VERSION 5.8 ;
BUSBITCHARS "[]" ;
DIVIDERCHAR "/" ;
UNITS
    DATABASE MICRONS 1000 ;
END UNITS

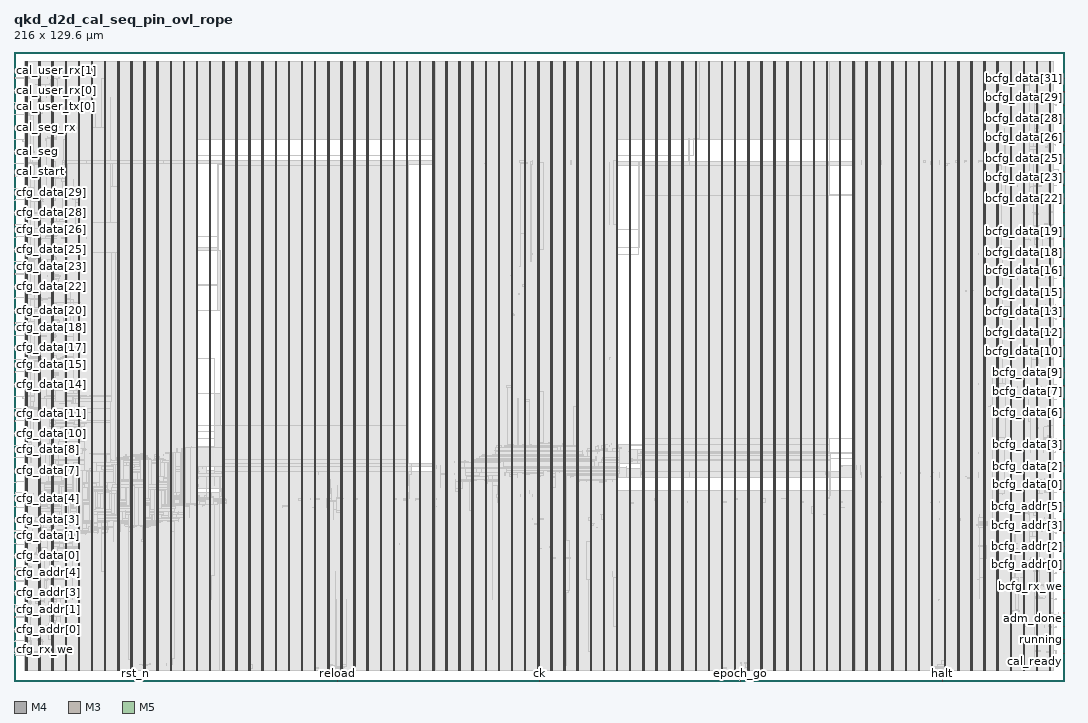
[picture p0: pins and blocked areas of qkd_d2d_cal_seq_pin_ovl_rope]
MACRO qkd_d2d_cal_seq_pin_ovl_rope
  FOREIGN qkd_d2d_cal_seq_pin_ovl_rope 0 0 ;
  CLASS BLOCK ;
  SIZE 216 BY 129.6 ;
  PIN adm_done
    DIRECTION OUTPUT ;
    USE SIGNAL ;
    PORT
      LAYER M4 ;
        RECT  215.808 11.184 216 11.208 ;
    END
  END adm_done
  PIN bcfg_addr[0]
    DIRECTION INPUT ;
    USE SIGNAL ;
    PORT
      LAYER M4 ;
        RECT  215.808 22.224 216 22.248 ;
    END
  END bcfg_addr[0]
  PIN bcfg_addr[1]
    DIRECTION INPUT ;
    USE SIGNAL ;
    PORT
      LAYER M4 ;
        RECT  215.808 24.96 216 24.984 ;
    END
  END bcfg_addr[1]
  PIN bcfg_addr[2]
    DIRECTION INPUT ;
    USE SIGNAL ;
    PORT
      LAYER M4 ;
        RECT  215.808 27.696 216 27.72 ;
    END
  END bcfg_addr[2]
  PIN bcfg_addr[3]
    DIRECTION INPUT ;
    USE SIGNAL ;
    PORT
      LAYER M4 ;
        RECT  215.808 30.432 216 30.456 ;
    END
  END bcfg_addr[3]
  PIN bcfg_addr[4]
    DIRECTION INPUT ;
    USE SIGNAL ;
    PORT
      LAYER M4 ;
        RECT  215.808 33.216 216 33.24 ;
    END
  END bcfg_addr[4]
  PIN bcfg_addr[5]
    DIRECTION INPUT ;
    USE SIGNAL ;
    PORT
      LAYER M4 ;
        RECT  215.808 35.952 216 35.976 ;
    END
  END bcfg_addr[5]
  PIN bcfg_data[0]
    DIRECTION INPUT ;
    USE SIGNAL ;
    PORT
      LAYER M4 ;
        RECT  215.808 38.688 216 38.712 ;
    END
  END bcfg_data[0]
  PIN bcfg_data[10]
    DIRECTION INPUT ;
    USE SIGNAL ;
    PORT
      LAYER M4 ;
        RECT  215.808 66.192 216 66.216 ;
    END
  END bcfg_data[10]
  PIN bcfg_data[11]
    DIRECTION INPUT ;
    USE SIGNAL ;
    PORT
      LAYER M4 ;
        RECT  215.808 68.928 216 68.952 ;
    END
  END bcfg_data[11]
  PIN bcfg_data[12]
    DIRECTION INPUT ;
    USE SIGNAL ;
    PORT
      LAYER M4 ;
        RECT  215.808 71.664 216 71.688 ;
    END
  END bcfg_data[12]
  PIN bcfg_data[13]
    DIRECTION INPUT ;
    USE SIGNAL ;
    PORT
      LAYER M4 ;
        RECT  215.808 74.448 216 74.472 ;
    END
  END bcfg_data[13]
  PIN bcfg_data[14]
    DIRECTION INPUT ;
    USE SIGNAL ;
    PORT
      LAYER M4 ;
        RECT  215.808 77.184 216 77.208 ;
    END
  END bcfg_data[14]
  PIN bcfg_data[15]
    DIRECTION INPUT ;
    USE SIGNAL ;
    PORT
      LAYER M4 ;
        RECT  215.808 79.92 216 79.944 ;
    END
  END bcfg_data[15]
  PIN bcfg_data[16]
    DIRECTION INPUT ;
    USE SIGNAL ;
    PORT
      LAYER M4 ;
        RECT  215.808 82.704 216 82.728 ;
    END
  END bcfg_data[16]
  PIN bcfg_data[17]
    DIRECTION INPUT ;
    USE SIGNAL ;
    PORT
      LAYER M4 ;
        RECT  215.808 85.44 216 85.464 ;
    END
  END bcfg_data[17]
  PIN bcfg_data[18]
    DIRECTION INPUT ;
    USE SIGNAL ;
    PORT
      LAYER M4 ;
        RECT  215.808 88.176 216 88.2 ;
    END
  END bcfg_data[18]
  PIN bcfg_data[19]
    DIRECTION INPUT ;
    USE SIGNAL ;
    PORT
      LAYER M4 ;
        RECT  215.808 90.912 216 90.936 ;
    END
  END bcfg_data[19]
  PIN bcfg_data[1]
    DIRECTION INPUT ;
    USE SIGNAL ;
    PORT
      LAYER M4 ;
        RECT  215.808 41.424 216 41.448 ;
    END
  END bcfg_data[1]
  PIN bcfg_data[20]
    DIRECTION INPUT ;
    USE SIGNAL ;
    PORT
      LAYER M4 ;
        RECT  215.808 93.696 216 93.72 ;
    END
  END bcfg_data[20]
  PIN bcfg_data[21]
    DIRECTION INPUT ;
    USE SIGNAL ;
    PORT
      LAYER M4 ;
        RECT  215.808 96.432 216 96.456 ;
    END
  END bcfg_data[21]
  PIN bcfg_data[22]
    DIRECTION INPUT ;
    USE SIGNAL ;
    PORT
      LAYER M4 ;
        RECT  215.808 99.168 216 99.192 ;
    END
  END bcfg_data[22]
  PIN bcfg_data[23]
    DIRECTION INPUT ;
    USE SIGNAL ;
    PORT
      LAYER M4 ;
        RECT  215.808 101.904 216 101.928 ;
    END
  END bcfg_data[23]
  PIN bcfg_data[24]
    DIRECTION INPUT ;
    USE SIGNAL ;
    PORT
      LAYER M4 ;
        RECT  215.808 104.688 216 104.712 ;
    END
  END bcfg_data[24]
  PIN bcfg_data[25]
    DIRECTION INPUT ;
    USE SIGNAL ;
    PORT
      LAYER M4 ;
        RECT  215.808 107.424 216 107.448 ;
    END
  END bcfg_data[25]
  PIN bcfg_data[26]
    DIRECTION INPUT ;
    USE SIGNAL ;
    PORT
      LAYER M4 ;
        RECT  215.808 110.16 216 110.184 ;
    END
  END bcfg_data[26]
  PIN bcfg_data[27]
    DIRECTION INPUT ;
    USE SIGNAL ;
    PORT
      LAYER M4 ;
        RECT  215.808 112.944 216 112.968 ;
    END
  END bcfg_data[27]
  PIN bcfg_data[28]
    DIRECTION INPUT ;
    USE SIGNAL ;
    PORT
      LAYER M4 ;
        RECT  215.808 115.68 216 115.704 ;
    END
  END bcfg_data[28]
  PIN bcfg_data[29]
    DIRECTION INPUT ;
    USE SIGNAL ;
    PORT
      LAYER M4 ;
        RECT  215.808 118.416 216 118.44 ;
    END
  END bcfg_data[29]
  PIN bcfg_data[2]
    DIRECTION INPUT ;
    USE SIGNAL ;
    PORT
      LAYER M4 ;
        RECT  215.808 44.208 216 44.232 ;
    END
  END bcfg_data[2]
  PIN bcfg_data[30]
    DIRECTION INPUT ;
    USE SIGNAL ;
    PORT
      LAYER M4 ;
        RECT  215.808 121.152 216 121.176 ;
    END
  END bcfg_data[30]
  PIN bcfg_data[31]
    DIRECTION INPUT ;
    USE SIGNAL ;
    PORT
      LAYER M4 ;
        RECT  215.808 123.936 216 123.96 ;
    END
  END bcfg_data[31]
  PIN bcfg_data[3]
    DIRECTION INPUT ;
    USE SIGNAL ;
    PORT
      LAYER M4 ;
        RECT  215.808 46.944 216 46.968 ;
    END
  END bcfg_data[3]
  PIN bcfg_data[4]
    DIRECTION INPUT ;
    USE SIGNAL ;
    PORT
      LAYER M4 ;
        RECT  215.808 49.68 216 49.704 ;
    END
  END bcfg_data[4]
  PIN bcfg_data[5]
    DIRECTION INPUT ;
    USE SIGNAL ;
    PORT
      LAYER M4 ;
        RECT  215.808 52.464 216 52.488 ;
    END
  END bcfg_data[5]
  PIN bcfg_data[6]
    DIRECTION INPUT ;
    USE SIGNAL ;
    PORT
      LAYER M4 ;
        RECT  215.808 55.2 216 55.224 ;
    END
  END bcfg_data[6]
  PIN bcfg_data[7]
    DIRECTION INPUT ;
    USE SIGNAL ;
    PORT
      LAYER M4 ;
        RECT  215.808 57.936 216 57.96 ;
    END
  END bcfg_data[7]
  PIN bcfg_data[8]
    DIRECTION INPUT ;
    USE SIGNAL ;
    PORT
      LAYER M4 ;
        RECT  215.808 60.672 216 60.696 ;
    END
  END bcfg_data[8]
  PIN bcfg_data[9]
    DIRECTION INPUT ;
    USE SIGNAL ;
    PORT
      LAYER M4 ;
        RECT  215.808 63.456 216 63.48 ;
    END
  END bcfg_data[9]
  PIN bcfg_rx_we
    DIRECTION INPUT ;
    USE SIGNAL ;
    PORT
      LAYER M4 ;
        RECT  215.808 19.44 216 19.464 ;
    END
  END bcfg_rx_we
  PIN bcfg_tx_we
    DIRECTION INPUT ;
    USE SIGNAL ;
    PORT
      LAYER M4 ;
        RECT  215.808 16.704 216 16.728 ;
    END
  END bcfg_tx_we
  PIN cal_ready
    DIRECTION OUTPUT ;
    USE SIGNAL ;
    PORT
      LAYER M4 ;
        RECT  215.808 5.712 216 5.736 ;
    END
  END cal_ready
  PIN cal_seg
    DIRECTION OUTPUT ;
    USE SIGNAL ;
    PORT
      LAYER M4 ;
        RECT  0 108.912 0.192 108.936 ;
    END
  END cal_seg
  PIN cal_seg_rx
    DIRECTION OUTPUT ;
    USE SIGNAL ;
    PORT
      LAYER M4 ;
        RECT  0 113.952 0.192 113.976 ;
    END
  END cal_seg_rx
  PIN cal_start
    DIRECTION OUTPUT ;
    USE SIGNAL ;
    PORT
      LAYER M4 ;
        RECT  0 106.416 0.192 106.44 ;
    END
  END cal_start
  PIN cal_start_rx
    DIRECTION OUTPUT ;
    USE SIGNAL ;
    PORT
      LAYER M4 ;
        RECT  0 111.408 0.192 111.432 ;
    END
  END cal_start_rx
  PIN cal_user_rx[0]
    DIRECTION OUTPUT ;
    USE SIGNAL ;
    PORT
      LAYER M4 ;
        RECT  0 121.488 0.192 121.512 ;
    END
  END cal_user_rx[0]
  PIN cal_user_rx[1]
    DIRECTION OUTPUT ;
    USE SIGNAL ;
    PORT
      LAYER M4 ;
        RECT  0 124.032 0.192 124.056 ;
    END
  END cal_user_rx[1]
  PIN cal_user_tx[0]
    DIRECTION OUTPUT ;
    USE SIGNAL ;
    PORT
      LAYER M4 ;
        RECT  0 116.496 0.192 116.52 ;
    END
  END cal_user_tx[0]
  PIN cal_user_tx[1]
    DIRECTION OUTPUT ;
    USE SIGNAL ;
    PORT
      LAYER M4 ;
        RECT  0 118.992 0.192 119.016 ;
    END
  END cal_user_tx[1]
  PIN cfg_addr[0]
    DIRECTION OUTPUT ;
    USE SIGNAL ;
    PORT
      LAYER M4 ;
        RECT  0 10.656 0.192 10.68 ;
    END
  END cfg_addr[0]
  PIN cfg_addr[1]
    DIRECTION OUTPUT ;
    USE SIGNAL ;
    PORT
      LAYER M4 ;
        RECT  0 13.152 0.192 13.176 ;
    END
  END cfg_addr[1]
  PIN cfg_addr[2]
    DIRECTION OUTPUT ;
    USE SIGNAL ;
    PORT
      LAYER M4 ;
        RECT  0 15.696 0.192 15.72 ;
    END
  END cfg_addr[2]
  PIN cfg_addr[3]
    DIRECTION OUTPUT ;
    USE SIGNAL ;
    PORT
      LAYER M4 ;
        RECT  0 18.192 0.192 18.216 ;
    END
  END cfg_addr[3]
  PIN cfg_addr[4]
    DIRECTION OUTPUT ;
    USE SIGNAL ;
    PORT
      LAYER M4 ;
        RECT  0 20.688 0.192 20.712 ;
    END
  END cfg_addr[4]
  PIN cfg_addr[5]
    DIRECTION OUTPUT ;
    USE SIGNAL ;
    PORT
      LAYER M4 ;
        RECT  0 23.232 0.192 23.256 ;
    END
  END cfg_addr[5]
  PIN cfg_data[0]
    DIRECTION OUTPUT ;
    USE SIGNAL ;
    PORT
      LAYER M4 ;
        RECT  0 25.776 0.192 25.8 ;
    END
  END cfg_data[0]
  PIN cfg_data[10]
    DIRECTION OUTPUT ;
    USE SIGNAL ;
    PORT
      LAYER M4 ;
        RECT  0 50.928 0.192 50.952 ;
    END
  END cfg_data[10]
  PIN cfg_data[11]
    DIRECTION OUTPUT ;
    USE SIGNAL ;
    PORT
      LAYER M4 ;
        RECT  0 53.472 0.192 53.496 ;
    END
  END cfg_data[11]
  PIN cfg_data[12]
    DIRECTION OUTPUT ;
    USE SIGNAL ;
    PORT
      LAYER M4 ;
        RECT  0 56.016 0.192 56.04 ;
    END
  END cfg_data[12]
  PIN cfg_data[13]
    DIRECTION OUTPUT ;
    USE SIGNAL ;
    PORT
      LAYER M4 ;
        RECT  0 58.512 0.192 58.536 ;
    END
  END cfg_data[13]
  PIN cfg_data[14]
    DIRECTION OUTPUT ;
    USE SIGNAL ;
    PORT
      LAYER M4 ;
        RECT  0 61.008 0.192 61.032 ;
    END
  END cfg_data[14]
  PIN cfg_data[15]
    DIRECTION OUTPUT ;
    USE SIGNAL ;
    PORT
      LAYER M4 ;
        RECT  0 63.552 0.192 63.576 ;
    END
  END cfg_data[15]
  PIN cfg_data[16]
    DIRECTION OUTPUT ;
    USE SIGNAL ;
    PORT
      LAYER M4 ;
        RECT  0 66.096 0.192 66.12 ;
    END
  END cfg_data[16]
  PIN cfg_data[17]
    DIRECTION OUTPUT ;
    USE SIGNAL ;
    PORT
      LAYER M4 ;
        RECT  0 68.592 0.192 68.616 ;
    END
  END cfg_data[17]
  PIN cfg_data[18]
    DIRECTION OUTPUT ;
    USE SIGNAL ;
    PORT
      LAYER M4 ;
        RECT  0 71.088 0.192 71.112 ;
    END
  END cfg_data[18]
  PIN cfg_data[19]
    DIRECTION OUTPUT ;
    USE SIGNAL ;
    PORT
      LAYER M4 ;
        RECT  0 73.632 0.192 73.656 ;
    END
  END cfg_data[19]
  PIN cfg_data[1]
    DIRECTION OUTPUT ;
    USE SIGNAL ;
    PORT
      LAYER M4 ;
        RECT  0 28.272 0.192 28.296 ;
    END
  END cfg_data[1]
  PIN cfg_data[20]
    DIRECTION OUTPUT ;
    USE SIGNAL ;
    PORT
      LAYER M4 ;
        RECT  0 76.176 0.192 76.2 ;
    END
  END cfg_data[20]
  PIN cfg_data[21]
    DIRECTION OUTPUT ;
    USE SIGNAL ;
    PORT
      LAYER M4 ;
        RECT  0 78.672 0.192 78.696 ;
    END
  END cfg_data[21]
  PIN cfg_data[22]
    DIRECTION OUTPUT ;
    USE SIGNAL ;
    PORT
      LAYER M4 ;
        RECT  0 81.168 0.192 81.192 ;
    END
  END cfg_data[22]
  PIN cfg_data[23]
    DIRECTION OUTPUT ;
    USE SIGNAL ;
    PORT
      LAYER M4 ;
        RECT  0 83.712 0.192 83.736 ;
    END
  END cfg_data[23]
  PIN cfg_data[24]
    DIRECTION OUTPUT ;
    USE SIGNAL ;
    PORT
      LAYER M4 ;
        RECT  0 86.256 0.192 86.28 ;
    END
  END cfg_data[24]
  PIN cfg_data[25]
    DIRECTION OUTPUT ;
    USE SIGNAL ;
    PORT
      LAYER M4 ;
        RECT  0 88.752 0.192 88.776 ;
    END
  END cfg_data[25]
  PIN cfg_data[26]
    DIRECTION OUTPUT ;
    USE SIGNAL ;
    PORT
      LAYER M4 ;
        RECT  0 91.248 0.192 91.272 ;
    END
  END cfg_data[26]
  PIN cfg_data[27]
    DIRECTION OUTPUT ;
    USE SIGNAL ;
    PORT
      LAYER M4 ;
        RECT  0 93.792 0.192 93.816 ;
    END
  END cfg_data[27]
  PIN cfg_data[28]
    DIRECTION OUTPUT ;
    USE SIGNAL ;
    PORT
      LAYER M4 ;
        RECT  0 96.336 0.192 96.36 ;
    END
  END cfg_data[28]
  PIN cfg_data[29]
    DIRECTION OUTPUT ;
    USE SIGNAL ;
    PORT
      LAYER M4 ;
        RECT  0 98.832 0.192 98.856 ;
    END
  END cfg_data[29]
  PIN cfg_data[2]
    DIRECTION OUTPUT ;
    USE SIGNAL ;
    PORT
      LAYER M4 ;
        RECT  0 30.768 0.192 30.792 ;
    END
  END cfg_data[2]
  PIN cfg_data[30]
    DIRECTION OUTPUT ;
    USE SIGNAL ;
    PORT
      LAYER M4 ;
        RECT  0 101.328 0.192 101.352 ;
    END
  END cfg_data[30]
  PIN cfg_data[31]
    DIRECTION OUTPUT ;
    USE SIGNAL ;
    PORT
      LAYER M4 ;
        RECT  0 103.872 0.192 103.896 ;
    END
  END cfg_data[31]
  PIN cfg_data[3]
    DIRECTION OUTPUT ;
    USE SIGNAL ;
    PORT
      LAYER M4 ;
        RECT  0 33.312 0.192 33.336 ;
    END
  END cfg_data[3]
  PIN cfg_data[4]
    DIRECTION OUTPUT ;
    USE SIGNAL ;
    PORT
      LAYER M4 ;
        RECT  0 35.856 0.192 35.88 ;
    END
  END cfg_data[4]
  PIN cfg_data[5]
    DIRECTION OUTPUT ;
    USE SIGNAL ;
    PORT
      LAYER M4 ;
        RECT  0 38.352 0.192 38.376 ;
    END
  END cfg_data[5]
  PIN cfg_data[6]
    DIRECTION OUTPUT ;
    USE SIGNAL ;
    PORT
      LAYER M4 ;
        RECT  0 40.848 0.192 40.872 ;
    END
  END cfg_data[6]
  PIN cfg_data[7]
    DIRECTION OUTPUT ;
    USE SIGNAL ;
    PORT
      LAYER M4 ;
        RECT  0 43.392 0.192 43.416 ;
    END
  END cfg_data[7]
  PIN cfg_data[8]
    DIRECTION OUTPUT ;
    USE SIGNAL ;
    PORT
      LAYER M4 ;
        RECT  0 45.888 0.192 45.912 ;
    END
  END cfg_data[8]
  PIN cfg_data[9]
    DIRECTION OUTPUT ;
    USE SIGNAL ;
    PORT
      LAYER M4 ;
        RECT  0 48.432 0.192 48.456 ;
    END
  END cfg_data[9]
  PIN cfg_rx_we
    DIRECTION OUTPUT ;
    USE SIGNAL ;
    PORT
      LAYER M4 ;
        RECT  0 8.112 0.192 8.136 ;
    END
  END cfg_rx_we
  PIN cfg_tx_we
    DIRECTION OUTPUT ;
    USE SIGNAL ;
    PORT
      LAYER M4 ;
        RECT  0 5.616 0.192 5.64 ;
    END
  END cfg_tx_we
  PIN ck
    DIRECTION INPUT ;
    USE SIGNAL ;
    PORT
      LAYER M3 ;
        RECT  108 0 108.018 0.144 ;
    END
  END ck
  PIN epoch_go
    DIRECTION INPUT ;
    USE SIGNAL ;
    PORT
      LAYER M5 ;
        RECT  149.472 0 149.496 0.192 ;
    END
  END epoch_go
  PIN fault
    DIRECTION OUTPUT ;
    USE SIGNAL ;
    PORT
      LAYER M4 ;
        RECT  215.808 13.968 216 13.992 ;
    END
  END fault
  PIN halt
    DIRECTION INPUT ;
    USE SIGNAL ;
    PORT
      LAYER M3 ;
        RECT  190.944 0 190.962 0.144 ;
    END
  END halt
  PIN reload
    DIRECTION INPUT ;
    USE SIGNAL ;
    PORT
      LAYER M5 ;
        RECT  66.528 0 66.552 0.192 ;
    END
  END reload
  PIN rst_n
    DIRECTION INPUT ;
    USE SIGNAL ;
    PORT
      LAYER M3 ;
        RECT  25.056 0 25.074 0.144 ;
    END
  END rst_n
  PIN running
    DIRECTION OUTPUT ;
    USE SIGNAL ;
    PORT
      LAYER M4 ;
        RECT  215.808 8.448 216 8.472 ;
    END
  END running
  PIN VDD
    DIRECTION INOUT ;
    USE POWER ;
    PORT
      LAYER M5 ;
        RECT  213.192 2.151 213.312 127.449 ;
        RECT  210.492 2.151 210.612 127.449 ;
        RECT  207.792 2.151 207.912 127.449 ;
        RECT  205.092 2.151 205.212 127.449 ;
        RECT  202.392 2.151 202.512 127.449 ;
        RECT  199.692 2.151 199.812 127.449 ;
        RECT  196.992 2.151 197.112 127.449 ;
        RECT  194.292 2.151 194.412 127.449 ;
        RECT  191.592 2.151 191.712 127.449 ;
        RECT  188.892 2.151 189.012 127.449 ;
        RECT  186.192 2.151 186.312 127.449 ;
        RECT  183.492 2.151 183.612 127.449 ;
        RECT  180.792 2.151 180.912 127.449 ;
        RECT  178.092 2.151 178.212 127.449 ;
        RECT  175.392 2.151 175.512 127.449 ;
        RECT  172.692 2.151 172.812 127.449 ;
        RECT  169.992 2.151 170.112 127.449 ;
        RECT  167.292 2.151 167.412 127.449 ;
        RECT  164.592 2.151 164.712 127.449 ;
        RECT  161.892 2.151 162.012 127.449 ;
        RECT  159.192 2.151 159.312 127.449 ;
        RECT  156.492 2.151 156.612 127.449 ;
        RECT  153.792 2.151 153.912 127.449 ;
        RECT  151.092 2.151 151.212 127.449 ;
        RECT  148.392 2.151 148.512 127.449 ;
        RECT  145.692 2.151 145.812 127.449 ;
        RECT  142.992 2.151 143.112 127.449 ;
        RECT  140.292 2.151 140.412 127.449 ;
        RECT  137.592 2.151 137.712 127.449 ;
        RECT  134.892 2.151 135.012 127.449 ;
        RECT  132.192 2.151 132.312 127.449 ;
        RECT  129.492 2.151 129.612 127.449 ;
        RECT  126.792 2.151 126.912 127.449 ;
        RECT  124.092 2.151 124.212 127.449 ;
        RECT  121.392 2.151 121.512 127.449 ;
        RECT  118.692 2.151 118.812 127.449 ;
        RECT  115.992 2.151 116.112 127.449 ;
        RECT  113.292 2.151 113.412 127.449 ;
        RECT  110.592 2.151 110.712 127.449 ;
        RECT  107.892 2.151 108.012 127.449 ;
        RECT  105.192 2.151 105.312 127.449 ;
        RECT  102.492 2.151 102.612 127.449 ;
        RECT  99.792 2.151 99.912 127.449 ;
        RECT  97.092 2.151 97.212 127.449 ;
        RECT  94.392 2.151 94.512 127.449 ;
        RECT  91.692 2.151 91.812 127.449 ;
        RECT  88.992 2.151 89.112 127.449 ;
        RECT  86.292 2.151 86.412 127.449 ;
        RECT  83.592 2.151 83.712 127.449 ;
        RECT  80.892 2.151 81.012 127.449 ;
        RECT  78.192 2.151 78.312 127.449 ;
        RECT  75.492 2.151 75.612 127.449 ;
        RECT  72.792 2.151 72.912 127.449 ;
        RECT  70.092 2.151 70.212 127.449 ;
        RECT  67.392 2.151 67.512 127.449 ;
        RECT  64.692 2.151 64.812 127.449 ;
        RECT  61.992 2.151 62.112 127.449 ;
        RECT  59.292 2.151 59.412 127.449 ;
        RECT  56.592 2.151 56.712 127.449 ;
        RECT  53.892 2.151 54.012 127.449 ;
        RECT  51.192 2.151 51.312 127.449 ;
        RECT  48.492 2.151 48.612 127.449 ;
        RECT  45.792 2.151 45.912 127.449 ;
        RECT  43.092 2.151 43.212 127.449 ;
        RECT  40.392 2.151 40.512 127.449 ;
        RECT  37.692 2.151 37.812 127.449 ;
        RECT  34.992 2.151 35.112 127.449 ;
        RECT  32.292 2.151 32.412 127.449 ;
        RECT  29.592 2.151 29.712 127.449 ;
        RECT  26.892 2.151 27.012 127.449 ;
        RECT  24.192 2.151 24.312 127.449 ;
        RECT  21.492 2.151 21.612 127.449 ;
        RECT  18.792 2.151 18.912 127.449 ;
        RECT  16.092 2.151 16.212 127.449 ;
        RECT  13.392 2.151 13.512 127.449 ;
        RECT  10.692 2.151 10.812 127.449 ;
        RECT  7.992 2.151 8.112 127.449 ;
        RECT  5.292 2.151 5.412 127.449 ;
        RECT  2.592 2.151 2.712 127.449 ;
    END
  END VDD
  PIN VSS
    DIRECTION INOUT ;
    USE GROUND ;
    PORT
      LAYER M5 ;
        RECT  213 2.137 213.12 127.463 ;
        RECT  210.3 2.137 210.42 127.463 ;
        RECT  207.6 2.137 207.72 127.463 ;
        RECT  204.9 2.137 205.02 127.463 ;
        RECT  202.2 2.137 202.32 127.463 ;
        RECT  199.5 2.137 199.62 127.463 ;
        RECT  196.8 2.137 196.92 127.463 ;
        RECT  194.1 2.137 194.22 127.463 ;
        RECT  191.4 2.137 191.52 127.463 ;
        RECT  188.7 2.137 188.82 127.463 ;
        RECT  186 2.137 186.12 127.463 ;
        RECT  183.3 2.137 183.42 127.463 ;
        RECT  180.6 2.137 180.72 127.463 ;
        RECT  177.9 2.137 178.02 127.463 ;
        RECT  175.2 2.137 175.32 127.463 ;
        RECT  172.5 2.137 172.62 127.463 ;
        RECT  169.8 2.137 169.92 127.463 ;
        RECT  167.1 2.137 167.22 127.463 ;
        RECT  164.4 2.137 164.52 127.463 ;
        RECT  161.7 2.137 161.82 127.463 ;
        RECT  159 2.137 159.12 127.463 ;
        RECT  156.3 2.137 156.42 127.463 ;
        RECT  153.6 2.137 153.72 127.463 ;
        RECT  150.9 2.137 151.02 127.463 ;
        RECT  148.2 2.137 148.32 127.463 ;
        RECT  145.5 2.137 145.62 127.463 ;
        RECT  142.8 2.137 142.92 127.463 ;
        RECT  140.1 2.137 140.22 127.463 ;
        RECT  137.4 2.137 137.52 127.463 ;
        RECT  134.7 2.137 134.82 127.463 ;
        RECT  132 2.137 132.12 127.463 ;
        RECT  129.3 2.137 129.42 127.463 ;
        RECT  126.6 2.137 126.72 127.463 ;
        RECT  123.9 2.137 124.02 127.463 ;
        RECT  121.2 2.137 121.32 127.463 ;
        RECT  118.5 2.137 118.62 127.463 ;
        RECT  115.8 2.137 115.92 127.463 ;
        RECT  113.1 2.137 113.22 127.463 ;
        RECT  110.4 2.137 110.52 127.463 ;
        RECT  107.7 2.137 107.82 127.463 ;
        RECT  105 2.137 105.12 127.463 ;
        RECT  102.3 2.137 102.42 127.463 ;
        RECT  99.6 2.137 99.72 127.463 ;
        RECT  96.9 2.137 97.02 127.463 ;
        RECT  94.2 2.137 94.32 127.463 ;
        RECT  91.5 2.137 91.62 127.463 ;
        RECT  88.8 2.137 88.92 127.463 ;
        RECT  86.1 2.137 86.22 127.463 ;
        RECT  83.4 2.137 83.52 127.463 ;
        RECT  80.7 2.137 80.82 127.463 ;
        RECT  78 2.137 78.12 127.463 ;
        RECT  75.3 2.137 75.42 127.463 ;
        RECT  72.6 2.137 72.72 127.463 ;
        RECT  69.9 2.137 70.02 127.463 ;
        RECT  67.2 2.137 67.32 127.463 ;
        RECT  64.5 2.137 64.62 127.463 ;
        RECT  61.8 2.137 61.92 127.463 ;
        RECT  59.1 2.137 59.22 127.463 ;
        RECT  56.4 2.137 56.52 127.463 ;
        RECT  53.7 2.137 53.82 127.463 ;
        RECT  51 2.137 51.12 127.463 ;
        RECT  48.3 2.137 48.42 127.463 ;
        RECT  45.6 2.137 45.72 127.463 ;
        RECT  42.9 2.137 43.02 127.463 ;
        RECT  40.2 2.137 40.32 127.463 ;
        RECT  37.5 2.137 37.62 127.463 ;
        RECT  34.8 2.137 34.92 127.463 ;
        RECT  32.1 2.137 32.22 127.463 ;
        RECT  29.4 2.137 29.52 127.463 ;
        RECT  26.7 2.137 26.82 127.463 ;
        RECT  24 2.137 24.12 127.463 ;
        RECT  21.3 2.137 21.42 127.463 ;
        RECT  18.6 2.137 18.72 127.463 ;
        RECT  15.9 2.137 16.02 127.463 ;
        RECT  13.2 2.137 13.32 127.463 ;
        RECT  10.5 2.137 10.62 127.463 ;
        RECT  7.8 2.137 7.92 127.463 ;
        RECT  5.1 2.137 5.22 127.463 ;
        RECT  2.4 2.137 2.52 127.463 ;
    END
  END VSS
  OBS
    LAYER RVTN ;
     RECT  2.16 2.16 213.84 2.295 ;
     RECT  2.16 2.565 213.84 2.835 ;
     RECT  2.16 3.105 213.84 3.375 ;
     RECT  2.16 3.645 213.84 3.915 ;
     RECT  2.16 4.185 213.84 4.455 ;
     RECT  2.16 4.725 213.84 4.995 ;
     RECT  2.16 5.265 213.84 5.535 ;
     RECT  2.16 5.805 213.84 6.075 ;
     RECT  2.16 6.345 213.84 6.615 ;
     RECT  2.16 6.885 213.84 7.155 ;
     RECT  2.16 7.425 213.84 7.695 ;
     RECT  2.16 7.965 213.84 8.235 ;
     RECT  2.16 8.505 213.84 8.775 ;
     RECT  2.16 9.045 213.84 9.315 ;
     RECT  2.16 9.585 213.84 9.855 ;
     RECT  2.16 10.125 213.84 10.395 ;
     RECT  2.16 10.665 213.84 10.935 ;
     RECT  2.16 11.205 213.84 11.475 ;
     RECT  2.16 11.745 213.84 12.015 ;
     RECT  2.16 12.285 213.84 12.555 ;
     RECT  2.16 12.825 213.84 13.095 ;
     RECT  2.16 13.365 213.84 13.635 ;
     RECT  2.16 13.905 213.84 14.175 ;
     RECT  2.16 14.445 213.84 14.715 ;
     RECT  2.16 14.985 213.84 15.255 ;
     RECT  2.16 15.525 213.84 15.795 ;
     RECT  2.16 16.065 213.84 16.335 ;
     RECT  2.16 16.605 213.84 16.875 ;
     RECT  2.16 17.145 213.84 17.415 ;
     RECT  2.16 17.685 213.84 17.955 ;
     RECT  2.16 18.225 213.84 18.495 ;
     RECT  2.16 18.765 213.84 19.035 ;
     RECT  2.16 19.305 213.84 19.575 ;
     RECT  2.16 19.845 213.84 20.115 ;
     RECT  2.16 20.385 213.84 20.655 ;
     RECT  2.16 20.925 213.84 21.195 ;
     RECT  2.16 21.465 213.84 21.735 ;
     RECT  2.16 22.005 213.84 22.275 ;
     RECT  2.16 22.545 213.84 22.815 ;
     RECT  2.16 23.085 213.84 23.355 ;
     RECT  2.16 23.625 213.84 23.895 ;
     RECT  2.16 24.165 213.84 24.435 ;
     RECT  2.16 24.705 213.84 24.975 ;
     RECT  2.16 25.245 213.84 25.515 ;
     RECT  2.16 25.785 213.84 26.055 ;
     RECT  2.16 26.325 213.84 26.595 ;
     RECT  2.16 26.865 213.84 27.135 ;
     RECT  2.16 27.405 213.84 27.675 ;
     RECT  2.16 27.945 213.84 28.215 ;
     RECT  2.16 28.485 213.84 28.755 ;
     RECT  2.16 29.025 213.84 29.295 ;
     RECT  2.16 29.565 213.84 29.835 ;
     RECT  2.16 30.105 213.84 30.375 ;
     RECT  2.16 30.645 213.84 30.915 ;
     RECT  2.16 31.185 213.84 31.455 ;
     RECT  2.16 31.725 213.84 31.995 ;
     RECT  2.16 32.265 213.84 32.535 ;
     RECT  2.16 32.805 213.84 33.075 ;
     RECT  2.16 33.345 213.84 33.615 ;
     RECT  2.16 33.885 213.84 34.155 ;
     RECT  2.16 34.425 213.84 34.695 ;
     RECT  2.16 34.965 213.84 35.235 ;
     RECT  2.16 35.505 213.84 35.775 ;
     RECT  2.16 36.045 213.84 36.315 ;
     RECT  2.16 36.585 213.84 36.855 ;
     RECT  2.16 37.125 213.84 37.395 ;
     RECT  2.16 37.665 213.84 37.8 ;
     RECT  2.16 37.8 37.8 37.935 ;
     RECT  86.616 37.8 124.2 37.935 ;
     RECT  173.016 37.8 213.84 37.935 ;
     RECT  2.16 38.205 37.8 38.475 ;
     RECT  86.616 38.205 124.2 38.475 ;
     RECT  173.016 38.205 213.84 38.475 ;
     RECT  2.16 38.745 37.8 39.015 ;
     RECT  86.616 38.745 124.2 39.015 ;
     RECT  173.016 38.745 213.84 39.015 ;
     RECT  2.16 39.285 37.8 39.555 ;
     RECT  86.616 39.285 124.2 39.555 ;
     RECT  173.016 39.285 213.84 39.555 ;
     RECT  2.16 39.825 37.8 40.095 ;
     RECT  86.616 39.825 124.2 40.095 ;
     RECT  173.016 39.825 213.84 40.095 ;
     RECT  2.16 40.365 37.8 40.635 ;
     RECT  86.616 40.365 124.2 40.635 ;
     RECT  173.016 40.365 213.84 40.635 ;
     RECT  2.16 40.905 37.8 41.175 ;
     RECT  86.616 40.905 124.2 41.175 ;
     RECT  173.016 40.905 213.84 41.175 ;
     RECT  2.16 41.445 37.8 41.715 ;
     RECT  86.616 41.445 124.2 41.715 ;
     RECT  173.016 41.445 213.84 41.715 ;
     RECT  2.16 41.985 37.8 42.255 ;
     RECT  86.616 41.985 124.2 42.255 ;
     RECT  173.016 41.985 213.84 42.255 ;
     RECT  2.16 42.525 37.8 42.795 ;
     RECT  86.616 42.525 124.2 42.795 ;
     RECT  173.016 42.525 213.84 42.795 ;
     RECT  2.16 43.065 37.8 43.335 ;
     RECT  86.616 43.065 124.2 43.335 ;
     RECT  173.016 43.065 213.84 43.335 ;
     RECT  2.16 43.605 37.8 43.875 ;
     RECT  86.616 43.605 124.2 43.875 ;
     RECT  173.016 43.605 213.84 43.875 ;
     RECT  2.16 44.145 37.8 44.415 ;
     RECT  86.616 44.145 124.2 44.415 ;
     RECT  173.016 44.145 213.84 44.415 ;
     RECT  2.16 44.685 37.8 44.955 ;
     RECT  86.616 44.685 124.2 44.955 ;
     RECT  173.016 44.685 213.84 44.955 ;
     RECT  2.16 45.225 37.8 45.495 ;
     RECT  86.616 45.225 124.2 45.495 ;
     RECT  173.016 45.225 213.84 45.495 ;
     RECT  2.16 45.765 37.8 46.035 ;
     RECT  86.616 45.765 124.2 46.035 ;
     RECT  173.016 45.765 213.84 46.035 ;
     RECT  2.16 46.305 37.8 46.575 ;
     RECT  86.616 46.305 124.2 46.575 ;
     RECT  173.016 46.305 213.84 46.575 ;
     RECT  2.16 46.845 37.8 47.115 ;
     RECT  86.616 46.845 124.2 47.115 ;
     RECT  173.016 46.845 213.84 47.115 ;
     RECT  2.16 47.385 37.8 47.655 ;
     RECT  86.616 47.385 124.2 47.655 ;
     RECT  173.016 47.385 213.84 47.655 ;
     RECT  2.16 47.925 37.8 48.195 ;
     RECT  86.616 47.925 124.2 48.195 ;
     RECT  173.016 47.925 213.84 48.195 ;
     RECT  2.16 48.465 37.8 48.735 ;
     RECT  86.616 48.465 124.2 48.735 ;
     RECT  173.016 48.465 213.84 48.735 ;
     RECT  2.16 49.005 37.8 49.275 ;
     RECT  86.616 49.005 124.2 49.275 ;
     RECT  173.016 49.005 213.84 49.275 ;
     RECT  2.16 49.545 37.8 49.815 ;
     RECT  86.616 49.545 124.2 49.815 ;
     RECT  173.016 49.545 213.84 49.815 ;
     RECT  2.16 50.085 37.8 50.355 ;
     RECT  86.616 50.085 124.2 50.355 ;
     RECT  173.016 50.085 213.84 50.355 ;
     RECT  2.16 50.625 37.8 50.895 ;
     RECT  86.616 50.625 124.2 50.895 ;
     RECT  173.016 50.625 213.84 50.895 ;
     RECT  2.16 51.165 37.8 51.435 ;
     RECT  86.616 51.165 124.2 51.435 ;
     RECT  173.016 51.165 213.84 51.435 ;
     RECT  2.16 51.705 37.8 51.975 ;
     RECT  86.616 51.705 124.2 51.975 ;
     RECT  173.016 51.705 213.84 51.975 ;
     RECT  2.16 52.245 37.8 52.515 ;
     RECT  86.616 52.245 124.2 52.515 ;
     RECT  173.016 52.245 213.84 52.515 ;
     RECT  2.16 52.785 37.8 53.055 ;
     RECT  86.616 52.785 124.2 53.055 ;
     RECT  173.016 52.785 213.84 53.055 ;
     RECT  2.16 53.325 37.8 53.595 ;
     RECT  86.616 53.325 124.2 53.595 ;
     RECT  173.016 53.325 213.84 53.595 ;
     RECT  2.16 53.865 37.8 54.135 ;
     RECT  86.616 53.865 124.2 54.135 ;
     RECT  173.016 53.865 213.84 54.135 ;
     RECT  2.16 54.405 37.8 54.675 ;
     RECT  86.616 54.405 124.2 54.675 ;
     RECT  173.016 54.405 213.84 54.675 ;
     RECT  2.16 54.945 37.8 55.215 ;
     RECT  86.616 54.945 124.2 55.215 ;
     RECT  173.016 54.945 213.84 55.215 ;
     RECT  2.16 55.485 37.8 55.755 ;
     RECT  86.616 55.485 124.2 55.755 ;
     RECT  173.016 55.485 213.84 55.755 ;
     RECT  2.16 56.025 37.8 56.295 ;
     RECT  86.616 56.025 124.2 56.295 ;
     RECT  173.016 56.025 213.84 56.295 ;
     RECT  2.16 56.565 37.8 56.835 ;
     RECT  86.616 56.565 124.2 56.835 ;
     RECT  173.016 56.565 213.84 56.835 ;
     RECT  2.16 57.105 37.8 57.375 ;
     RECT  86.616 57.105 124.2 57.375 ;
     RECT  173.016 57.105 213.84 57.375 ;
     RECT  2.16 57.645 37.8 57.915 ;
     RECT  86.616 57.645 124.2 57.915 ;
     RECT  173.016 57.645 213.84 57.915 ;
     RECT  2.16 58.185 37.8 58.455 ;
     RECT  86.616 58.185 124.2 58.455 ;
     RECT  173.016 58.185 213.84 58.455 ;
     RECT  2.16 58.725 37.8 58.995 ;
     RECT  86.616 58.725 124.2 58.995 ;
     RECT  173.016 58.725 213.84 58.995 ;
     RECT  2.16 59.265 37.8 59.535 ;
     RECT  86.616 59.265 124.2 59.535 ;
     RECT  173.016 59.265 213.84 59.535 ;
     RECT  2.16 59.805 37.8 60.075 ;
     RECT  86.616 59.805 124.2 60.075 ;
     RECT  173.016 59.805 213.84 60.075 ;
     RECT  2.16 60.345 37.8 60.615 ;
     RECT  86.616 60.345 124.2 60.615 ;
     RECT  173.016 60.345 213.84 60.615 ;
     RECT  2.16 60.885 37.8 61.155 ;
     RECT  86.616 60.885 124.2 61.155 ;
     RECT  173.016 60.885 213.84 61.155 ;
     RECT  2.16 61.425 37.8 61.695 ;
     RECT  86.616 61.425 124.2 61.695 ;
     RECT  173.016 61.425 213.84 61.695 ;
     RECT  2.16 61.965 37.8 62.235 ;
     RECT  86.616 61.965 124.2 62.235 ;
     RECT  173.016 61.965 213.84 62.235 ;
     RECT  2.16 62.505 37.8 62.775 ;
     RECT  86.616 62.505 124.2 62.775 ;
     RECT  173.016 62.505 213.84 62.775 ;
     RECT  2.16 63.045 37.8 63.315 ;
     RECT  86.616 63.045 124.2 63.315 ;
     RECT  173.016 63.045 213.84 63.315 ;
     RECT  2.16 63.585 37.8 63.855 ;
     RECT  86.616 63.585 124.2 63.855 ;
     RECT  173.016 63.585 213.84 63.855 ;
     RECT  2.16 64.125 37.8 64.395 ;
     RECT  86.616 64.125 124.2 64.395 ;
     RECT  173.016 64.125 213.84 64.395 ;
     RECT  2.16 64.665 37.8 64.935 ;
     RECT  86.616 64.665 124.2 64.935 ;
     RECT  173.016 64.665 213.84 64.935 ;
     RECT  2.16 65.205 37.8 65.475 ;
     RECT  86.616 65.205 124.2 65.475 ;
     RECT  173.016 65.205 213.84 65.475 ;
     RECT  2.16 65.745 37.8 66.015 ;
     RECT  86.616 65.745 124.2 66.015 ;
     RECT  173.016 65.745 213.84 66.015 ;
     RECT  2.16 66.285 37.8 66.555 ;
     RECT  86.616 66.285 124.2 66.555 ;
     RECT  173.016 66.285 213.84 66.555 ;
     RECT  2.16 66.825 37.8 67.095 ;
     RECT  86.616 66.825 124.2 67.095 ;
     RECT  173.016 66.825 213.84 67.095 ;
     RECT  2.16 67.365 37.8 67.635 ;
     RECT  86.616 67.365 124.2 67.635 ;
     RECT  173.016 67.365 213.84 67.635 ;
     RECT  2.16 67.905 37.8 68.175 ;
     RECT  86.616 67.905 124.2 68.175 ;
     RECT  173.016 67.905 213.84 68.175 ;
     RECT  2.16 68.445 37.8 68.715 ;
     RECT  86.616 68.445 124.2 68.715 ;
     RECT  173.016 68.445 213.84 68.715 ;
     RECT  2.16 68.985 37.8 69.255 ;
     RECT  86.616 68.985 124.2 69.255 ;
     RECT  173.016 68.985 213.84 69.255 ;
     RECT  2.16 69.525 37.8 69.795 ;
     RECT  86.616 69.525 124.2 69.795 ;
     RECT  173.016 69.525 213.84 69.795 ;
     RECT  2.16 70.065 37.8 70.335 ;
     RECT  86.616 70.065 124.2 70.335 ;
     RECT  173.016 70.065 213.84 70.335 ;
     RECT  2.16 70.605 37.8 70.875 ;
     RECT  86.616 70.605 124.2 70.875 ;
     RECT  173.016 70.605 213.84 70.875 ;
     RECT  2.16 71.145 37.8 71.415 ;
     RECT  86.616 71.145 124.2 71.415 ;
     RECT  173.016 71.145 213.84 71.415 ;
     RECT  2.16 71.685 37.8 71.955 ;
     RECT  86.616 71.685 124.2 71.955 ;
     RECT  173.016 71.685 213.84 71.955 ;
     RECT  2.16 72.225 37.8 72.495 ;
     RECT  86.616 72.225 124.2 72.495 ;
     RECT  173.016 72.225 213.84 72.495 ;
     RECT  2.16 72.765 37.8 73.035 ;
     RECT  86.616 72.765 124.2 73.035 ;
     RECT  173.016 72.765 213.84 73.035 ;
     RECT  2.16 73.305 37.8 73.575 ;
     RECT  86.616 73.305 124.2 73.575 ;
     RECT  173.016 73.305 213.84 73.575 ;
     RECT  2.16 73.845 37.8 74.115 ;
     RECT  86.616 73.845 124.2 74.115 ;
     RECT  173.016 73.845 213.84 74.115 ;
     RECT  2.16 74.385 37.8 74.655 ;
     RECT  86.616 74.385 124.2 74.655 ;
     RECT  173.016 74.385 213.84 74.655 ;
     RECT  2.16 74.925 37.8 75.195 ;
     RECT  86.616 74.925 124.2 75.195 ;
     RECT  173.016 74.925 213.84 75.195 ;
     RECT  2.16 75.465 37.8 75.735 ;
     RECT  86.616 75.465 124.2 75.735 ;
     RECT  173.016 75.465 213.84 75.735 ;
     RECT  2.16 76.005 37.8 76.275 ;
     RECT  86.616 76.005 124.2 76.275 ;
     RECT  173.016 76.005 213.84 76.275 ;
     RECT  2.16 76.545 37.8 76.815 ;
     RECT  86.616 76.545 124.2 76.815 ;
     RECT  173.016 76.545 213.84 76.815 ;
     RECT  2.16 77.085 37.8 77.355 ;
     RECT  86.616 77.085 124.2 77.355 ;
     RECT  173.016 77.085 213.84 77.355 ;
     RECT  2.16 77.625 37.8 77.895 ;
     RECT  86.616 77.625 124.2 77.895 ;
     RECT  173.016 77.625 213.84 77.895 ;
     RECT  2.16 78.165 37.8 78.435 ;
     RECT  86.616 78.165 124.2 78.435 ;
     RECT  173.016 78.165 213.84 78.435 ;
     RECT  2.16 78.705 37.8 78.975 ;
     RECT  86.616 78.705 124.2 78.975 ;
     RECT  173.016 78.705 213.84 78.975 ;
     RECT  2.16 79.245 37.8 79.515 ;
     RECT  86.616 79.245 124.2 79.515 ;
     RECT  173.016 79.245 213.84 79.515 ;
     RECT  2.16 79.785 37.8 80.055 ;
     RECT  86.616 79.785 124.2 80.055 ;
     RECT  173.016 79.785 213.84 80.055 ;
     RECT  2.16 80.325 37.8 80.595 ;
     RECT  86.616 80.325 124.2 80.595 ;
     RECT  173.016 80.325 213.84 80.595 ;
     RECT  2.16 80.865 37.8 81.135 ;
     RECT  86.616 80.865 124.2 81.135 ;
     RECT  173.016 80.865 213.84 81.135 ;
     RECT  2.16 81.405 37.8 81.675 ;
     RECT  86.616 81.405 124.2 81.675 ;
     RECT  173.016 81.405 213.84 81.675 ;
     RECT  2.16 81.945 37.8 82.215 ;
     RECT  86.616 81.945 124.2 82.215 ;
     RECT  173.016 81.945 213.84 82.215 ;
     RECT  2.16 82.485 37.8 82.755 ;
     RECT  86.616 82.485 124.2 82.755 ;
     RECT  173.016 82.485 213.84 82.755 ;
     RECT  2.16 83.025 37.8 83.295 ;
     RECT  86.616 83.025 124.2 83.295 ;
     RECT  173.016 83.025 213.84 83.295 ;
     RECT  2.16 83.565 37.8 83.835 ;
     RECT  86.616 83.565 124.2 83.835 ;
     RECT  173.016 83.565 213.84 83.835 ;
     RECT  2.16 84.105 37.8 84.375 ;
     RECT  86.616 84.105 124.2 84.375 ;
     RECT  173.016 84.105 213.84 84.375 ;
     RECT  2.16 84.645 37.8 84.915 ;
     RECT  86.616 84.645 124.2 84.915 ;
     RECT  173.016 84.645 213.84 84.915 ;
     RECT  2.16 85.185 37.8 85.455 ;
     RECT  86.616 85.185 124.2 85.455 ;
     RECT  173.016 85.185 213.84 85.455 ;
     RECT  2.16 85.725 37.8 85.995 ;
     RECT  86.616 85.725 124.2 85.995 ;
     RECT  173.016 85.725 213.84 85.995 ;
     RECT  2.16 86.265 37.8 86.535 ;
     RECT  86.616 86.265 124.2 86.535 ;
     RECT  173.016 86.265 213.84 86.535 ;
     RECT  2.16 86.805 37.8 87.075 ;
     RECT  86.616 86.805 124.2 87.075 ;
     RECT  173.016 86.805 213.84 87.075 ;
     RECT  2.16 87.345 37.8 87.615 ;
     RECT  86.616 87.345 124.2 87.615 ;
     RECT  173.016 87.345 213.84 87.615 ;
     RECT  2.16 87.885 37.8 88.155 ;
     RECT  86.616 87.885 124.2 88.155 ;
     RECT  173.016 87.885 213.84 88.155 ;
     RECT  2.16 88.425 37.8 88.695 ;
     RECT  86.616 88.425 124.2 88.695 ;
     RECT  173.016 88.425 213.84 88.695 ;
     RECT  2.16 88.965 37.8 89.235 ;
     RECT  86.616 88.965 124.2 89.235 ;
     RECT  173.016 88.965 213.84 89.235 ;
     RECT  2.16 89.505 37.8 89.775 ;
     RECT  86.616 89.505 124.2 89.775 ;
     RECT  173.016 89.505 213.84 89.775 ;
     RECT  2.16 90.045 37.8 90.315 ;
     RECT  86.616 90.045 124.2 90.315 ;
     RECT  173.016 90.045 213.84 90.315 ;
     RECT  2.16 90.585 37.8 90.855 ;
     RECT  86.616 90.585 124.2 90.855 ;
     RECT  173.016 90.585 213.84 90.855 ;
     RECT  2.16 91.125 37.8 91.395 ;
     RECT  86.616 91.125 124.2 91.395 ;
     RECT  173.016 91.125 213.84 91.395 ;
     RECT  2.16 91.665 37.8 91.935 ;
     RECT  86.616 91.665 124.2 91.935 ;
     RECT  173.016 91.665 213.84 91.935 ;
     RECT  2.16 92.205 37.8 92.475 ;
     RECT  86.616 92.205 124.2 92.475 ;
     RECT  173.016 92.205 213.84 92.475 ;
     RECT  2.16 92.745 37.8 93.015 ;
     RECT  86.616 92.745 124.2 93.015 ;
     RECT  173.016 92.745 213.84 93.015 ;
     RECT  2.16 93.285 37.8 93.555 ;
     RECT  86.616 93.285 124.2 93.555 ;
     RECT  173.016 93.285 213.84 93.555 ;
     RECT  2.16 93.825 37.8 94.095 ;
     RECT  86.616 93.825 124.2 94.095 ;
     RECT  173.016 93.825 213.84 94.095 ;
     RECT  2.16 94.365 37.8 94.635 ;
     RECT  86.616 94.365 124.2 94.635 ;
     RECT  173.016 94.365 213.84 94.635 ;
     RECT  2.16 94.905 37.8 95.175 ;
     RECT  86.616 94.905 124.2 95.175 ;
     RECT  173.016 94.905 213.84 95.175 ;
     RECT  2.16 95.445 37.8 95.715 ;
     RECT  86.616 95.445 124.2 95.715 ;
     RECT  173.016 95.445 213.84 95.715 ;
     RECT  2.16 95.985 37.8 96.255 ;
     RECT  86.616 95.985 124.2 96.255 ;
     RECT  173.016 95.985 213.84 96.255 ;
     RECT  2.16 96.525 37.8 96.795 ;
     RECT  86.616 96.525 124.2 96.795 ;
     RECT  173.016 96.525 213.84 96.795 ;
     RECT  2.16 97.065 37.8 97.335 ;
     RECT  86.616 97.065 124.2 97.335 ;
     RECT  173.016 97.065 213.84 97.335 ;
     RECT  2.16 97.605 37.8 97.875 ;
     RECT  86.616 97.605 124.2 97.875 ;
     RECT  173.016 97.605 213.84 97.875 ;
     RECT  2.16 98.145 37.8 98.415 ;
     RECT  86.616 98.145 124.2 98.415 ;
     RECT  173.016 98.145 213.84 98.415 ;
     RECT  2.16 98.685 37.8 98.955 ;
     RECT  86.616 98.685 124.2 98.955 ;
     RECT  173.016 98.685 213.84 98.955 ;
     RECT  2.16 99.225 37.8 99.495 ;
     RECT  86.616 99.225 124.2 99.495 ;
     RECT  173.016 99.225 213.84 99.495 ;
     RECT  2.16 99.765 37.8 100.035 ;
     RECT  86.616 99.765 124.2 100.035 ;
     RECT  173.016 99.765 213.84 100.035 ;
     RECT  2.16 100.305 37.8 100.575 ;
     RECT  86.616 100.305 124.2 100.575 ;
     RECT  173.016 100.305 213.84 100.575 ;
     RECT  2.16 100.845 37.8 101.115 ;
     RECT  86.616 100.845 124.2 101.115 ;
     RECT  173.016 100.845 213.84 101.115 ;
     RECT  2.16 101.385 37.8 101.655 ;
     RECT  86.616 101.385 124.2 101.655 ;
     RECT  173.016 101.385 213.84 101.655 ;
     RECT  2.16 101.925 37.8 102.195 ;
     RECT  86.616 101.925 124.2 102.195 ;
     RECT  173.016 101.925 213.84 102.195 ;
     RECT  2.16 102.465 37.8 102.735 ;
     RECT  86.616 102.465 124.2 102.735 ;
     RECT  173.016 102.465 213.84 102.735 ;
     RECT  2.16 103.005 37.8 103.275 ;
     RECT  86.616 103.005 124.2 103.275 ;
     RECT  173.016 103.005 213.84 103.275 ;
     RECT  2.16 103.545 37.8 103.815 ;
     RECT  86.616 103.545 124.2 103.815 ;
     RECT  173.016 103.545 213.84 103.815 ;
     RECT  2.16 104.085 37.8 104.355 ;
     RECT  86.616 104.085 124.2 104.355 ;
     RECT  173.016 104.085 213.84 104.355 ;
     RECT  2.16 104.625 37.8 104.895 ;
     RECT  86.616 104.625 124.2 104.895 ;
     RECT  173.016 104.625 213.84 104.895 ;
     RECT  2.16 105.165 37.8 105.435 ;
     RECT  86.616 105.165 124.2 105.435 ;
     RECT  173.016 105.165 213.84 105.435 ;
     RECT  2.16 105.705 37.8 105.975 ;
     RECT  86.616 105.705 124.2 105.975 ;
     RECT  173.016 105.705 213.84 105.975 ;
     RECT  2.16 106.245 37.8 106.515 ;
     RECT  86.616 106.245 124.2 106.515 ;
     RECT  173.016 106.245 213.84 106.515 ;
     RECT  2.16 106.785 37.8 107.055 ;
     RECT  86.616 106.785 124.2 107.055 ;
     RECT  173.016 106.785 213.84 107.055 ;
     RECT  2.16 107.325 37.8 107.595 ;
     RECT  86.616 107.325 124.2 107.595 ;
     RECT  173.016 107.325 213.84 107.595 ;
     RECT  2.16 107.865 37.8 108.135 ;
     RECT  86.616 107.865 124.2 108.135 ;
     RECT  173.016 107.865 213.84 108.135 ;
     RECT  2.16 108.405 37.8 108.675 ;
     RECT  86.616 108.405 124.2 108.675 ;
     RECT  173.016 108.405 213.84 108.675 ;
     RECT  2.16 108.945 37.8 109.215 ;
     RECT  86.616 108.945 124.2 109.215 ;
     RECT  173.016 108.945 213.84 109.215 ;
     RECT  2.16 109.485 37.8 109.755 ;
     RECT  86.616 109.485 124.2 109.755 ;
     RECT  173.016 109.485 213.84 109.755 ;
     RECT  2.16 110.025 37.8 110.295 ;
     RECT  86.616 110.025 124.2 110.295 ;
     RECT  173.016 110.025 213.84 110.295 ;
     RECT  2.16 110.565 37.8 110.835 ;
     RECT  86.616 110.565 124.2 110.835 ;
     RECT  173.016 110.565 213.84 110.835 ;
     RECT  2.16 111.105 37.8 111.375 ;
     RECT  86.616 111.105 124.2 111.375 ;
     RECT  173.016 111.105 213.84 111.375 ;
     RECT  2.16 111.645 213.84 111.915 ;
     RECT  2.16 112.185 213.84 112.455 ;
     RECT  2.16 112.725 213.84 112.995 ;
     RECT  2.16 113.265 213.84 113.535 ;
     RECT  2.16 113.805 213.84 114.075 ;
     RECT  2.16 114.345 213.84 114.615 ;
     RECT  2.16 114.885 213.84 115.155 ;
     RECT  2.16 115.425 213.84 115.695 ;
     RECT  2.16 115.965 213.84 116.235 ;
     RECT  2.16 116.505 213.84 116.775 ;
     RECT  2.16 117.045 213.84 117.315 ;
     RECT  2.16 117.585 213.84 117.855 ;
     RECT  2.16 118.125 213.84 118.395 ;
     RECT  2.16 118.665 213.84 118.935 ;
     RECT  2.16 119.205 213.84 119.475 ;
     RECT  2.16 119.745 213.84 120.015 ;
     RECT  2.16 120.285 213.84 120.555 ;
     RECT  2.16 120.825 213.84 121.095 ;
     RECT  2.16 121.365 213.84 121.635 ;
     RECT  2.16 121.905 213.84 122.175 ;
     RECT  2.16 122.445 213.84 122.715 ;
     RECT  2.16 122.985 213.84 123.255 ;
     RECT  2.16 123.525 213.84 123.795 ;
     RECT  2.16 124.065 213.84 124.335 ;
     RECT  2.16 124.605 213.84 124.875 ;
     RECT  2.16 125.145 213.84 125.415 ;
     RECT  2.16 125.685 213.84 125.955 ;
     RECT  2.16 126.225 213.84 126.495 ;
     RECT  2.16 126.765 213.84 127.035 ;
     RECT  2.16 127.305 213.84 127.44 ;
    LAYER RVTP ;
     RECT  2.16 2.295 213.84 2.565 ;
     RECT  2.16 2.835 213.84 3.105 ;
     RECT  2.16 3.375 213.84 3.645 ;
     RECT  2.16 3.915 213.84 4.185 ;
     RECT  2.16 4.455 213.84 4.725 ;
     RECT  2.16 4.995 213.84 5.265 ;
     RECT  2.16 5.535 213.84 5.805 ;
     RECT  2.16 6.075 213.84 6.345 ;
     RECT  2.16 6.615 213.84 6.885 ;
     RECT  2.16 7.155 213.84 7.425 ;
     RECT  2.16 7.695 213.84 7.965 ;
     RECT  2.16 8.235 213.84 8.505 ;
     RECT  2.16 8.775 213.84 9.045 ;
     RECT  2.16 9.315 213.84 9.585 ;
     RECT  2.16 9.855 213.84 10.125 ;
     RECT  2.16 10.395 213.84 10.665 ;
     RECT  2.16 10.935 213.84 11.205 ;
     RECT  2.16 11.475 213.84 11.745 ;
     RECT  2.16 12.015 213.84 12.285 ;
     RECT  2.16 12.555 213.84 12.825 ;
     RECT  2.16 13.095 213.84 13.365 ;
     RECT  2.16 13.635 213.84 13.905 ;
     RECT  2.16 14.175 213.84 14.445 ;
     RECT  2.16 14.715 213.84 14.985 ;
     RECT  2.16 15.255 213.84 15.525 ;
     RECT  2.16 15.795 213.84 16.065 ;
     RECT  2.16 16.335 213.84 16.605 ;
     RECT  2.16 16.875 213.84 17.145 ;
     RECT  2.16 17.415 213.84 17.685 ;
     RECT  2.16 17.955 213.84 18.225 ;
     RECT  2.16 18.495 213.84 18.765 ;
     RECT  2.16 19.035 213.84 19.305 ;
     RECT  2.16 19.575 213.84 19.845 ;
     RECT  2.16 20.115 213.84 20.385 ;
     RECT  2.16 20.655 213.84 20.925 ;
     RECT  2.16 21.195 213.84 21.465 ;
     RECT  2.16 21.735 213.84 22.005 ;
     RECT  2.16 22.275 213.84 22.545 ;
     RECT  2.16 22.815 213.84 23.085 ;
     RECT  2.16 23.355 213.84 23.625 ;
     RECT  2.16 23.895 213.84 24.165 ;
     RECT  2.16 24.435 213.84 24.705 ;
     RECT  2.16 24.975 213.84 25.245 ;
     RECT  2.16 25.515 213.84 25.785 ;
     RECT  2.16 26.055 213.84 26.325 ;
     RECT  2.16 26.595 213.84 26.865 ;
     RECT  2.16 27.135 213.84 27.405 ;
     RECT  2.16 27.675 213.84 27.945 ;
     RECT  2.16 28.215 213.84 28.485 ;
     RECT  2.16 28.755 213.84 29.025 ;
     RECT  2.16 29.295 213.84 29.565 ;
     RECT  2.16 29.835 213.84 30.105 ;
     RECT  2.16 30.375 213.84 30.645 ;
     RECT  2.16 30.915 213.84 31.185 ;
     RECT  2.16 31.455 213.84 31.725 ;
     RECT  2.16 31.995 213.84 32.265 ;
     RECT  2.16 32.535 213.84 32.805 ;
     RECT  2.16 33.075 213.84 33.345 ;
     RECT  2.16 33.615 213.84 33.885 ;
     RECT  2.16 34.155 213.84 34.425 ;
     RECT  2.16 34.695 213.84 34.965 ;
     RECT  2.16 35.235 213.84 35.505 ;
     RECT  2.16 35.775 213.84 36.045 ;
     RECT  2.16 36.315 213.84 36.585 ;
     RECT  2.16 36.855 213.84 37.125 ;
     RECT  2.16 37.395 213.84 37.665 ;
     RECT  2.16 37.935 37.8 38.205 ;
     RECT  86.616 37.935 124.2 38.205 ;
     RECT  173.016 37.935 213.84 38.205 ;
     RECT  2.16 38.475 37.8 38.745 ;
     RECT  86.616 38.475 124.2 38.745 ;
     RECT  173.016 38.475 213.84 38.745 ;
     RECT  2.16 39.015 37.8 39.285 ;
     RECT  86.616 39.015 124.2 39.285 ;
     RECT  173.016 39.015 213.84 39.285 ;
     RECT  2.16 39.555 37.8 39.825 ;
     RECT  86.616 39.555 124.2 39.825 ;
     RECT  173.016 39.555 213.84 39.825 ;
     RECT  2.16 40.095 37.8 40.365 ;
     RECT  86.616 40.095 124.2 40.365 ;
     RECT  173.016 40.095 213.84 40.365 ;
     RECT  2.16 40.635 37.8 40.905 ;
     RECT  86.616 40.635 124.2 40.905 ;
     RECT  173.016 40.635 213.84 40.905 ;
     RECT  2.16 41.175 37.8 41.445 ;
     RECT  86.616 41.175 124.2 41.445 ;
     RECT  173.016 41.175 213.84 41.445 ;
     RECT  2.16 41.715 37.8 41.985 ;
     RECT  86.616 41.715 124.2 41.985 ;
     RECT  173.016 41.715 213.84 41.985 ;
     RECT  2.16 42.255 37.8 42.525 ;
     RECT  86.616 42.255 124.2 42.525 ;
     RECT  173.016 42.255 213.84 42.525 ;
     RECT  2.16 42.795 37.8 43.065 ;
     RECT  86.616 42.795 124.2 43.065 ;
     RECT  173.016 42.795 213.84 43.065 ;
     RECT  2.16 43.335 37.8 43.605 ;
     RECT  86.616 43.335 124.2 43.605 ;
     RECT  173.016 43.335 213.84 43.605 ;
     RECT  2.16 43.875 37.8 44.145 ;
     RECT  86.616 43.875 124.2 44.145 ;
     RECT  173.016 43.875 213.84 44.145 ;
     RECT  2.16 44.415 37.8 44.685 ;
     RECT  86.616 44.415 124.2 44.685 ;
     RECT  173.016 44.415 213.84 44.685 ;
     RECT  2.16 44.955 37.8 45.225 ;
     RECT  86.616 44.955 124.2 45.225 ;
     RECT  173.016 44.955 213.84 45.225 ;
     RECT  2.16 45.495 37.8 45.765 ;
     RECT  86.616 45.495 124.2 45.765 ;
     RECT  173.016 45.495 213.84 45.765 ;
     RECT  2.16 46.035 37.8 46.305 ;
     RECT  86.616 46.035 124.2 46.305 ;
     RECT  173.016 46.035 213.84 46.305 ;
     RECT  2.16 46.575 37.8 46.845 ;
     RECT  86.616 46.575 124.2 46.845 ;
     RECT  173.016 46.575 213.84 46.845 ;
     RECT  2.16 47.115 37.8 47.385 ;
     RECT  86.616 47.115 124.2 47.385 ;
     RECT  173.016 47.115 213.84 47.385 ;
     RECT  2.16 47.655 37.8 47.925 ;
     RECT  86.616 47.655 124.2 47.925 ;
     RECT  173.016 47.655 213.84 47.925 ;
     RECT  2.16 48.195 37.8 48.465 ;
     RECT  86.616 48.195 124.2 48.465 ;
     RECT  173.016 48.195 213.84 48.465 ;
     RECT  2.16 48.735 37.8 49.005 ;
     RECT  86.616 48.735 124.2 49.005 ;
     RECT  173.016 48.735 213.84 49.005 ;
     RECT  2.16 49.275 37.8 49.545 ;
     RECT  86.616 49.275 124.2 49.545 ;
     RECT  173.016 49.275 213.84 49.545 ;
     RECT  2.16 49.815 37.8 50.085 ;
     RECT  86.616 49.815 124.2 50.085 ;
     RECT  173.016 49.815 213.84 50.085 ;
     RECT  2.16 50.355 37.8 50.625 ;
     RECT  86.616 50.355 124.2 50.625 ;
     RECT  173.016 50.355 213.84 50.625 ;
     RECT  2.16 50.895 37.8 51.165 ;
     RECT  86.616 50.895 124.2 51.165 ;
     RECT  173.016 50.895 213.84 51.165 ;
     RECT  2.16 51.435 37.8 51.705 ;
     RECT  86.616 51.435 124.2 51.705 ;
     RECT  173.016 51.435 213.84 51.705 ;
     RECT  2.16 51.975 37.8 52.245 ;
     RECT  86.616 51.975 124.2 52.245 ;
     RECT  173.016 51.975 213.84 52.245 ;
     RECT  2.16 52.515 37.8 52.785 ;
     RECT  86.616 52.515 124.2 52.785 ;
     RECT  173.016 52.515 213.84 52.785 ;
     RECT  2.16 53.055 37.8 53.325 ;
     RECT  86.616 53.055 124.2 53.325 ;
     RECT  173.016 53.055 213.84 53.325 ;
     RECT  2.16 53.595 37.8 53.865 ;
     RECT  86.616 53.595 124.2 53.865 ;
     RECT  173.016 53.595 213.84 53.865 ;
     RECT  2.16 54.135 37.8 54.405 ;
     RECT  86.616 54.135 124.2 54.405 ;
     RECT  173.016 54.135 213.84 54.405 ;
     RECT  2.16 54.675 37.8 54.945 ;
     RECT  86.616 54.675 124.2 54.945 ;
     RECT  173.016 54.675 213.84 54.945 ;
     RECT  2.16 55.215 37.8 55.485 ;
     RECT  86.616 55.215 124.2 55.485 ;
     RECT  173.016 55.215 213.84 55.485 ;
     RECT  2.16 55.755 37.8 56.025 ;
     RECT  86.616 55.755 124.2 56.025 ;
     RECT  173.016 55.755 213.84 56.025 ;
     RECT  2.16 56.295 37.8 56.565 ;
     RECT  86.616 56.295 124.2 56.565 ;
     RECT  173.016 56.295 213.84 56.565 ;
     RECT  2.16 56.835 37.8 57.105 ;
     RECT  86.616 56.835 124.2 57.105 ;
     RECT  173.016 56.835 213.84 57.105 ;
     RECT  2.16 57.375 37.8 57.645 ;
     RECT  86.616 57.375 124.2 57.645 ;
     RECT  173.016 57.375 213.84 57.645 ;
     RECT  2.16 57.915 37.8 58.185 ;
     RECT  86.616 57.915 124.2 58.185 ;
     RECT  173.016 57.915 213.84 58.185 ;
     RECT  2.16 58.455 37.8 58.725 ;
     RECT  86.616 58.455 124.2 58.725 ;
     RECT  173.016 58.455 213.84 58.725 ;
     RECT  2.16 58.995 37.8 59.265 ;
     RECT  86.616 58.995 124.2 59.265 ;
     RECT  173.016 58.995 213.84 59.265 ;
     RECT  2.16 59.535 37.8 59.805 ;
     RECT  86.616 59.535 124.2 59.805 ;
     RECT  173.016 59.535 213.84 59.805 ;
     RECT  2.16 60.075 37.8 60.345 ;
     RECT  86.616 60.075 124.2 60.345 ;
     RECT  173.016 60.075 213.84 60.345 ;
     RECT  2.16 60.615 37.8 60.885 ;
     RECT  86.616 60.615 124.2 60.885 ;
     RECT  173.016 60.615 213.84 60.885 ;
     RECT  2.16 61.155 37.8 61.425 ;
     RECT  86.616 61.155 124.2 61.425 ;
     RECT  173.016 61.155 213.84 61.425 ;
     RECT  2.16 61.695 37.8 61.965 ;
     RECT  86.616 61.695 124.2 61.965 ;
     RECT  173.016 61.695 213.84 61.965 ;
     RECT  2.16 62.235 37.8 62.505 ;
     RECT  86.616 62.235 124.2 62.505 ;
     RECT  173.016 62.235 213.84 62.505 ;
     RECT  2.16 62.775 37.8 63.045 ;
     RECT  86.616 62.775 124.2 63.045 ;
     RECT  173.016 62.775 213.84 63.045 ;
     RECT  2.16 63.315 37.8 63.585 ;
     RECT  86.616 63.315 124.2 63.585 ;
     RECT  173.016 63.315 213.84 63.585 ;
     RECT  2.16 63.855 37.8 64.125 ;
     RECT  86.616 63.855 124.2 64.125 ;
     RECT  173.016 63.855 213.84 64.125 ;
     RECT  2.16 64.395 37.8 64.665 ;
     RECT  86.616 64.395 124.2 64.665 ;
     RECT  173.016 64.395 213.84 64.665 ;
     RECT  2.16 64.935 37.8 65.205 ;
     RECT  86.616 64.935 124.2 65.205 ;
     RECT  173.016 64.935 213.84 65.205 ;
     RECT  2.16 65.475 37.8 65.745 ;
     RECT  86.616 65.475 124.2 65.745 ;
     RECT  173.016 65.475 213.84 65.745 ;
     RECT  2.16 66.015 37.8 66.285 ;
     RECT  86.616 66.015 124.2 66.285 ;
     RECT  173.016 66.015 213.84 66.285 ;
     RECT  2.16 66.555 37.8 66.825 ;
     RECT  86.616 66.555 124.2 66.825 ;
     RECT  173.016 66.555 213.84 66.825 ;
     RECT  2.16 67.095 37.8 67.365 ;
     RECT  86.616 67.095 124.2 67.365 ;
     RECT  173.016 67.095 213.84 67.365 ;
     RECT  2.16 67.635 37.8 67.905 ;
     RECT  86.616 67.635 124.2 67.905 ;
     RECT  173.016 67.635 213.84 67.905 ;
     RECT  2.16 68.175 37.8 68.445 ;
     RECT  86.616 68.175 124.2 68.445 ;
     RECT  173.016 68.175 213.84 68.445 ;
     RECT  2.16 68.715 37.8 68.985 ;
     RECT  86.616 68.715 124.2 68.985 ;
     RECT  173.016 68.715 213.84 68.985 ;
     RECT  2.16 69.255 37.8 69.525 ;
     RECT  86.616 69.255 124.2 69.525 ;
     RECT  173.016 69.255 213.84 69.525 ;
     RECT  2.16 69.795 37.8 70.065 ;
     RECT  86.616 69.795 124.2 70.065 ;
     RECT  173.016 69.795 213.84 70.065 ;
     RECT  2.16 70.335 37.8 70.605 ;
     RECT  86.616 70.335 124.2 70.605 ;
     RECT  173.016 70.335 213.84 70.605 ;
     RECT  2.16 70.875 37.8 71.145 ;
     RECT  86.616 70.875 124.2 71.145 ;
     RECT  173.016 70.875 213.84 71.145 ;
     RECT  2.16 71.415 37.8 71.685 ;
     RECT  86.616 71.415 124.2 71.685 ;
     RECT  173.016 71.415 213.84 71.685 ;
     RECT  2.16 71.955 37.8 72.225 ;
     RECT  86.616 71.955 124.2 72.225 ;
     RECT  173.016 71.955 213.84 72.225 ;
     RECT  2.16 72.495 37.8 72.765 ;
     RECT  86.616 72.495 124.2 72.765 ;
     RECT  173.016 72.495 213.84 72.765 ;
     RECT  2.16 73.035 37.8 73.305 ;
     RECT  86.616 73.035 124.2 73.305 ;
     RECT  173.016 73.035 213.84 73.305 ;
     RECT  2.16 73.575 37.8 73.845 ;
     RECT  86.616 73.575 124.2 73.845 ;
     RECT  173.016 73.575 213.84 73.845 ;
     RECT  2.16 74.115 37.8 74.385 ;
     RECT  86.616 74.115 124.2 74.385 ;
     RECT  173.016 74.115 213.84 74.385 ;
     RECT  2.16 74.655 37.8 74.925 ;
     RECT  86.616 74.655 124.2 74.925 ;
     RECT  173.016 74.655 213.84 74.925 ;
     RECT  2.16 75.195 37.8 75.465 ;
     RECT  86.616 75.195 124.2 75.465 ;
     RECT  173.016 75.195 213.84 75.465 ;
     RECT  2.16 75.735 37.8 76.005 ;
     RECT  86.616 75.735 124.2 76.005 ;
     RECT  173.016 75.735 213.84 76.005 ;
     RECT  2.16 76.275 37.8 76.545 ;
     RECT  86.616 76.275 124.2 76.545 ;
     RECT  173.016 76.275 213.84 76.545 ;
     RECT  2.16 76.815 37.8 77.085 ;
     RECT  86.616 76.815 124.2 77.085 ;
     RECT  173.016 76.815 213.84 77.085 ;
     RECT  2.16 77.355 37.8 77.625 ;
     RECT  86.616 77.355 124.2 77.625 ;
     RECT  173.016 77.355 213.84 77.625 ;
     RECT  2.16 77.895 37.8 78.165 ;
     RECT  86.616 77.895 124.2 78.165 ;
     RECT  173.016 77.895 213.84 78.165 ;
     RECT  2.16 78.435 37.8 78.705 ;
     RECT  86.616 78.435 124.2 78.705 ;
     RECT  173.016 78.435 213.84 78.705 ;
     RECT  2.16 78.975 37.8 79.245 ;
     RECT  86.616 78.975 124.2 79.245 ;
     RECT  173.016 78.975 213.84 79.245 ;
     RECT  2.16 79.515 37.8 79.785 ;
     RECT  86.616 79.515 124.2 79.785 ;
     RECT  173.016 79.515 213.84 79.785 ;
     RECT  2.16 80.055 37.8 80.325 ;
     RECT  86.616 80.055 124.2 80.325 ;
     RECT  173.016 80.055 213.84 80.325 ;
     RECT  2.16 80.595 37.8 80.865 ;
     RECT  86.616 80.595 124.2 80.865 ;
     RECT  173.016 80.595 213.84 80.865 ;
     RECT  2.16 81.135 37.8 81.405 ;
     RECT  86.616 81.135 124.2 81.405 ;
     RECT  173.016 81.135 213.84 81.405 ;
     RECT  2.16 81.675 37.8 81.945 ;
     RECT  86.616 81.675 124.2 81.945 ;
     RECT  173.016 81.675 213.84 81.945 ;
     RECT  2.16 82.215 37.8 82.485 ;
     RECT  86.616 82.215 124.2 82.485 ;
     RECT  173.016 82.215 213.84 82.485 ;
     RECT  2.16 82.755 37.8 83.025 ;
     RECT  86.616 82.755 124.2 83.025 ;
     RECT  173.016 82.755 213.84 83.025 ;
     RECT  2.16 83.295 37.8 83.565 ;
     RECT  86.616 83.295 124.2 83.565 ;
     RECT  173.016 83.295 213.84 83.565 ;
     RECT  2.16 83.835 37.8 84.105 ;
     RECT  86.616 83.835 124.2 84.105 ;
     RECT  173.016 83.835 213.84 84.105 ;
     RECT  2.16 84.375 37.8 84.645 ;
     RECT  86.616 84.375 124.2 84.645 ;
     RECT  173.016 84.375 213.84 84.645 ;
     RECT  2.16 84.915 37.8 85.185 ;
     RECT  86.616 84.915 124.2 85.185 ;
     RECT  173.016 84.915 213.84 85.185 ;
     RECT  2.16 85.455 37.8 85.725 ;
     RECT  86.616 85.455 124.2 85.725 ;
     RECT  173.016 85.455 213.84 85.725 ;
     RECT  2.16 85.995 37.8 86.265 ;
     RECT  86.616 85.995 124.2 86.265 ;
     RECT  173.016 85.995 213.84 86.265 ;
     RECT  2.16 86.535 37.8 86.805 ;
     RECT  86.616 86.535 124.2 86.805 ;
     RECT  173.016 86.535 213.84 86.805 ;
     RECT  2.16 87.075 37.8 87.345 ;
     RECT  86.616 87.075 124.2 87.345 ;
     RECT  173.016 87.075 213.84 87.345 ;
     RECT  2.16 87.615 37.8 87.885 ;
     RECT  86.616 87.615 124.2 87.885 ;
     RECT  173.016 87.615 213.84 87.885 ;
     RECT  2.16 88.155 37.8 88.425 ;
     RECT  86.616 88.155 124.2 88.425 ;
     RECT  173.016 88.155 213.84 88.425 ;
     RECT  2.16 88.695 37.8 88.965 ;
     RECT  86.616 88.695 124.2 88.965 ;
     RECT  173.016 88.695 213.84 88.965 ;
     RECT  2.16 89.235 37.8 89.505 ;
     RECT  86.616 89.235 124.2 89.505 ;
     RECT  173.016 89.235 213.84 89.505 ;
     RECT  2.16 89.775 37.8 90.045 ;
     RECT  86.616 89.775 124.2 90.045 ;
     RECT  173.016 89.775 213.84 90.045 ;
     RECT  2.16 90.315 37.8 90.585 ;
     RECT  86.616 90.315 124.2 90.585 ;
     RECT  173.016 90.315 213.84 90.585 ;
     RECT  2.16 90.855 37.8 91.125 ;
     RECT  86.616 90.855 124.2 91.125 ;
     RECT  173.016 90.855 213.84 91.125 ;
     RECT  2.16 91.395 37.8 91.665 ;
     RECT  86.616 91.395 124.2 91.665 ;
     RECT  173.016 91.395 213.84 91.665 ;
     RECT  2.16 91.935 37.8 92.205 ;
     RECT  86.616 91.935 124.2 92.205 ;
     RECT  173.016 91.935 213.84 92.205 ;
     RECT  2.16 92.475 37.8 92.745 ;
     RECT  86.616 92.475 124.2 92.745 ;
     RECT  173.016 92.475 213.84 92.745 ;
     RECT  2.16 93.015 37.8 93.285 ;
     RECT  86.616 93.015 124.2 93.285 ;
     RECT  173.016 93.015 213.84 93.285 ;
     RECT  2.16 93.555 37.8 93.825 ;
     RECT  86.616 93.555 124.2 93.825 ;
     RECT  173.016 93.555 213.84 93.825 ;
     RECT  2.16 94.095 37.8 94.365 ;
     RECT  86.616 94.095 124.2 94.365 ;
     RECT  173.016 94.095 213.84 94.365 ;
     RECT  2.16 94.635 37.8 94.905 ;
     RECT  86.616 94.635 124.2 94.905 ;
     RECT  173.016 94.635 213.84 94.905 ;
     RECT  2.16 95.175 37.8 95.445 ;
     RECT  86.616 95.175 124.2 95.445 ;
     RECT  173.016 95.175 213.84 95.445 ;
     RECT  2.16 95.715 37.8 95.985 ;
     RECT  86.616 95.715 124.2 95.985 ;
     RECT  173.016 95.715 213.84 95.985 ;
     RECT  2.16 96.255 37.8 96.525 ;
     RECT  86.616 96.255 124.2 96.525 ;
     RECT  173.016 96.255 213.84 96.525 ;
     RECT  2.16 96.795 37.8 97.065 ;
     RECT  86.616 96.795 124.2 97.065 ;
     RECT  173.016 96.795 213.84 97.065 ;
     RECT  2.16 97.335 37.8 97.605 ;
     RECT  86.616 97.335 124.2 97.605 ;
     RECT  173.016 97.335 213.84 97.605 ;
     RECT  2.16 97.875 37.8 98.145 ;
     RECT  86.616 97.875 124.2 98.145 ;
     RECT  173.016 97.875 213.84 98.145 ;
     RECT  2.16 98.415 37.8 98.685 ;
     RECT  86.616 98.415 124.2 98.685 ;
     RECT  173.016 98.415 213.84 98.685 ;
     RECT  2.16 98.955 37.8 99.225 ;
     RECT  86.616 98.955 124.2 99.225 ;
     RECT  173.016 98.955 213.84 99.225 ;
     RECT  2.16 99.495 37.8 99.765 ;
     RECT  86.616 99.495 124.2 99.765 ;
     RECT  173.016 99.495 213.84 99.765 ;
     RECT  2.16 100.035 37.8 100.305 ;
     RECT  86.616 100.035 124.2 100.305 ;
     RECT  173.016 100.035 213.84 100.305 ;
     RECT  2.16 100.575 37.8 100.845 ;
     RECT  86.616 100.575 124.2 100.845 ;
     RECT  173.016 100.575 213.84 100.845 ;
     RECT  2.16 101.115 37.8 101.385 ;
     RECT  86.616 101.115 124.2 101.385 ;
     RECT  173.016 101.115 213.84 101.385 ;
     RECT  2.16 101.655 37.8 101.925 ;
     RECT  86.616 101.655 124.2 101.925 ;
     RECT  173.016 101.655 213.84 101.925 ;
     RECT  2.16 102.195 37.8 102.465 ;
     RECT  86.616 102.195 124.2 102.465 ;
     RECT  173.016 102.195 213.84 102.465 ;
     RECT  2.16 102.735 37.8 103.005 ;
     RECT  86.616 102.735 124.2 103.005 ;
     RECT  173.016 102.735 213.84 103.005 ;
     RECT  2.16 103.275 37.8 103.545 ;
     RECT  86.616 103.275 124.2 103.545 ;
     RECT  173.016 103.275 213.84 103.545 ;
     RECT  2.16 103.815 37.8 104.085 ;
     RECT  86.616 103.815 124.2 104.085 ;
     RECT  173.016 103.815 213.84 104.085 ;
     RECT  2.16 104.355 37.8 104.625 ;
     RECT  86.616 104.355 124.2 104.625 ;
     RECT  173.016 104.355 213.84 104.625 ;
     RECT  2.16 104.895 37.8 105.165 ;
     RECT  86.616 104.895 124.2 105.165 ;
     RECT  173.016 104.895 213.84 105.165 ;
     RECT  2.16 105.435 37.8 105.705 ;
     RECT  86.616 105.435 124.2 105.705 ;
     RECT  173.016 105.435 213.84 105.705 ;
     RECT  2.16 105.975 37.8 106.245 ;
     RECT  86.616 105.975 124.2 106.245 ;
     RECT  173.016 105.975 213.84 106.245 ;
     RECT  2.16 106.515 37.8 106.785 ;
     RECT  86.616 106.515 124.2 106.785 ;
     RECT  173.016 106.515 213.84 106.785 ;
     RECT  2.16 107.055 37.8 107.325 ;
     RECT  86.616 107.055 124.2 107.325 ;
     RECT  173.016 107.055 213.84 107.325 ;
     RECT  2.16 107.595 37.8 107.865 ;
     RECT  86.616 107.595 124.2 107.865 ;
     RECT  173.016 107.595 213.84 107.865 ;
     RECT  2.16 108.135 37.8 108.405 ;
     RECT  86.616 108.135 124.2 108.405 ;
     RECT  173.016 108.135 213.84 108.405 ;
     RECT  2.16 108.675 37.8 108.945 ;
     RECT  86.616 108.675 124.2 108.945 ;
     RECT  173.016 108.675 213.84 108.945 ;
     RECT  2.16 109.215 37.8 109.485 ;
     RECT  86.616 109.215 124.2 109.485 ;
     RECT  173.016 109.215 213.84 109.485 ;
     RECT  2.16 109.755 37.8 110.025 ;
     RECT  86.616 109.755 124.2 110.025 ;
     RECT  173.016 109.755 213.84 110.025 ;
     RECT  2.16 110.295 37.8 110.565 ;
     RECT  86.616 110.295 124.2 110.565 ;
     RECT  173.016 110.295 213.84 110.565 ;
     RECT  2.16 110.835 37.8 111.105 ;
     RECT  86.616 110.835 124.2 111.105 ;
     RECT  173.016 110.835 213.84 111.105 ;
     RECT  2.16 111.375 37.8 111.51 ;
     RECT  86.616 111.375 124.2 111.51 ;
     RECT  173.016 111.375 213.84 111.51 ;
     RECT  2.16 111.51 213.84 111.645 ;
     RECT  2.16 111.915 213.84 112.185 ;
     RECT  2.16 112.455 213.84 112.725 ;
     RECT  2.16 112.995 213.84 113.265 ;
     RECT  2.16 113.535 213.84 113.805 ;
     RECT  2.16 114.075 213.84 114.345 ;
     RECT  2.16 114.615 213.84 114.885 ;
     RECT  2.16 115.155 213.84 115.425 ;
     RECT  2.16 115.695 213.84 115.965 ;
     RECT  2.16 116.235 213.84 116.505 ;
     RECT  2.16 116.775 213.84 117.045 ;
     RECT  2.16 117.315 213.84 117.585 ;
     RECT  2.16 117.855 213.84 118.125 ;
     RECT  2.16 118.395 213.84 118.665 ;
     RECT  2.16 118.935 213.84 119.205 ;
     RECT  2.16 119.475 213.84 119.745 ;
     RECT  2.16 120.015 213.84 120.285 ;
     RECT  2.16 120.555 213.84 120.825 ;
     RECT  2.16 121.095 213.84 121.365 ;
     RECT  2.16 121.635 213.84 121.905 ;
     RECT  2.16 122.175 213.84 122.445 ;
     RECT  2.16 122.715 213.84 122.985 ;
     RECT  2.16 123.255 213.84 123.525 ;
     RECT  2.16 123.795 213.84 124.065 ;
     RECT  2.16 124.335 213.84 124.605 ;
     RECT  2.16 124.875 213.84 125.145 ;
     RECT  2.16 125.415 213.84 125.685 ;
     RECT  2.16 125.955 213.84 126.225 ;
     RECT  2.16 126.495 213.84 126.765 ;
     RECT  2.16 127.035 213.84 127.305 ;
    LAYER M1 ;
     RECT  2.16 2.151 213.84 37.809 ;
     RECT  43.2 43.2 81.216 106.11 ;
     RECT  129.6 43.2 167.616 106.11 ;
     RECT  2.16 37.809 37.8 111.501 ;
     RECT  86.616 37.809 124.2 111.501 ;
     RECT  173.016 37.809 213.84 111.501 ;
     RECT  2.16 111.501 213.84 127.449 ;
    LAYER M2 ;
     RECT  0.211 5.166 2.16 5.184 ;
     RECT  0.211 8.244 2.16 8.262 ;
     RECT  0.211 10.674 2.16 10.692 ;
     RECT  1.723 12.996 2.16 13.014 ;
     RECT  0.211 15.426 2.16 15.444 ;
     RECT  0.211 20.556 2.16 20.574 ;
     RECT  0.211 25.686 2.16 25.704 ;
     RECT  0.535 28.116 2.16 28.134 ;
     RECT  1.723 30.726 2.16 30.744 ;
     RECT  0.211 33.516 2.16 33.534 ;
     RECT  0.535 35.676 2.16 35.694 ;
     RECT  0.211 38.718 2.16 38.736 ;
     RECT  0.535 40.986 2.16 41.004 ;
     RECT  0.211 50.796 2.16 50.814 ;
     RECT  0.211 53.496 2.16 53.514 ;
     RECT  0.211 56.034 2.16 56.052 ;
     RECT  1.723 58.086 2.16 58.104 ;
     RECT  1.723 60.516 2.16 60.534 ;
     RECT  0.211 63.666 2.16 63.684 ;
     RECT  0.211 66.096 2.16 66.114 ;
     RECT  0.211 68.616 2.16 68.634 ;
     RECT  0.211 71.154 2.16 71.172 ;
     RECT  0.211 78.876 2.16 78.894 ;
     RECT  1.723 80.766 2.16 80.784 ;
     RECT  1.723 85.896 2.16 85.914 ;
     RECT  0.535 91.476 2.16 91.494 ;
     RECT  0.211 93.906 2.16 93.924 ;
     RECT  1.723 96.156 2.16 96.174 ;
     RECT  0.211 99.036 2.16 99.054 ;
     RECT  0.211 101.358 2.16 101.376 ;
     RECT  1.723 111.006 2.16 111.024 ;
     RECT  0.211 116.514 2.16 116.532 ;
     RECT  0.211 118.836 2.16 118.854 ;
     RECT  0.211 121.536 2.16 121.554 ;
     RECT  2.16 2.151 37.812 127.449 ;
     RECT  37.812 39.636 39.587 48.294 ;
     RECT  37.812 66.258 41.315 66.276 ;
     RECT  37.812 59.166 41.891 59.184 ;
     RECT  37.812 76.248 41.891 76.266 ;
     RECT  37.812 106.686 41.899 107.01 ;
     RECT  37.812 81.414 41.927 81.666 ;
     RECT  41.927 81.648 41.963 81.666 ;
     RECT  41.899 106.29 41.971 107.01 ;
     RECT  37.812 88.632 41.999 89.226 ;
     RECT  37.812 91.368 42.071 91.386 ;
     RECT  39.587 44.226 42.179 48.294 ;
     RECT  39.587 39.636 42.215 43.326 ;
     RECT  37.812 2.151 42.295 38.844 ;
     RECT  42.215 39.636 42.295 43.164 ;
     RECT  41.999 88.632 42.467 88.65 ;
     RECT  42.295 2.151 43.2 43.164 ;
     RECT  42.179 44.226 43.2 47.952 ;
     RECT  37.812 49.86 43.2 49.878 ;
     RECT  37.812 51.408 43.2 51.426 ;
     RECT  37.812 52.56 43.2 52.578 ;
     RECT  41.971 106.218 43.2 107.01 ;
     RECT  43.2 2.151 81.216 107.01 ;
     RECT  81.216 43.956 81.347 44.748 ;
     RECT  81.216 2.151 86.616 43.164 ;
     RECT  81.347 44.19 86.616 44.748 ;
     RECT  81.216 106.218 86.616 107.01 ;
     RECT  37.812 108.036 86.616 108.054 ;
     RECT  37.812 111.384 86.616 127.449 ;
     RECT  86.616 2.151 124.212 127.449 ;
     RECT  124.212 41.796 124.259 48.654 ;
     RECT  124.259 41.796 125.951 43.866 ;
     RECT  124.259 44.73 126.563 48.654 ;
     RECT  126.563 44.73 128.291 47.61 ;
     RECT  124.212 87.822 128.543 87.84 ;
     RECT  124.212 89.172 128.579 89.19 ;
     RECT  124.212 92.952 128.615 92.97 ;
     RECT  125.951 41.796 128.867 43.794 ;
     RECT  128.867 41.796 129.6 43.596 ;
     RECT  128.291 44.73 129.6 47.574 ;
     RECT  126.563 48.366 129.6 48.654 ;
     RECT  124.212 106.146 129.6 106.884 ;
     RECT  129.6 41.796 138.875 106.884 ;
     RECT  124.212 108.036 139.739 108.054 ;
     RECT  124.212 111.384 141.071 127.449 ;
     RECT  138.875 41.796 167.616 106.776 ;
     RECT  141.071 111.42 167.855 127.449 ;
     RECT  167.616 41.796 169.843 43.164 ;
     RECT  169.843 41.796 169.879 43.632 ;
     RECT  124.212 2.151 173.016 39.114 ;
     RECT  169.879 41.796 173.016 44.334 ;
     RECT  167.616 45.846 173.016 45.864 ;
     RECT  167.616 46.89 173.016 46.908 ;
     RECT  167.616 49.896 173.016 49.914 ;
     RECT  167.616 99.972 173.016 99.99 ;
     RECT  167.616 106.146 173.016 106.776 ;
     RECT  167.855 111.456 173.016 127.449 ;
     RECT  173.016 2.151 213.84 127.449 ;
     RECT  213.84 33.318 214.259 33.336 ;
     RECT  213.84 63.558 214.259 63.576 ;
     RECT  213.84 110.268 214.259 110.286 ;
     RECT  213.84 24.948 214.331 24.966 ;
     RECT  213.84 47.088 214.331 47.106 ;
     RECT  213.84 55.188 214.331 55.206 ;
     RECT  213.84 77.328 214.331 77.346 ;
     RECT  213.84 6.246 214.367 6.264 ;
     RECT  213.84 8.316 214.367 8.334 ;
     RECT  213.84 11.016 214.367 11.034 ;
     RECT  213.84 16.848 214.367 16.866 ;
     RECT  213.84 19.548 214.367 19.566 ;
     RECT  213.84 22.086 214.367 22.104 ;
     RECT  213.84 27.684 214.367 27.702 ;
     RECT  213.84 30.618 214.367 30.636 ;
     RECT  213.84 38.718 214.367 38.736 ;
     RECT  213.84 49.788 214.367 49.806 ;
     RECT  213.84 57.924 214.367 57.942 ;
     RECT  213.84 60.93 214.367 60.948 ;
     RECT  213.84 71.73 214.367 71.748 ;
     RECT  213.84 74.628 214.367 74.646 ;
     RECT  213.84 82.728 214.367 82.746 ;
     RECT  213.84 85.428 214.367 85.446 ;
     RECT  213.84 88.2 214.367 88.218 ;
     RECT  213.84 99.162 214.367 99.18 ;
     RECT  213.84 101.97 214.367 101.988 ;
     RECT  213.84 107.37 214.367 107.388 ;
     RECT  213.84 118.638 214.367 118.656 ;
     RECT  213.84 121.338 214.367 121.356 ;
     RECT  213.84 13.644 214.907 13.662 ;
     RECT  213.84 105.138 214.907 105.156 ;
    LAYER M3 ;
     RECT  108 0.108 108.018 0.173 ;
     RECT  190.944 0.108 190.962 2.143 ;
     RECT  64.515 2.143 64.605 2.191 ;
     RECT  66.276 1.723 66.294 2.191 ;
     RECT  67.215 2.143 67.305 2.191 ;
     RECT  188.715 2.143 188.805 2.227 ;
     RECT  25.056 0.108 25.074 2.255 ;
     RECT  149.22 0.187 149.238 2.255 ;
     RECT  26.715 2.143 26.805 2.263 ;
     RECT  64.515 2.191 65.322 2.299 ;
     RECT  64.515 2.299 65.538 2.335 ;
     RECT  66.276 2.191 67.305 2.335 ;
     RECT  190.944 2.143 191.505 2.371 ;
     RECT  2.415 2.143 2.505 2.413 ;
     RECT  5.115 2.143 5.205 2.413 ;
     RECT  7.815 2.143 7.905 2.413 ;
     RECT  10.515 2.143 10.605 2.413 ;
     RECT  13.215 2.143 13.305 2.413 ;
     RECT  15.915 2.143 16.005 2.413 ;
     RECT  18.615 2.143 18.705 2.413 ;
     RECT  21.315 2.143 21.405 2.413 ;
     RECT  24.015 2.143 24.105 2.413 ;
     RECT  26.64 2.263 26.805 2.413 ;
     RECT  29.415 2.143 29.505 2.413 ;
     RECT  32.115 2.143 32.205 2.413 ;
     RECT  34.815 2.143 34.905 2.413 ;
     RECT  37.515 2.143 37.605 2.413 ;
     RECT  40.215 2.143 40.305 2.413 ;
     RECT  42.915 2.143 43.005 2.413 ;
     RECT  45.615 2.143 45.705 2.413 ;
     RECT  48.315 2.143 48.405 2.413 ;
     RECT  51.015 2.143 51.105 2.413 ;
     RECT  53.715 2.143 53.805 2.413 ;
     RECT  56.415 2.143 56.505 2.413 ;
     RECT  59.115 2.143 59.205 2.413 ;
     RECT  61.815 2.143 61.905 2.413 ;
     RECT  64.515 2.335 67.305 2.413 ;
     RECT  69.915 2.143 70.005 2.413 ;
     RECT  72.615 2.143 72.705 2.413 ;
     RECT  75.315 2.143 75.405 2.413 ;
     RECT  78.015 2.143 78.105 2.413 ;
     RECT  80.715 2.143 80.805 2.413 ;
     RECT  83.415 2.143 83.505 2.413 ;
     RECT  86.115 2.143 86.205 2.413 ;
     RECT  88.815 2.143 88.905 2.413 ;
     RECT  91.515 2.143 91.605 2.413 ;
     RECT  94.215 2.143 94.305 2.413 ;
     RECT  96.915 2.143 97.005 2.413 ;
     RECT  99.615 2.143 99.705 2.413 ;
     RECT  102.315 2.143 102.405 2.413 ;
     RECT  105.015 2.143 105.105 2.413 ;
     RECT  107.715 2.143 107.805 2.413 ;
     RECT  110.415 2.143 110.505 2.413 ;
     RECT  113.115 2.143 113.205 2.413 ;
     RECT  115.815 2.143 115.905 2.413 ;
     RECT  118.515 2.143 118.605 2.413 ;
     RECT  121.215 2.143 121.305 2.413 ;
     RECT  123.915 2.143 124.005 2.413 ;
     RECT  126.615 2.143 126.705 2.413 ;
     RECT  129.315 2.143 129.405 2.413 ;
     RECT  132.015 2.143 132.105 2.413 ;
     RECT  134.715 2.143 134.805 2.413 ;
     RECT  137.415 2.143 137.505 2.413 ;
     RECT  140.115 2.143 140.205 2.413 ;
     RECT  142.815 2.143 142.905 2.413 ;
     RECT  145.515 2.143 145.605 2.413 ;
     RECT  148.215 2.143 148.305 2.413 ;
     RECT  150.915 2.143 151.005 2.413 ;
     RECT  153.615 2.143 153.705 2.413 ;
     RECT  156.315 2.143 156.405 2.413 ;
     RECT  159.015 2.143 159.105 2.413 ;
     RECT  161.715 2.143 161.805 2.413 ;
     RECT  164.415 2.143 164.505 2.413 ;
     RECT  167.115 2.143 167.205 2.413 ;
     RECT  169.815 2.143 169.905 2.413 ;
     RECT  172.515 2.143 172.605 2.413 ;
     RECT  175.215 2.143 175.305 2.413 ;
     RECT  177.915 2.143 178.005 2.413 ;
     RECT  180.615 2.143 180.705 2.413 ;
     RECT  183.315 2.143 183.405 2.413 ;
     RECT  186.015 2.143 186.105 2.413 ;
     RECT  190.62 2.371 191.505 2.413 ;
     RECT  194.115 2.143 194.205 2.413 ;
     RECT  196.815 2.143 196.905 2.413 ;
     RECT  199.515 2.143 199.605 2.413 ;
     RECT  202.215 2.143 202.305 2.413 ;
     RECT  204.915 2.143 205.005 2.413 ;
     RECT  207.615 2.143 207.705 2.413 ;
     RECT  210.315 2.143 210.405 2.413 ;
     RECT  213.015 2.143 213.105 2.413 ;
     RECT  149.4 2.371 149.418 2.489 ;
     RECT  188.715 2.227 189.234 2.497 ;
     RECT  64.515 2.413 67.497 2.533 ;
     RECT  48.315 2.413 48.597 2.641 ;
     RECT  61.815 2.413 62.097 2.641 ;
     RECT  145.515 2.413 145.797 2.641 ;
     RECT  188.604 2.497 189.342 2.641 ;
     RECT  190.62 2.413 191.697 2.641 ;
     RECT  61.815 2.641 62.73 2.759 ;
     RECT  145.515 2.641 146.502 2.795 ;
     RECT  64.515 2.533 67.878 2.839 ;
     RECT  150.915 2.413 151.197 2.839 ;
     RECT  188.604 2.641 191.697 2.861 ;
     RECT  64.515 2.839 68.058 2.909 ;
     RECT  67.215 2.909 68.058 2.911 ;
     RECT  188.715 2.861 191.697 3.065 ;
     RECT  64.515 2.909 66.438 3.101 ;
     RECT  26.64 2.413 26.997 3.145 ;
     RECT  26.496 3.145 26.997 3.181 ;
     RECT  113.115 2.413 113.397 3.271 ;
     RECT  64.515 3.101 65.466 3.299 ;
     RECT  67.215 2.911 68.382 3.299 ;
     RECT  26.496 3.181 27.45 3.307 ;
     RECT  32.115 2.413 32.397 3.307 ;
     RECT  26.496 3.307 28.134 3.335 ;
     RECT  48.315 2.641 49.086 3.335 ;
     RECT  190.008 3.065 191.697 3.335 ;
     RECT  29.415 2.413 29.697 3.343 ;
     RECT  29.415 3.343 29.754 3.379 ;
     RECT  190.188 3.335 191.697 3.407 ;
     RECT  26.496 3.335 26.997 3.437 ;
     RECT  32.115 3.307 32.526 3.451 ;
     RECT  27.792 3.335 28.134 3.569 ;
     RECT  29.304 3.379 29.754 3.569 ;
     RECT  32.112 3.451 32.526 3.569 ;
     RECT  149.724 2.641 149.742 3.569 ;
     RECT  150.48 2.839 151.197 3.577 ;
     RECT  27.792 3.569 27.81 3.605 ;
     RECT  29.304 3.569 29.697 3.605 ;
     RECT  31.284 3.271 31.302 3.605 ;
     RECT  149.544 3.649 149.562 3.725 ;
     RECT  150.372 3.577 151.197 3.875 ;
     RECT  210.315 2.413 210.597 4.261 ;
     RECT  190.836 3.407 191.697 4.289 ;
     RECT  24.015 2.413 24.297 4.423 ;
     RECT  150.84 3.875 151.197 4.523 ;
     RECT  32.115 3.569 32.526 4.531 ;
     RECT  2.415 2.413 2.697 5.431 ;
     RECT  2.376 5.431 2.697 5.611 ;
     RECT  0.216 5.161 0.234 5.645 ;
     RECT  2.376 5.611 3.006 5.737 ;
     RECT  2.376 5.737 3.294 5.765 ;
     RECT  4.068 5.737 4.086 5.773 ;
     RECT  2.415 5.765 3.294 5.881 ;
     RECT  4.068 5.773 4.23 5.881 ;
     RECT  5.115 2.413 5.397 5.881 ;
     RECT  213.015 2.413 213.297 5.881 ;
     RECT  2.415 5.881 5.397 5.971 ;
     RECT  118.515 2.413 118.797 5.971 ;
     RECT  212.472 5.881 213.297 5.999 ;
     RECT  2.415 5.971 5.814 6.035 ;
     RECT  210.024 4.261 210.597 6.079 ;
     RECT  4.536 6.035 5.814 6.107 ;
     RECT  210.024 6.079 211.05 6.115 ;
     RECT  2.415 6.035 3.438 6.269 ;
     RECT  210.024 6.115 211.23 6.269 ;
     RECT  214.344 5.707 214.362 6.269 ;
     RECT  3.42 6.269 3.438 6.853 ;
     RECT  3.42 6.853 3.51 6.881 ;
     RECT  3.492 6.881 3.51 7.933 ;
     RECT  210.024 6.269 210.597 7.963 ;
     RECT  2.415 6.269 2.697 8.041 ;
     RECT  3.492 7.933 3.546 8.041 ;
     RECT  5.115 6.107 5.814 8.041 ;
     RECT  2.415 8.041 3.546 8.159 ;
     RECT  5.115 8.041 6.138 8.159 ;
     RECT  2.415 8.159 3.51 8.231 ;
     RECT  0.216 8.107 0.234 8.267 ;
     RECT  5.115 8.159 5.814 8.311 ;
     RECT  213.015 5.999 213.297 8.311 ;
     RECT  209.736 7.963 210.597 8.347 ;
     RECT  2.415 8.231 3.438 8.429 ;
     RECT  4.86 8.311 5.814 8.477 ;
     RECT  209.736 8.347 210.69 8.477 ;
     RECT  214.344 8.311 214.362 8.477 ;
     RECT  7.815 2.413 8.097 8.509 ;
     RECT  209.88 8.477 210.69 8.525 ;
     RECT  5.004 8.477 5.814 8.537 ;
     RECT  211.968 8.473 211.986 8.545 ;
     RECT  213.012 8.311 213.297 8.545 ;
     RECT  211.968 8.545 213.297 8.699 ;
     RECT  2.415 8.429 2.697 10.561 ;
     RECT  3.42 8.429 3.438 10.561 ;
     RECT  0.216 10.651 0.234 10.697 ;
     RECT  7.164 8.509 8.097 11.011 ;
     RECT  213.015 8.699 213.297 11.011 ;
     RECT  6.552 11.011 8.097 11.129 ;
     RECT  213.015 11.011 213.426 11.129 ;
     RECT  123.915 2.413 124.197 11.137 ;
     RECT  209.052 11.131 209.07 11.137 ;
     RECT  208.908 11.137 209.07 11.201 ;
     RECT  207.615 2.413 207.897 11.209 ;
     RECT  214.344 11.011 214.362 11.213 ;
     RECT  213.015 11.129 213.297 11.245 ;
     RECT  207.615 11.209 208.098 11.261 ;
     RECT  2.415 10.561 3.438 11.309 ;
     RECT  211.932 11.101 211.95 11.399 ;
     RECT  212.724 11.245 213.297 11.399 ;
     RECT  6.624 11.129 8.097 11.405 ;
     RECT  208.908 11.201 208.926 11.435 ;
     RECT  7.056 11.405 8.097 11.821 ;
     RECT  7.056 11.821 8.514 11.849 ;
     RECT  7.272 11.849 8.514 11.939 ;
     RECT  7.38 11.939 8.514 12.523 ;
     RECT  2.415 11.309 2.697 12.991 ;
     RECT  3.42 11.309 3.438 13.063 ;
     RECT  1.728 12.991 2.697 13.171 ;
     RECT  3.42 13.063 3.546 13.171 ;
     RECT  7.38 12.523 8.694 13.171 ;
     RECT  9.504 11.911 9.522 13.171 ;
     RECT  1.728 13.171 3.546 13.181 ;
     RECT  2.415 13.181 3.546 13.289 ;
     RECT  2.415 13.289 3.438 13.559 ;
     RECT  213.015 11.399 213.297 13.711 ;
     RECT  213.015 13.711 213.354 13.945 ;
     RECT  7.38 13.171 9.522 13.981 ;
     RECT  10.515 2.413 10.797 13.981 ;
     RECT  214.884 13.639 214.902 13.997 ;
     RECT  7.38 13.981 10.797 14.071 ;
     RECT  213.015 13.945 213.534 14.071 ;
     RECT  7.092 14.071 10.797 14.099 ;
     RECT  212.976 14.071 213.534 14.099 ;
     RECT  212.976 14.099 213.297 14.171 ;
     RECT  204.915 2.413 205.197 14.377 ;
     RECT  206.64 14.377 206.658 14.395 ;
     RECT  204.915 14.377 205.902 14.429 ;
     RECT  206.64 14.395 206.838 14.443 ;
     RECT  206.028 14.443 206.838 14.573 ;
     RECT  206.028 14.573 206.658 14.675 ;
     RECT  2.415 13.559 2.697 15.601 ;
     RECT  3.42 13.559 3.438 15.601 ;
     RECT  0.216 15.421 0.234 15.725 ;
     RECT  2.415 15.601 3.438 15.997 ;
     RECT  5.004 8.537 5.397 15.997 ;
     RECT  4.428 15.997 5.397 16.033 ;
     RECT  2.415 15.997 3.51 16.141 ;
     RECT  7.092 14.099 8.694 16.259 ;
     RECT  4.392 16.033 5.397 16.331 ;
     RECT  6.336 16.231 6.354 16.375 ;
     RECT  4.428 16.331 5.397 16.403 ;
     RECT  5.004 16.403 5.397 16.411 ;
     RECT  6.3 16.375 6.354 16.411 ;
     RECT  2.415 16.141 3.654 16.439 ;
     RECT  5.004 16.411 6.354 16.541 ;
     RECT  6.3 16.541 6.354 16.565 ;
     RECT  190.116 16.555 190.134 16.771 ;
     RECT  7.416 16.259 8.694 16.799 ;
     RECT  190.116 16.771 190.422 16.799 ;
     RECT  40.215 2.413 40.497 16.807 ;
     RECT  190.404 16.799 190.422 16.829 ;
     RECT  3.42 16.439 3.438 16.835 ;
     RECT  66.204 3.101 66.438 16.835 ;
     RECT  68.364 3.299 68.382 16.835 ;
     RECT  214.344 16.699 214.362 16.871 ;
     RECT  7.815 16.799 8.694 16.951 ;
     RECT  9.504 14.099 10.797 16.951 ;
     RECT  211.464 16.915 211.482 16.951 ;
     RECT  213.015 14.171 213.297 16.951 ;
     RECT  209.88 8.525 210.597 17.035 ;
     RECT  211.464 16.951 212.022 17.035 ;
     RECT  209.88 17.035 212.022 17.069 ;
     RECT  213.015 16.951 213.714 17.069 ;
     RECT  209.88 17.069 211.482 17.105 ;
     RECT  212.256 17.221 212.274 17.375 ;
     RECT  209.88 17.105 210.942 17.447 ;
     RECT  2.415 16.439 2.697 18.031 ;
     RECT  2.415 18.031 2.898 18.187 ;
     RECT  113.115 3.271 113.598 18.235 ;
     RECT  2.304 18.187 2.898 18.301 ;
     RECT  3.672 18.031 3.69 18.301 ;
     RECT  6.336 16.565 6.354 18.301 ;
     RECT  6.336 18.301 7.002 18.391 ;
     RECT  2.304 18.301 3.69 18.419 ;
     RECT  6.228 18.391 7.002 18.419 ;
     RECT  5.004 16.541 5.397 18.427 ;
     RECT  6.228 18.419 6.822 18.427 ;
     RECT  113.115 18.235 113.994 18.571 ;
     RECT  2.304 18.419 3.006 18.599 ;
     RECT  2.412 18.599 3.006 18.689 ;
     RECT  2.412 18.689 2.697 18.725 ;
     RECT  5.004 18.427 6.822 19.103 ;
     RECT  7.815 16.951 10.797 19.111 ;
     RECT  214.344 19.435 214.362 19.571 ;
     RECT  209.88 17.447 210.69 19.627 ;
     RECT  209.736 19.627 210.69 19.651 ;
     RECT  211.716 19.381 211.734 19.651 ;
     RECT  209.736 19.651 211.734 19.679 ;
     RECT  209.88 19.679 211.734 19.769 ;
     RECT  209.88 19.769 211.626 19.805 ;
     RECT  0.216 20.551 0.234 20.717 ;
     RECT  6.228 19.103 6.714 20.731 ;
     RECT  198.648 16.951 198.666 20.821 ;
     RECT  6.228 20.731 6.858 20.849 ;
     RECT  198.108 20.821 198.666 20.861 ;
     RECT  204.915 14.429 205.197 20.875 ;
     RECT  206.028 14.675 206.586 20.875 ;
     RECT  2.415 18.725 2.697 20.929 ;
     RECT  7.596 19.111 10.797 20.929 ;
     RECT  198.36 20.861 198.666 20.957 ;
     RECT  118.116 5.971 118.797 20.965 ;
     RECT  3.492 20.965 3.51 21.001 ;
     RECT  6.984 20.929 10.797 21.005 ;
     RECT  2.34 20.929 2.697 21.029 ;
     RECT  3.492 21.001 3.978 21.119 ;
     RECT  3.96 21.119 3.978 21.191 ;
     RECT  204.915 20.875 206.586 21.263 ;
     RECT  207.615 11.261 207.897 21.271 ;
     RECT  198.648 20.957 198.666 21.361 ;
     RECT  199.515 2.413 199.797 21.361 ;
     RECT  123.228 11.137 124.197 21.389 ;
     RECT  207.036 21.271 207.897 21.389 ;
     RECT  7.236 21.005 10.797 21.395 ;
     RECT  40.215 16.807 40.554 21.631 ;
     RECT  214.344 22.081 214.362 22.253 ;
     RECT  213.015 17.069 213.297 22.351 ;
     RECT  12.024 16.807 12.042 22.513 ;
     RECT  21.315 2.413 21.597 22.513 ;
     RECT  5.004 19.103 5.397 22.541 ;
     RECT  123.084 21.505 123.102 22.541 ;
     RECT  18.615 2.413 18.897 22.549 ;
     RECT  91.515 2.413 91.797 22.549 ;
     RECT  66.204 16.835 66.222 22.577 ;
     RECT  209.88 19.805 211.014 22.603 ;
     RECT  212.58 22.351 213.297 22.613 ;
     RECT  209.628 22.603 211.014 22.649 ;
     RECT  210.276 22.649 211.014 23.189 ;
     RECT  2.415 21.029 2.697 23.227 ;
     RECT  2.304 23.227 2.697 23.251 ;
     RECT  2.304 23.251 3.222 23.431 ;
     RECT  2.304 23.431 3.654 23.549 ;
     RECT  2.304 23.549 3.222 23.729 ;
     RECT  2.415 23.729 3.222 23.819 ;
     RECT  204.915 21.263 205.197 24.241 ;
     RECT  205.92 21.263 205.938 24.241 ;
     RECT  204.264 24.241 205.938 24.317 ;
     RECT  204.264 24.317 205.197 24.509 ;
     RECT  209.196 22.981 209.214 24.781 ;
     RECT  209.124 24.781 209.214 24.859 ;
     RECT  208.98 24.859 209.214 24.899 ;
     RECT  214.308 24.943 214.326 24.989 ;
     RECT  209.196 24.899 209.214 25.051 ;
     RECT  210.315 23.189 211.014 25.051 ;
     RECT  110.415 2.413 110.697 25.177 ;
     RECT  212.004 25.051 212.022 25.205 ;
     RECT  113.115 18.571 114.246 25.213 ;
     RECT  209.196 25.051 211.014 25.241 ;
     RECT  198.648 21.361 199.797 25.285 ;
     RECT  110.415 25.177 111.294 25.313 ;
     RECT  113.115 25.213 114.57 25.313 ;
     RECT  209.196 25.241 209.214 25.349 ;
     RECT  0.216 25.681 0.234 25.805 ;
     RECT  2.415 23.819 2.697 25.861 ;
     RECT  5.115 22.541 5.397 25.861 ;
     RECT  7.38 21.395 10.797 25.889 ;
     RECT  2.415 25.861 3.438 25.979 ;
     RECT  7.596 25.889 10.797 25.979 ;
     RECT  4.824 25.861 5.397 26.059 ;
     RECT  6.228 20.849 6.246 26.059 ;
     RECT  4.824 26.059 6.246 26.095 ;
     RECT  2.415 25.979 3.294 26.123 ;
     RECT  7.815 25.979 10.797 26.131 ;
     RECT  4.212 26.095 6.246 26.221 ;
     RECT  2.415 26.123 2.754 26.249 ;
     RECT  4.212 26.221 6.858 26.249 ;
     RECT  2.415 26.249 2.697 26.257 ;
     RECT  7.815 26.131 10.854 26.285 ;
     RECT  7.815 26.285 8.154 26.357 ;
     RECT  4.428 26.249 5.634 26.393 ;
     RECT  2.304 26.257 2.697 26.429 ;
     RECT  6.84 26.249 6.858 26.429 ;
     RECT  8.964 26.285 10.854 26.671 ;
     RECT  12.024 22.513 12.114 26.671 ;
     RECT  13.215 2.413 13.497 27.139 ;
     RECT  205.92 24.317 205.938 27.163 ;
     RECT  8.964 26.671 12.114 27.211 ;
     RECT  12.888 27.139 13.497 27.211 ;
     RECT  107.715 2.413 107.997 27.211 ;
     RECT  107.715 27.211 108.594 27.329 ;
     RECT  205.92 27.163 206.37 27.341 ;
     RECT  4.68 26.393 5.634 27.365 ;
     RECT  8.964 27.211 13.497 27.365 ;
     RECT  110.415 25.313 110.697 27.409 ;
     RECT  5.115 27.365 5.634 27.481 ;
     RECT  6.876 27.211 6.894 27.481 ;
     RECT  8.964 27.365 9.342 27.509 ;
     RECT  213.015 22.613 213.297 27.571 ;
     RECT  10.26 27.365 13.497 27.599 ;
     RECT  110.124 27.409 110.697 27.599 ;
     RECT  198.648 25.285 200.07 27.607 ;
     RECT  198.432 27.607 200.07 27.635 ;
     RECT  110.415 27.599 110.697 27.643 ;
     RECT  198.432 27.635 199.962 27.643 ;
     RECT  214.344 27.679 214.362 27.725 ;
     RECT  110.415 27.643 110.718 27.743 ;
     RECT  7.815 26.357 8.097 27.751 ;
     RECT  8.964 27.509 9.306 27.751 ;
     RECT  210.315 25.241 211.014 27.751 ;
     RECT  212.58 27.571 213.297 27.751 ;
     RECT  210.315 27.751 213.297 27.821 ;
     RECT  210.315 27.821 211.05 27.841 ;
     RECT  209.916 27.841 211.05 27.869 ;
     RECT  208.908 27.679 208.926 27.913 ;
     RECT  209.916 27.869 211.014 27.913 ;
     RECT  79.668 27.841 79.686 27.917 ;
     RECT  198.36 27.643 199.962 27.917 ;
     RECT  198.36 27.917 199.89 27.941 ;
     RECT  212.4 27.821 213.297 27.941 ;
     RECT  212.652 27.941 213.297 28.013 ;
     RECT  67.215 3.299 67.497 28.111 ;
     RECT  79.488 28.021 79.506 28.139 ;
     RECT  79.344 28.171 79.362 28.211 ;
     RECT  205.92 27.341 205.938 28.219 ;
     RECT  2.415 26.429 2.697 28.291 ;
     RECT  7.815 27.751 9.306 28.291 ;
     RECT  10.26 27.599 12.114 28.291 ;
     RECT  205.92 28.219 206.154 28.291 ;
     RECT  0.54 28.111 0.558 28.301 ;
     RECT  205.92 28.291 206.514 28.349 ;
     RECT  2.415 28.291 2.79 28.381 ;
     RECT  7.815 28.291 12.114 28.445 ;
     RECT  2.415 28.381 3.402 28.481 ;
     RECT  2.415 28.481 3.33 28.679 ;
     RECT  4.068 28.561 4.086 28.679 ;
     RECT  117.864 20.965 118.797 28.787 ;
     RECT  208.908 27.913 211.014 28.787 ;
     RECT  26.715 3.437 26.997 28.795 ;
     RECT  113.115 25.313 114.246 28.823 ;
     RECT  20.376 28.759 20.394 29.065 ;
     RECT  20.376 29.065 20.466 29.093 ;
     RECT  26.316 28.795 26.997 29.093 ;
     RECT  10.26 28.445 12.114 29.533 ;
     RECT  10.26 29.533 12.186 29.605 ;
     RECT  13.215 27.599 13.497 29.605 ;
     RECT  208.908 28.787 210.597 29.759 ;
     RECT  5.115 27.481 6.894 29.839 ;
     RECT  7.815 28.445 9.414 29.839 ;
     RECT  10.26 29.605 13.497 29.839 ;
     RECT  5.115 29.839 9.414 30.145 ;
     RECT  10.26 29.839 13.554 30.145 ;
     RECT  14.652 30.073 14.67 30.307 ;
     RECT  18.072 22.549 18.897 30.307 ;
     RECT  15.915 2.413 16.197 30.379 ;
     RECT  18 30.307 18.897 30.379 ;
     RECT  5.115 30.145 13.554 30.415 ;
     RECT  14.436 30.307 14.67 30.415 ;
     RECT  2.415 28.679 2.697 30.451 ;
     RECT  5.115 30.415 14.994 30.451 ;
     RECT  15.876 30.379 16.197 30.451 ;
     RECT  17.172 30.379 17.19 30.451 ;
     RECT  17.964 30.379 18.897 30.541 ;
     RECT  17.964 30.541 19.17 30.569 ;
     RECT  214.344 30.427 214.362 30.641 ;
     RECT  17.064 30.451 17.226 30.649 ;
     RECT  5.115 30.451 16.197 30.685 ;
     RECT  17.028 30.649 17.298 30.685 ;
     RECT  208.908 29.759 209.43 30.715 ;
     RECT  210.315 29.759 210.597 30.715 ;
     RECT  2.376 30.451 2.697 30.721 ;
     RECT  208.908 30.715 210.597 30.755 ;
     RECT  21.315 22.513 21.798 30.811 ;
     RECT  32.115 4.531 32.922 30.811 ;
     RECT  23.58 4.423 24.297 30.839 ;
     RECT  211.464 30.721 211.482 30.875 ;
     RECT  1.728 30.721 2.697 30.893 ;
     RECT  5.115 30.685 17.298 30.949 ;
     RECT  5.112 30.949 17.298 30.989 ;
     RECT  2.304 30.893 2.697 31.019 ;
     RECT  3.852 30.991 3.87 31.217 ;
     RECT  18.072 30.569 19.17 31.225 ;
     RECT  5.115 30.989 17.298 31.253 ;
     RECT  205.92 28.349 205.938 31.415 ;
     RECT  15.696 31.253 17.298 31.423 ;
     RECT  18.072 31.225 19.386 31.423 ;
     RECT  15.696 31.423 19.386 31.531 ;
     RECT  20.448 29.093 20.466 31.531 ;
     RECT  15.696 31.531 20.466 31.649 ;
     RECT  119.916 31.531 119.934 31.649 ;
     RECT  23.652 30.839 24.297 31.657 ;
     RECT  26.388 29.093 26.997 31.657 ;
     RECT  198.648 27.941 199.89 31.657 ;
     RECT  15.696 31.649 17.19 31.685 ;
     RECT  26.388 31.657 27.702 31.693 ;
     RECT  15.696 31.685 17.118 31.721 ;
     RECT  18.072 31.649 20.466 31.721 ;
     RECT  26.388 31.693 27.846 31.765 ;
     RECT  23.652 31.657 24.714 31.801 ;
     RECT  25.992 31.765 27.846 31.801 ;
     RECT  29.415 3.605 29.697 31.891 ;
     RECT  198.396 31.657 199.89 31.891 ;
     RECT  23.652 31.801 25.146 31.999 ;
     RECT  25.992 31.801 28.17 31.999 ;
     RECT  29.415 31.891 29.79 31.999 ;
     RECT  118.515 28.787 118.797 31.999 ;
     RECT  23.508 31.999 25.146 32.035 ;
     RECT  198.396 31.891 200.178 32.059 ;
     RECT  23.508 32.035 25.218 32.071 ;
     RECT  25.992 31.999 29.79 32.071 ;
     RECT  22.752 31.999 22.77 32.197 ;
     RECT  23.508 32.071 29.79 32.197 ;
     RECT  198 32.059 200.178 32.225 ;
     RECT  107.715 27.329 107.997 32.269 ;
     RECT  5.115 31.253 14.85 32.305 ;
     RECT  15.696 31.721 17.082 32.305 ;
     RECT  118.515 31.999 119.178 32.305 ;
     RECT  21.315 30.811 21.87 32.341 ;
     RECT  22.752 32.197 29.79 32.341 ;
     RECT  210.315 30.755 210.597 32.341 ;
     RECT  114.624 32.341 114.642 32.459 ;
     RECT  118.515 32.305 119.502 32.459 ;
     RECT  198.36 32.225 200.178 32.459 ;
     RECT  201.42 31.531 201.438 32.459 ;
     RECT  208.908 30.755 209.43 32.459 ;
     RECT  198.432 32.459 200.178 32.467 ;
     RECT  107.064 32.269 107.997 32.495 ;
     RECT  118.515 32.459 119.178 32.495 ;
     RECT  198.432 32.467 200.358 32.495 ;
     RECT  5.115 32.305 17.082 32.539 ;
     RECT  18.072 31.721 19.17 32.539 ;
     RECT  201.312 32.539 201.33 32.575 ;
     RECT  198.468 32.495 200.358 32.603 ;
     RECT  3.816 32.575 3.834 32.611 ;
     RECT  21.315 32.341 29.79 32.611 ;
     RECT  198.468 32.603 200.286 32.639 ;
     RECT  21.315 32.611 30.114 32.737 ;
     RECT  198.468 32.639 200.178 32.801 ;
     RECT  32.115 30.811 32.994 32.845 ;
     RECT  3.708 32.611 3.834 32.875 ;
     RECT  5.115 32.539 19.17 32.881 ;
     RECT  20.448 31.721 20.466 32.881 ;
     RECT  21.315 32.737 30.546 32.881 ;
     RECT  3.708 32.875 4.014 32.999 ;
     RECT  201.24 32.575 201.33 32.999 ;
     RECT  5.115 32.881 19.71 33.019 ;
     RECT  118.515 32.495 118.797 33.043 ;
     RECT  3.708 32.999 3.726 33.053 ;
     RECT  4.752 33.019 19.71 33.079 ;
     RECT  20.448 32.881 30.546 33.079 ;
     RECT  31.608 32.845 32.994 33.079 ;
     RECT  33.804 32.881 33.822 33.079 ;
     RECT  4.752 33.079 30.546 33.115 ;
     RECT  31.356 33.079 33.822 33.115 ;
     RECT  194.115 2.413 194.397 33.115 ;
     RECT  2.415 31.019 2.697 33.151 ;
     RECT  2.415 33.151 3.402 33.241 ;
     RECT  108.828 33.151 108.846 33.241 ;
     RECT  2.376 33.241 3.402 33.269 ;
     RECT  210.315 32.341 211.266 33.269 ;
     RECT  2.376 33.269 2.754 33.277 ;
     RECT  107.715 32.495 107.997 33.277 ;
     RECT  108.828 33.241 108.918 33.277 ;
     RECT  121.215 2.413 121.497 33.277 ;
     RECT  194.115 33.115 194.706 33.277 ;
     RECT  214.236 33.211 214.254 33.341 ;
     RECT  210.315 33.269 210.597 33.355 ;
     RECT  106.596 33.241 106.614 33.377 ;
     RECT  107.715 33.277 108.918 33.377 ;
     RECT  190.44 33.277 190.458 33.377 ;
     RECT  194.115 33.277 194.778 33.377 ;
     RECT  4.752 33.115 33.822 33.421 ;
     RECT  34.815 2.413 35.097 33.421 ;
     RECT  213.015 28.013 213.297 33.421 ;
     RECT  2.304 33.277 2.754 33.449 ;
     RECT  107.715 33.377 108.594 33.449 ;
     RECT  4.464 33.421 33.822 33.511 ;
     RECT  0.216 33.307 0.234 33.539 ;
     RECT  4.464 33.511 33.966 33.539 ;
     RECT  118.26 33.043 118.797 33.539 ;
     RECT  211.896 33.421 211.914 33.539 ;
     RECT  29.16 33.539 33.966 33.575 ;
     RECT  198.468 32.801 199.797 33.583 ;
     RECT  212.904 33.421 213.297 33.611 ;
     RECT  4.464 33.539 28.386 33.629 ;
     RECT  198.36 33.583 199.797 33.629 ;
     RECT  198.576 33.629 199.797 33.647 ;
     RECT  29.196 33.575 33.966 33.655 ;
     RECT  34.776 33.421 35.097 33.655 ;
     RECT  2.376 33.449 2.754 33.719 ;
     RECT  2.415 33.719 2.754 33.809 ;
     RECT  5.115 33.629 28.386 33.989 ;
     RECT  210.312 33.355 210.597 34.027 ;
     RECT  120.96 33.277 121.497 34.159 ;
     RECT  167.115 2.413 167.397 34.231 ;
     RECT  208.908 32.459 208.926 34.231 ;
     RECT  120.708 34.159 121.497 34.259 ;
     RECT  198.576 33.647 198.594 34.259 ;
     RECT  17.172 33.989 28.386 34.315 ;
     RECT  29.196 33.655 35.097 34.315 ;
     RECT  166.428 34.231 167.397 34.349 ;
     RECT  207.615 21.389 207.897 34.465 ;
     RECT  208.656 34.231 208.926 34.465 ;
     RECT  164.415 2.413 164.697 34.501 ;
     RECT  17.172 34.315 35.097 34.619 ;
     RECT  67.215 28.111 67.59 34.619 ;
     RECT  67.215 34.619 67.497 34.627 ;
     RECT  33.732 34.619 33.966 34.685 ;
     RECT  66.996 34.627 67.497 34.735 ;
     RECT  33.912 34.685 33.966 34.736 ;
     RECT  207.615 34.465 208.926 34.747 ;
     RECT  209.664 34.027 210.597 34.747 ;
     RECT  207.615 34.747 210.597 34.781 ;
     RECT  5.115 33.989 16.434 34.861 ;
     RECT  17.172 34.619 32.994 34.861 ;
     RECT  33.912 34.736 33.93 34.889 ;
     RECT  208.908 34.781 210.597 34.889 ;
     RECT  208.908 34.889 209.286 34.925 ;
     RECT  94.215 2.413 94.497 35.041 ;
     RECT  66.384 34.735 67.497 35.159 ;
     RECT  65.628 33.241 65.646 35.275 ;
     RECT  66.384 35.159 66.402 35.275 ;
     RECT  5.115 34.861 32.994 35.581 ;
     RECT  64.515 3.299 64.797 35.671 ;
     RECT  169.815 2.413 170.097 35.671 ;
     RECT  61.815 2.759 62.097 35.701 ;
     RECT  86.115 2.413 86.397 35.707 ;
     RECT  61.344 35.701 62.097 35.741 ;
     RECT  169.815 35.671 170.874 35.741 ;
     RECT  61.524 35.741 62.097 35.789 ;
     RECT  170.856 35.741 170.874 35.789 ;
     RECT  5.115 35.581 33.174 35.807 ;
     RECT  86.115 35.707 86.598 35.845 ;
     RECT  5.115 35.807 18.954 35.851 ;
     RECT  19.692 35.807 33.174 35.851 ;
     RECT  34.815 34.619 35.097 35.851 ;
     RECT  0.54 35.671 0.558 35.885 ;
     RECT  86.115 35.845 86.958 35.885 ;
     RECT  2.415 33.809 2.697 35.941 ;
     RECT  34.812 35.851 35.097 35.941 ;
     RECT  36 33.547 36.018 35.941 ;
     RECT  55.188 35.707 55.206 35.941 ;
     RECT  56.415 2.413 56.697 35.941 ;
     RECT  213.015 33.611 213.297 35.947 ;
     RECT  164.016 34.501 164.697 35.969 ;
     RECT  208.908 34.925 208.926 35.969 ;
     RECT  2.415 35.941 2.826 35.977 ;
     RECT  4.284 35.851 4.302 35.977 ;
     RECT  5.112 35.851 18.954 35.977 ;
     RECT  34.812 35.941 36.018 36.013 ;
     RECT  37.515 2.413 37.797 36.013 ;
     RECT  38.772 35.941 38.79 36.013 ;
     RECT  4.284 35.977 18.954 36.014 ;
     RECT  2.415 35.977 3.402 36.041 ;
     RECT  55.188 35.941 56.697 36.041 ;
     RECT  213.015 35.947 213.678 36.041 ;
     RECT  34.596 36.013 36.018 36.049 ;
     RECT  37.152 36.013 37.797 36.085 ;
     RECT  55.188 36.041 55.206 36.113 ;
     RECT  19.692 35.851 33.282 36.121 ;
     RECT  34.092 36.049 36.018 36.121 ;
     RECT  207.615 34.781 207.897 36.121 ;
     RECT  207.615 36.121 208.026 36.173 ;
     RECT  2.415 36.041 2.718 36.239 ;
     RECT  3.528 36.121 3.546 36.239 ;
     RECT  40.215 21.631 41.238 36.247 ;
     RECT  42.915 2.413 43.197 36.247 ;
     RECT  4.32 36.014 18.954 36.275 ;
     RECT  212.22 36.121 212.238 36.347 ;
     RECT  19.692 36.121 36.018 36.355 ;
     RECT  37.044 36.085 37.797 36.355 ;
     RECT  38.772 36.013 39.222 36.355 ;
     RECT  19.692 36.355 36.234 36.391 ;
     RECT  37.044 36.355 39.222 36.391 ;
     RECT  40.215 36.247 41.85 36.391 ;
     RECT  4.644 36.275 18.954 36.419 ;
     RECT  126.615 2.413 126.897 36.523 ;
     RECT  42.804 36.247 43.197 36.553 ;
     RECT  19.692 36.391 41.85 36.589 ;
     RECT  42.804 36.553 43.614 36.589 ;
     RECT  99.615 2.413 99.897 36.625 ;
     RECT  188.715 3.065 188.997 36.751 ;
     RECT  196.815 2.413 197.097 36.751 ;
     RECT  199.515 33.647 199.797 36.751 ;
     RECT  145.515 2.795 145.797 36.763 ;
     RECT  153.615 2.413 153.897 36.763 ;
     RECT  161.715 2.413 161.997 36.763 ;
     RECT  169.815 35.741 170.097 36.763 ;
     RECT  177.915 2.413 178.197 36.763 ;
     RECT  126.615 36.523 127.386 36.779 ;
     RECT  188.604 36.751 188.997 36.797 ;
     RECT  196.704 36.751 197.097 36.797 ;
     RECT  199.404 36.751 199.797 36.797 ;
     RECT  5.115 36.419 18.954 36.811 ;
     RECT  19.692 36.589 43.614 36.811 ;
     RECT  138.528 36.763 138.546 36.893 ;
     RECT  145.515 36.763 146.502 36.893 ;
     RECT  161.715 36.763 162.486 36.893 ;
     RECT  169.815 36.763 170.442 36.893 ;
     RECT  177.915 36.763 178.434 36.893 ;
     RECT  190.404 36.763 190.422 36.893 ;
     RECT  128.484 36.859 128.502 36.896 ;
     RECT  64.224 35.671 64.797 37.021 ;
     RECT  65.628 35.275 66.402 37.021 ;
     RECT  5.115 36.811 43.614 37.049 ;
     RECT  64.224 37.021 66.402 37.049 ;
     RECT  59.115 2.413 59.397 37.051 ;
     RECT  132.015 2.413 132.297 37.093 ;
     RECT  27.756 37.049 43.614 37.121 ;
     RECT  80.715 2.413 80.997 37.147 ;
     RECT  80.136 37.147 80.997 37.165 ;
     RECT  86.115 35.885 86.397 37.291 ;
     RECT  27.828 37.121 43.614 37.319 ;
     RECT  91.476 22.549 91.797 37.319 ;
     RECT  78.015 2.413 78.297 37.387 ;
     RECT  61.815 35.789 62.097 37.435 ;
     RECT  67.215 35.159 67.497 37.435 ;
     RECT  69.915 2.413 70.197 37.435 ;
     RECT  80.136 37.165 81.09 37.435 ;
     RECT  82.656 37.147 82.674 37.435 ;
     RECT  83.415 2.413 83.697 37.435 ;
     RECT  86.115 37.291 86.598 37.435 ;
     RECT  148.215 2.413 148.497 37.435 ;
     RECT  80.136 37.435 81.126 37.471 ;
     RECT  159.015 2.413 159.297 37.471 ;
     RECT  27.828 37.319 43.578 37.499 ;
     RECT  67.14 37.435 67.497 37.531 ;
     RECT  45.615 2.413 45.897 37.547 ;
     RECT  48.315 3.335 48.597 37.547 ;
     RECT  51.015 2.413 51.297 37.547 ;
     RECT  53.715 2.413 53.997 37.547 ;
     RECT  56.415 36.041 56.697 37.547 ;
     RECT  58.464 37.051 59.397 37.547 ;
     RECT  72.615 2.413 72.897 37.547 ;
     RECT  75.315 2.413 75.597 37.547 ;
     RECT  82.656 37.435 83.697 37.547 ;
     RECT  126.615 36.779 126.897 37.547 ;
     RECT  129.315 2.413 129.597 37.547 ;
     RECT  131.724 37.093 132.297 37.547 ;
     RECT  134.715 2.413 134.997 37.547 ;
     RECT  137.415 2.413 137.697 37.547 ;
     RECT  140.115 2.413 140.397 37.547 ;
     RECT  142.815 2.413 143.097 37.547 ;
     RECT  145.515 36.893 145.797 37.547 ;
     RECT  150.915 4.523 151.197 37.547 ;
     RECT  153.615 36.763 154.494 37.547 ;
     RECT  156.315 2.413 156.597 37.547 ;
     RECT  158.364 37.471 159.297 37.547 ;
     RECT  161.715 36.893 161.997 37.547 ;
     RECT  164.415 35.969 164.697 37.547 ;
     RECT  169.815 36.893 170.097 37.547 ;
     RECT  172.515 2.413 172.797 37.547 ;
     RECT  66.276 37.049 66.402 37.561 ;
     RECT  67.14 37.531 67.806 37.561 ;
     RECT  158.364 37.547 159.105 37.561 ;
     RECT  69.915 37.435 70.722 37.565 ;
     RECT  82.656 37.547 83.505 37.565 ;
     RECT  86.115 37.435 86.958 37.565 ;
     RECT  158.292 37.561 159.105 37.579 ;
     RECT  41.796 37.499 43.578 37.589 ;
     RECT  58.464 37.547 59.205 37.589 ;
     RECT  61.056 37.435 61.074 37.589 ;
     RECT  64.224 37.049 65.322 37.589 ;
     RECT  66.276 37.561 67.806 37.589 ;
     RECT  80.136 37.471 81.27 37.589 ;
     RECT  131.724 37.547 132.105 37.589 ;
     RECT  148.215 37.435 148.77 37.589 ;
     RECT  149.976 37.531 149.994 37.589 ;
     RECT  167.115 34.349 167.397 37.597 ;
     RECT  61.815 37.435 62.766 37.613 ;
     RECT  78.015 37.387 78.75 37.613 ;
     RECT  82.656 37.565 82.674 37.613 ;
     RECT  86.94 37.565 86.958 37.613 ;
     RECT  42.3 37.589 43.434 37.625 ;
     RECT  60.012 37.579 60.03 37.625 ;
     RECT  61.815 37.613 62.622 37.625 ;
     RECT  154.476 37.547 154.494 37.625 ;
     RECT  157.968 37.579 159.105 37.625 ;
     RECT  27.828 37.499 41.058 37.661 ;
     RECT  66.384 37.589 67.305 37.661 ;
     RECT  99.54 36.625 99.897 37.741 ;
     RECT  27.828 37.661 41.022 37.769 ;
     RECT  39.168 37.769 41.022 37.817 ;
     RECT  45.615 37.547 45.705 37.817 ;
     RECT  48.315 37.547 48.405 37.817 ;
     RECT  51.015 37.547 51.105 37.817 ;
     RECT  53.715 37.547 53.805 37.817 ;
     RECT  56.415 37.547 56.505 37.817 ;
     RECT  59.115 37.589 59.205 37.817 ;
     RECT  61.815 37.625 61.905 37.817 ;
     RECT  66.6 37.661 67.305 37.817 ;
     RECT  69.915 37.565 70.005 37.817 ;
     RECT  72.615 37.547 72.705 37.817 ;
     RECT  75.315 37.547 75.405 37.817 ;
     RECT  78.015 37.613 78.105 37.817 ;
     RECT  80.715 37.589 81.27 37.817 ;
     RECT  83.415 37.565 83.505 37.817 ;
     RECT  86.115 37.565 86.205 37.817 ;
     RECT  126.615 37.547 126.705 37.817 ;
     RECT  129.315 37.547 129.405 37.817 ;
     RECT  132.015 37.589 132.105 37.817 ;
     RECT  134.715 37.547 134.805 37.817 ;
     RECT  137.415 37.547 137.505 37.817 ;
     RECT  140.115 37.547 140.205 37.817 ;
     RECT  142.815 37.547 142.905 37.817 ;
     RECT  145.515 37.547 145.605 37.817 ;
     RECT  148.215 37.589 148.305 37.817 ;
     RECT  150.915 37.547 151.005 37.817 ;
     RECT  153.615 37.547 153.705 37.817 ;
     RECT  156.315 37.547 156.405 37.817 ;
     RECT  159.015 37.625 159.105 37.817 ;
     RECT  161.715 37.547 161.805 37.817 ;
     RECT  164.415 37.547 164.505 37.817 ;
     RECT  167.115 37.597 167.85 37.817 ;
     RECT  169.815 37.547 169.905 37.817 ;
     RECT  172.515 37.547 172.605 37.817 ;
     RECT  105.015 2.413 105.297 37.831 ;
     RECT  40.68 37.817 41.022 37.895 ;
     RECT  102.315 2.413 102.597 37.903 ;
     RECT  42.3 37.625 43.254 37.931 ;
     RECT  105.015 37.831 105.318 37.931 ;
     RECT  102.315 37.903 102.618 38.003 ;
     RECT  5.115 37.049 26.997 38.011 ;
     RECT  27.828 37.769 38.07 38.011 ;
     RECT  104.148 37.975 104.166 38.011 ;
     RECT  104.148 38.011 104.274 38.129 ;
     RECT  167.832 37.817 167.85 38.137 ;
     RECT  5.115 38.011 38.07 38.165 ;
     RECT  5.115 38.165 33.354 38.201 ;
     RECT  39.168 37.817 39.582 38.201 ;
     RECT  34.092 38.165 37.797 38.273 ;
     RECT  2.415 36.239 2.697 38.281 ;
     RECT  106.632 37.975 106.65 38.281 ;
     RECT  5.115 38.201 22.806 38.309 ;
     RECT  99.252 37.741 99.897 38.309 ;
     RECT  104.148 38.129 104.166 38.309 ;
     RECT  106.56 38.281 106.65 38.309 ;
     RECT  2.304 38.281 2.697 38.399 ;
     RECT  3.42 38.173 3.978 38.399 ;
     RECT  106.56 38.309 106.578 38.399 ;
     RECT  64.404 37.589 65.322 38.471 ;
     RECT  21.096 38.309 22.806 38.525 ;
     RECT  40.68 37.895 40.698 38.543 ;
     RECT  2.415 38.399 2.697 38.551 ;
     RECT  202.215 2.413 202.497 38.551 ;
     RECT  203.256 38.281 203.274 38.551 ;
     RECT  3.96 38.399 3.978 38.579 ;
     RECT  210.315 34.889 210.597 38.641 ;
     RECT  211.464 38.551 211.482 38.641 ;
     RECT  2.415 38.551 2.862 38.669 ;
     RECT  21.096 38.525 22.554 38.669 ;
     RECT  210.315 38.641 211.482 38.669 ;
     RECT  0.216 38.347 0.234 38.741 ;
     RECT  214.344 38.683 214.362 38.741 ;
     RECT  213.015 36.041 213.297 38.779 ;
     RECT  81.252 37.817 81.27 38.821 ;
     RECT  212.4 38.779 213.297 38.821 ;
     RECT  212.04 38.821 213.297 38.939 ;
     RECT  5.115 38.309 20.142 38.975 ;
     RECT  212.04 38.939 212.238 38.975 ;
     RECT  91.515 37.319 91.797 39.019 ;
     RECT  42.3 37.931 42.714 39.047 ;
     RECT  23.616 38.201 33.354 39.055 ;
     RECT  34.164 38.273 37.797 39.055 ;
     RECT  6.336 38.975 20.142 39.091 ;
     RECT  21.096 38.669 22.446 39.091 ;
     RECT  106.092 38.515 106.11 39.119 ;
     RECT  210.315 38.669 210.942 39.119 ;
     RECT  212.076 38.975 212.238 39.209 ;
     RECT  23.616 39.055 37.797 39.211 ;
     RECT  6.336 39.091 22.446 39.281 ;
     RECT  212.076 39.209 212.094 39.293 ;
     RECT  42.444 39.047 42.714 39.353 ;
     RECT  23.58 39.211 37.797 39.361 ;
     RECT  6.336 39.281 19.422 39.479 ;
     RECT  90.864 39.019 91.797 39.595 ;
     RECT  42.444 39.353 42.642 39.623 ;
     RECT  65.088 38.471 65.322 39.659 ;
     RECT  20.16 39.281 22.446 39.757 ;
     RECT  23.364 39.361 37.797 39.757 ;
     RECT  20.16 39.757 37.797 39.785 ;
     RECT  6.336 39.479 19.242 39.821 ;
     RECT  110.415 27.743 110.697 39.901 ;
     RECT  15.3 39.821 19.242 40.019 ;
     RECT  15.3 40.019 19.134 40.091 ;
     RECT  98.424 16.807 98.442 40.171 ;
     RECT  99.54 38.309 99.897 40.171 ;
     RECT  66.6 37.817 66.618 40.199 ;
     RECT  80.964 38.821 81.27 40.199 ;
     RECT  17.676 40.091 19.134 40.289 ;
     RECT  20.34 39.785 37.797 40.361 ;
     RECT  6.336 39.821 14.562 40.441 ;
     RECT  5.115 38.975 5.397 40.531 ;
     RECT  6.192 40.441 14.562 40.531 ;
     RECT  2.415 38.669 2.697 40.567 ;
     RECT  5.115 40.531 14.562 40.711 ;
     RECT  15.3 40.091 16.902 40.711 ;
     RECT  96.915 2.413 97.197 40.711 ;
     RECT  5.115 40.711 16.902 40.829 ;
     RECT  17.748 40.289 19.134 40.843 ;
     RECT  17.748 40.843 19.566 40.865 ;
     RECT  6.336 40.829 16.902 40.901 ;
     RECT  121.215 34.259 121.497 40.909 ;
     RECT  90.864 39.595 92.286 40.945 ;
     RECT  93.708 35.041 94.497 40.981 ;
     RECT  120.492 40.909 121.497 40.981 ;
     RECT  0.54 40.843 0.558 41.009 ;
     RECT  6.66 40.901 16.197 41.009 ;
     RECT  90.864 40.945 92.538 41.071 ;
     RECT  93.708 40.981 94.626 41.071 ;
     RECT  96.915 40.711 97.506 41.071 ;
     RECT  98.424 40.171 99.897 41.071 ;
     RECT  115.815 2.413 116.097 41.071 ;
     RECT  20.988 40.361 37.797 41.099 ;
     RECT  90.864 41.071 94.626 41.099 ;
     RECT  115.815 41.071 116.334 41.143 ;
     RECT  117.684 41.071 117.702 41.143 ;
     RECT  118.515 33.539 118.797 41.143 ;
     RECT  115.815 41.143 117.702 41.179 ;
     RECT  118.44 41.143 118.797 41.179 ;
     RECT  120.492 40.981 121.806 41.179 ;
     RECT  96.915 41.071 99.897 41.215 ;
     RECT  119.916 41.179 121.806 41.215 ;
     RECT  20.988 41.099 29.898 41.243 ;
     RECT  20.988 41.243 29.826 41.251 ;
     RECT  115.815 41.179 118.797 41.251 ;
     RECT  119.52 41.215 121.806 41.251 ;
     RECT  210.315 39.119 210.597 41.251 ;
     RECT  18.36 40.865 19.566 41.323 ;
     RECT  20.88 41.251 29.826 41.323 ;
     RECT  91.515 41.099 94.626 41.341 ;
     RECT  65.088 39.659 65.106 41.369 ;
     RECT  90.756 41.215 90.774 41.369 ;
     RECT  210.315 41.251 211.302 41.369 ;
     RECT  42.444 39.623 42.462 41.377 ;
     RECT  115.815 41.251 121.806 41.377 ;
     RECT  2.304 40.567 2.697 41.405 ;
     RECT  91.515 41.341 95.094 41.405 ;
     RECT  96.732 41.215 99.897 41.413 ;
     RECT  213.015 38.939 213.297 41.419 ;
     RECT  96.444 41.413 99.897 41.441 ;
     RECT  93.024 41.405 95.094 41.449 ;
     RECT  96.444 41.441 97.65 41.449 ;
     RECT  91.515 41.405 92.286 41.477 ;
     RECT  90.648 41.377 90.666 41.513 ;
     RECT  213.015 41.419 213.786 41.513 ;
     RECT  115.815 41.377 122.202 41.521 ;
     RECT  123.12 41.071 123.138 41.521 ;
     RECT  123.915 21.389 124.197 41.521 ;
     RECT  30.78 41.099 37.797 41.611 ;
     RECT  212.004 41.521 212.022 41.675 ;
     RECT  196.815 36.797 197.097 41.707 ;
     RECT  30.78 41.611 37.854 41.719 ;
     RECT  210.315 41.369 210.942 41.747 ;
     RECT  196.128 41.707 197.097 41.909 ;
     RECT  110.415 39.901 111.294 41.947 ;
     RECT  177.915 36.893 178.197 41.947 ;
     RECT  114.552 41.947 114.57 41.995 ;
     RECT  188.715 36.797 188.997 42.043 ;
     RECT  107.715 33.449 107.997 42.061 ;
     RECT  177.915 41.947 178.434 42.077 ;
     RECT  93.024 41.449 97.65 42.089 ;
     RECT  110.376 41.947 111.294 42.089 ;
     RECT  188.604 42.043 188.997 42.089 ;
     RECT  196.704 41.909 197.097 42.089 ;
     RECT  195.84 42.061 195.858 42.125 ;
     RECT  87.732 39.829 87.75 42.151 ;
     RECT  102.315 38.003 102.597 42.151 ;
     RECT  93.024 42.089 95.778 42.187 ;
     RECT  107.715 42.061 108.27 42.187 ;
     RECT  113.115 28.823 113.598 42.187 ;
     RECT  114.552 41.995 115.038 42.187 ;
     RECT  113.115 42.187 115.038 42.223 ;
     RECT  115.815 41.521 124.197 42.223 ;
     RECT  98.424 41.441 99.897 42.235 ;
     RECT  42.444 41.377 42.534 42.259 ;
     RECT  101.016 42.187 101.034 42.259 ;
     RECT  7.056 41.009 16.197 42.283 ;
     RECT  30.78 41.719 37.926 42.295 ;
     RECT  96.915 42.089 97.65 42.295 ;
     RECT  98.388 42.235 99.897 42.295 ;
     RECT  100.908 42.259 101.034 42.331 ;
     RECT  107.715 42.187 108.306 42.331 ;
     RECT  87.732 42.151 87.786 42.421 ;
     RECT  88.815 2.413 89.097 42.421 ;
     RECT  126.792 42.259 126.81 42.421 ;
     RECT  30.744 42.295 37.926 42.427 ;
     RECT  113.115 42.223 124.197 42.427 ;
     RECT  18.36 41.323 29.826 42.493 ;
     RECT  30.564 42.427 37.926 42.493 ;
     RECT  174.42 41.947 174.438 42.493 ;
     RECT  81.252 40.199 81.27 42.529 ;
     RECT  129.096 42.457 129.114 42.529 ;
     RECT  174.204 42.493 174.438 42.529 ;
     RECT  81.252 42.529 81.774 42.565 ;
     RECT  105.015 37.931 105.297 42.565 ;
     RECT  106.056 42.457 106.146 42.565 ;
     RECT  174.168 42.529 174.438 42.565 ;
     RECT  101.916 42.151 102.597 42.571 ;
     RECT  103.644 41.791 103.662 42.571 ;
     RECT  41.292 40.171 41.31 42.601 ;
     RECT  42.444 42.259 42.606 42.601 ;
     RECT  105.015 42.565 106.146 42.601 ;
     RECT  107.715 42.331 108.954 42.601 ;
     RECT  110.415 42.089 111.294 42.601 ;
     RECT  167.832 38.137 167.886 42.601 ;
     RECT  90.648 42.529 90.666 42.629 ;
     RECT  87.732 42.421 89.097 42.701 ;
     RECT  113.115 42.427 124.29 42.727 ;
     RECT  105.015 42.601 108.954 42.763 ;
     RECT  186.015 2.413 186.297 42.763 ;
     RECT  196.815 42.089 197.097 42.763 ;
     RECT  101.916 42.571 103.662 42.799 ;
     RECT  104.616 42.763 108.954 42.799 ;
     RECT  92.952 42.187 95.778 42.827 ;
     RECT  188.715 42.089 188.997 42.859 ;
     RECT  95.976 42.835 95.994 42.871 ;
     RECT  96.915 42.295 99.897 42.871 ;
     RECT  100.908 42.331 101.07 42.871 ;
     RECT  101.916 42.799 108.954 42.871 ;
     RECT  174.096 42.565 174.438 42.893 ;
     RECT  177.915 42.077 178.29 42.893 ;
     RECT  182.412 42.763 182.43 42.893 ;
     RECT  186.015 42.763 186.39 42.893 ;
     RECT  190.404 41.947 190.422 42.893 ;
     RECT  196.815 42.763 197.19 42.893 ;
     RECT  198.36 41.947 198.378 42.893 ;
     RECT  100.908 42.871 108.954 42.899 ;
     RECT  188.715 42.859 189.09 42.899 ;
     RECT  95.976 42.871 99.897 42.989 ;
     RECT  110.415 42.601 111.33 42.997 ;
     RECT  112.176 42.871 112.194 42.997 ;
     RECT  204.915 24.509 205.197 43.003 ;
     RECT  18.36 42.493 37.926 43.033 ;
     RECT  109.728 42.997 112.194 43.033 ;
     RECT  113.115 42.727 124.542 43.033 ;
     RECT  2.415 41.405 2.697 43.141 ;
     RECT  18.36 43.033 38.07 43.169 ;
     RECT  41.292 42.601 42.606 43.2 ;
     RECT  62.676 42.475 62.694 43.2 ;
     RECT  81.252 42.565 81.846 43.2 ;
     RECT  128.844 42.529 129.114 43.2 ;
     RECT  167.004 42.571 167.022 43.2 ;
     RECT  167.832 42.601 167.922 43.2 ;
     RECT  204.624 43.003 205.197 43.259 ;
     RECT  6.408 42.283 16.197 43.277 ;
     RECT  202.215 38.551 203.85 43.291 ;
     RECT  101.304 42.899 108.954 43.303 ;
     RECT  109.728 43.033 124.542 43.303 ;
     RECT  6.408 43.277 14.454 43.331 ;
     RECT  202.215 43.291 203.886 43.331 ;
     RECT  2.415 43.141 3.114 43.387 ;
     RECT  91.515 41.477 91.797 43.411 ;
     RECT  2.268 43.387 3.114 43.439 ;
     RECT  18.36 43.169 37.998 43.573 ;
     RECT  91.515 43.411 91.854 43.645 ;
     RECT  92.952 42.827 95.166 43.645 ;
     RECT  2.415 43.439 3.114 43.681 ;
     RECT  96.192 42.989 99.897 43.681 ;
     RECT  101.304 43.303 124.542 43.681 ;
     RECT  91.515 43.645 95.382 43.771 ;
     RECT  96.192 43.681 124.542 43.771 ;
     RECT  2.415 43.681 3.654 43.799 ;
     RECT  15.48 43.277 16.197 43.799 ;
     RECT  87.732 42.701 87.786 43.799 ;
     RECT  86.976 43.771 86.994 43.843 ;
     RECT  3.42 43.799 3.438 43.871 ;
     RECT  39.564 38.201 39.582 43.871 ;
     RECT  91.515 43.771 124.542 43.871 ;
     RECT  207.615 36.173 207.897 43.915 ;
     RECT  91.515 43.871 99.897 43.943 ;
     RECT  169.848 43.609 169.866 43.997 ;
     RECT  174.096 42.893 174.222 44.069 ;
     RECT  125.928 43.843 125.946 44.093 ;
     RECT  17.928 43.573 37.998 44.141 ;
     RECT  100.764 43.871 124.542 44.189 ;
     RECT  41.292 43.2 81.846 44.213 ;
     RECT  213.015 41.513 213.297 44.221 ;
     RECT  169.884 44.041 170.442 44.249 ;
     RECT  86.796 43.843 86.994 44.339 ;
     RECT  87.732 43.799 87.75 44.339 ;
     RECT  169.884 44.249 169.902 44.339 ;
     RECT  174.204 44.069 174.222 44.339 ;
     RECT  208.872 44.221 208.89 44.339 ;
     RECT  212.508 44.221 213.297 44.339 ;
     RECT  23.796 44.141 37.998 44.347 ;
     RECT  38.772 43.807 38.79 44.347 ;
     RECT  210.315 41.747 210.597 44.347 ;
     RECT  86.796 44.339 86.814 44.375 ;
     RECT  173.196 43.531 173.214 44.375 ;
     RECT  207.615 43.915 207.954 44.381 ;
     RECT  209.772 44.347 210.597 44.383 ;
     RECT  212.58 44.339 213.297 44.411 ;
     RECT  16.92 42.061 16.938 44.419 ;
     RECT  17.928 44.141 23.058 44.419 ;
     RECT  7.2 43.331 14.454 44.609 ;
     RECT  23.796 44.347 38.79 44.609 ;
     RECT  7.2 44.609 8.442 44.621 ;
     RECT  209.772 44.383 210.942 44.645 ;
     RECT  41.292 44.213 81.774 44.689 ;
     RECT  41.04 44.689 81.774 44.753 ;
     RECT  126.792 42.421 126.882 44.765 ;
     RECT  209.772 44.645 210.597 44.789 ;
     RECT  91.515 43.943 91.89 44.851 ;
     RECT  92.628 43.943 99.897 44.851 ;
     RECT  30.564 44.609 38.79 44.861 ;
     RECT  126.864 44.765 126.882 44.861 ;
     RECT  30.564 44.861 38.682 44.879 ;
     RECT  120.168 44.189 124.542 44.879 ;
     RECT  30.564 44.879 33.174 44.915 ;
     RECT  16.92 44.419 23.058 44.987 ;
     RECT  15.915 43.799 16.197 44.995 ;
     RECT  16.92 44.987 19.098 44.995 ;
     RECT  91.515 44.851 99.897 44.995 ;
     RECT  91.515 44.995 99.99 45.023 ;
     RECT  19.836 44.987 23.058 45.031 ;
     RECT  23.796 44.609 29.754 45.031 ;
     RECT  94.176 45.023 99.99 45.053 ;
     RECT  94.215 45.053 99.99 45.121 ;
     RECT  100.764 44.189 119.394 45.121 ;
     RECT  91.515 45.023 93.438 45.149 ;
     RECT  90.648 45.019 90.666 45.197 ;
     RECT  94.215 45.121 119.394 45.301 ;
     RECT  127.116 45.229 127.134 45.301 ;
     RECT  19.836 45.031 29.754 45.329 ;
     RECT  92.592 45.149 92.97 45.329 ;
     RECT  127.116 45.301 127.71 45.391 ;
     RECT  128.844 43.2 167.922 45.391 ;
     RECT  33.912 44.879 38.682 45.419 ;
     RECT  92.952 45.329 92.97 45.419 ;
     RECT  120.816 44.879 124.542 45.437 ;
     RECT  9.18 44.609 14.454 45.451 ;
     RECT  20.808 45.329 29.754 45.455 ;
     RECT  30.564 44.915 32.526 45.455 ;
     RECT  8.928 45.451 14.454 45.491 ;
     RECT  19.836 45.329 20.034 45.527 ;
     RECT  20.808 45.455 27.99 45.527 ;
     RECT  120.888 45.437 124.542 45.527 ;
     RECT  94.215 45.301 119.754 45.533 ;
     RECT  127.116 45.391 167.922 45.533 ;
     RECT  28.728 45.455 29.754 45.547 ;
     RECT  30.564 45.455 31.158 45.547 ;
     RECT  28.728 45.547 31.158 45.563 ;
     RECT  28.944 45.563 31.158 45.599 ;
     RECT  95.22 45.533 119.754 45.599 ;
     RECT  41.04 44.753 81.216 45.629 ;
     RECT  127.116 45.533 128.286 45.629 ;
     RECT  33.912 45.419 37.998 45.661 ;
     RECT  31.896 45.455 32.526 45.691 ;
     RECT  33.408 45.661 37.998 45.691 ;
     RECT  20.88 45.527 27.99 45.725 ;
     RECT  95.22 45.599 118.89 45.725 ;
     RECT  127.116 45.629 127.134 45.725 ;
     RECT  31.896 45.691 37.998 45.731 ;
     RECT  28.944 45.599 30.654 45.797 ;
     RECT  2.415 43.799 2.697 45.883 ;
     RECT  3.492 44.923 3.51 45.931 ;
     RECT  5.115 40.829 5.397 45.931 ;
     RECT  20.88 45.725 27.702 45.959 ;
     RECT  31.896 45.731 32.526 45.959 ;
     RECT  33.408 45.731 37.998 45.959 ;
     RECT  20.88 45.959 21.798 45.995 ;
     RECT  119.7 45.599 119.754 46.003 ;
     RECT  38.736 45.733 38.898 46.031 ;
     RECT  2.304 45.883 2.697 46.039 ;
     RECT  3.492 45.931 3.762 46.039 ;
     RECT  4.5 45.931 5.397 46.039 ;
     RECT  121.032 45.527 124.542 46.067 ;
     RECT  22.608 45.959 27.378 46.103 ;
     RECT  119.7 46.003 119.898 46.103 ;
     RECT  28.944 45.797 29.862 46.139 ;
     RECT  38.736 46.031 38.826 46.139 ;
     RECT  119.88 46.103 119.898 46.139 ;
     RECT  95.724 45.725 118.89 46.157 ;
     RECT  95.724 46.157 118.854 46.229 ;
     RECT  23.04 46.103 27.378 46.265 ;
     RECT  34.128 45.959 37.998 46.273 ;
     RECT  38.736 46.139 38.754 46.273 ;
     RECT  23.94 46.265 27.378 46.301 ;
     RECT  96.156 46.229 117.09 46.337 ;
     RECT  98.352 46.337 117.09 46.349 ;
     RECT  96.156 46.337 97.506 46.373 ;
     RECT  128.268 45.629 128.286 46.381 ;
     RECT  129.276 45.533 167.922 46.381 ;
     RECT  34.128 46.273 38.754 46.397 ;
     RECT  2.304 46.039 5.397 46.409 ;
     RECT  31.896 45.959 32.454 46.409 ;
     RECT  96.156 46.373 97.197 46.409 ;
     RECT  23.04 46.265 23.058 46.499 ;
     RECT  28.944 46.139 29.697 46.499 ;
     RECT  98.46 46.349 117.09 46.499 ;
     RECT  23.94 46.301 26.997 46.535 ;
     RECT  96.372 46.409 97.197 46.535 ;
     RECT  25.236 46.535 26.997 46.571 ;
     RECT  98.46 46.499 116.982 46.571 ;
     RECT  15.915 44.995 19.098 46.651 ;
     RECT  19.836 45.527 19.854 46.651 ;
     RECT  15.915 46.651 19.854 46.679 ;
     RECT  23.94 46.535 24.297 46.679 ;
     RECT  25.812 46.571 26.997 46.679 ;
     RECT  30.78 46.381 30.798 46.679 ;
     RECT  6.408 43.331 6.426 46.741 ;
     RECT  26.028 46.679 26.997 46.769 ;
     RECT  128.268 46.381 167.922 46.781 ;
     RECT  3.492 46.409 5.397 46.805 ;
     RECT  26.244 46.769 26.997 46.805 ;
     RECT  4.536 46.805 5.397 46.841 ;
     RECT  15.915 46.679 19.782 46.843 ;
     RECT  31.14 46.747 31.158 46.849 ;
     RECT  31.896 46.409 32.397 46.849 ;
     RECT  15.516 46.843 19.782 46.883 ;
     RECT  128.808 46.781 167.922 46.913 ;
     RECT  6.3 46.741 6.426 46.921 ;
     RECT  34.128 46.397 38.178 46.987 ;
     RECT  3.492 46.805 3.762 47.039 ;
     RECT  31.14 46.849 32.397 47.039 ;
     RECT  33.372 46.987 38.178 47.039 ;
     RECT  198.36 46.885 198.378 47.039 ;
     RECT  119.952 46.849 119.97 47.047 ;
     RECT  31.14 47.039 31.158 47.075 ;
     RECT  6.3 46.921 6.462 47.111 ;
     RECT  128.808 46.913 167.85 47.111 ;
     RECT  214.308 46.939 214.326 47.111 ;
     RECT  34.488 47.039 38.178 47.191 ;
     RECT  117.9 46.229 118.854 47.191 ;
     RECT  206.424 47.083 206.442 47.191 ;
     RECT  206.352 47.191 206.442 47.219 ;
     RECT  119.952 47.047 120.042 47.272 ;
     RECT  119.844 47.272 120.042 47.275 ;
     RECT  117.9 47.191 119.07 47.281 ;
     RECT  119.844 47.275 120.474 47.281 ;
     RECT  209.124 47.047 209.142 47.281 ;
     RECT  5.04 46.841 5.397 47.309 ;
     RECT  98.964 46.571 116.982 47.309 ;
     RECT  121.215 46.067 124.542 47.309 ;
     RECT  126.504 47.191 126.522 47.309 ;
     RECT  206.352 47.219 206.37 47.309 ;
     RECT  209.052 47.281 209.142 47.309 ;
     RECT  98.964 47.309 116.097 47.317 ;
     RECT  98.856 47.317 116.097 47.345 ;
     RECT  98.856 47.345 111.762 47.357 ;
     RECT  116.964 47.309 116.982 47.357 ;
     RECT  117.828 47.281 120.474 47.371 ;
     RECT  121.215 47.309 122.166 47.371 ;
     RECT  117.828 47.371 122.166 47.405 ;
     RECT  9.216 45.491 14.454 47.461 ;
     RECT  118.008 47.405 122.166 47.501 ;
     RECT  9.216 47.461 14.634 47.551 ;
     RECT  34.488 47.191 38.214 47.579 ;
     RECT  9.216 47.551 14.922 47.597 ;
     RECT  128.268 47.587 128.286 47.645 ;
     RECT  119.7 47.501 122.166 47.651 ;
     RECT  6.372 47.111 6.462 47.731 ;
     RECT  7.2 44.621 8.097 47.731 ;
     RECT  123.084 47.309 124.542 47.731 ;
     RECT  126.54 47.623 126.558 47.741 ;
     RECT  9.216 47.597 14.742 47.849 ;
     RECT  33.516 47.039 33.678 47.849 ;
     RECT  34.488 47.579 35.154 47.849 ;
     RECT  120.96 47.651 122.166 47.849 ;
     RECT  123.084 47.731 124.902 47.849 ;
     RECT  3.492 47.039 3.51 47.857 ;
     RECT  9.216 47.849 14.634 47.885 ;
     RECT  33.516 47.849 33.534 47.885 ;
     RECT  118.008 47.501 118.797 47.885 ;
     RECT  99.144 47.357 111.762 47.933 ;
     RECT  34.776 47.849 35.154 48.029 ;
     RECT  36.432 47.579 38.214 48.029 ;
     RECT  123.915 47.849 124.902 48.029 ;
     RECT  36.432 48.029 37.797 48.119 ;
     RECT  99.252 47.933 111.762 48.119 ;
     RECT  36.432 48.119 36.45 48.155 ;
     RECT  119.7 47.651 120.186 48.155 ;
     RECT  3.492 47.857 4.014 48.199 ;
     RECT  100.98 48.119 111.762 48.271 ;
     RECT  112.5 47.345 116.097 48.271 ;
     RECT  3.492 48.199 4.122 48.299 ;
     RECT  2.415 46.409 2.697 48.361 ;
     RECT  3.492 48.299 4.014 48.361 ;
     RECT  6.372 47.731 8.097 48.361 ;
     RECT  2.415 48.361 4.014 48.389 ;
     RECT  99.252 48.119 100.206 48.389 ;
     RECT  100.98 48.271 116.097 48.389 ;
     RECT  120.024 48.155 120.186 48.389 ;
     RECT  120.96 47.849 121.59 48.389 ;
     RECT  122.544 48.271 122.562 48.389 ;
     RECT  103.644 48.389 106.542 48.425 ;
     RECT  112.32 48.389 113.397 48.425 ;
     RECT  120.024 48.389 120.042 48.425 ;
     RECT  5.076 47.309 5.397 48.461 ;
     RECT  99.615 48.389 100.206 48.461 ;
     RECT  101.448 48.389 102.798 48.461 ;
     RECT  103.644 48.425 105.297 48.461 ;
     RECT  106.056 48.425 106.542 48.461 ;
     RECT  107.715 48.389 111.186 48.461 ;
     RECT  112.752 48.425 113.397 48.461 ;
     RECT  114.876 48.389 116.097 48.461 ;
     RECT  5.115 48.461 5.397 48.475 ;
     RECT  6.264 48.361 8.097 48.475 ;
     RECT  2.415 48.389 3.51 48.541 ;
     RECT  121.215 48.389 121.59 48.631 ;
     RECT  2.304 48.541 3.51 48.659 ;
     RECT  129.312 47.111 167.85 48.659 ;
     RECT  101.592 48.461 102.798 48.695 ;
     RECT  104.688 48.461 105.297 48.695 ;
     RECT  106.056 48.461 106.398 48.695 ;
     RECT  112.788 48.461 113.397 48.695 ;
     RECT  121.215 48.631 122.166 48.731 ;
     RECT  5.115 48.475 8.097 48.803 ;
     RECT  112.824 48.695 113.397 48.839 ;
     RECT  122.94 48.631 122.958 48.839 ;
     RECT  6.912 48.803 8.097 48.929 ;
     RECT  107.715 48.461 110.697 48.929 ;
     RECT  2.415 48.659 3.51 49.001 ;
     RECT  107.715 48.929 109.026 49.001 ;
     RECT  110.016 48.929 110.697 49.001 ;
     RECT  9.216 47.885 14.454 49.235 ;
     RECT  211.752 46.921 211.77 49.579 ;
     RECT  213.015 44.411 213.297 49.579 ;
     RECT  214.344 49.675 214.362 49.811 ;
     RECT  3.492 49.001 3.51 49.855 ;
     RECT  7.2 48.929 8.097 49.855 ;
     RECT  211.752 49.579 213.297 49.891 ;
     RECT  129.6 48.659 167.85 49.919 ;
     RECT  6.84 49.855 8.097 50.009 ;
     RECT  202.215 43.331 203.85 50.017 ;
     RECT  211.752 49.891 213.354 50.045 ;
     RECT  212.616 50.045 213.354 50.315 ;
     RECT  212.616 50.315 213.297 50.459 ;
     RECT  9.324 49.235 14.454 50.791 ;
     RECT  9.324 50.791 14.562 50.819 ;
     RECT  7.2 50.009 8.097 50.863 ;
     RECT  2.415 49.001 2.697 50.899 ;
     RECT  0.216 50.791 0.234 50.957 ;
     RECT  2.412 50.899 2.697 50.971 ;
     RECT  3.492 49.855 4.086 50.971 ;
     RECT  6.3 50.731 6.318 50.971 ;
     RECT  7.2 50.863 8.586 50.971 ;
     RECT  9.324 50.819 13.734 50.971 ;
     RECT  6.3 50.971 6.462 51.089 ;
     RECT  2.412 50.971 4.086 51.125 ;
     RECT  6.3 51.089 6.318 51.149 ;
     RECT  7.2 50.971 13.734 51.161 ;
     RECT  2.415 51.125 4.086 51.359 ;
     RECT  7.272 51.161 13.734 51.359 ;
     RECT  7.815 51.359 13.734 51.539 ;
     RECT  210.315 44.789 210.597 51.883 ;
     RECT  9.576 51.539 13.734 52.051 ;
     RECT  14.544 50.819 14.562 52.051 ;
     RECT  211.752 50.045 211.77 52.169 ;
     RECT  210.315 51.883 210.762 52.205 ;
     RECT  7.815 51.539 8.586 52.285 ;
     RECT  9.576 52.051 14.562 52.285 ;
     RECT  7.815 52.285 14.562 52.321 ;
     RECT  213.015 50.459 213.297 52.321 ;
     RECT  211.932 52.321 213.297 52.439 ;
     RECT  212.58 52.439 213.297 52.459 ;
     RECT  212.58 52.459 213.75 52.511 ;
     RECT  41.292 45.629 81.216 52.583 ;
     RECT  212.58 52.511 213.297 52.583 ;
     RECT  7.38 52.321 14.562 52.951 ;
     RECT  7.38 52.951 14.85 53.257 ;
     RECT  15.915 46.883 19.782 53.257 ;
     RECT  209.052 47.309 209.07 53.293 ;
     RECT  0.216 53.467 0.234 53.519 ;
     RECT  7.38 53.257 19.782 53.591 ;
     RECT  2.415 51.359 2.697 53.635 ;
     RECT  3.492 51.359 4.086 53.635 ;
     RECT  2.415 53.635 4.086 54.131 ;
     RECT  5.115 48.803 5.397 54.139 ;
     RECT  5.115 54.139 5.49 54.481 ;
     RECT  7.38 53.591 15.03 54.481 ;
     RECT  5.115 54.481 5.67 54.571 ;
     RECT  7.38 54.481 15.066 54.599 ;
     RECT  6.444 54.607 6.714 54.707 ;
     RECT  4.824 54.571 5.67 54.715 ;
     RECT  6.444 54.707 6.462 54.715 ;
     RECT  207.615 44.381 207.897 54.715 ;
     RECT  208.728 53.293 209.07 54.715 ;
     RECT  207.615 54.715 209.07 54.869 ;
     RECT  207.615 54.869 208.746 54.905 ;
     RECT  210.315 52.205 210.597 55.021 ;
     RECT  213.015 52.583 213.297 55.021 ;
     RECT  210.315 55.021 210.834 55.139 ;
     RECT  212.904 55.021 213.297 55.139 ;
     RECT  212.976 55.139 213.297 55.211 ;
     RECT  7.815 54.599 15.066 55.219 ;
     RECT  214.308 55.183 214.326 55.229 ;
     RECT  3.492 54.131 4.086 55.867 ;
     RECT  4.824 54.715 6.462 55.867 ;
     RECT  2.415 54.131 2.697 55.921 ;
     RECT  7.815 55.219 15.138 55.993 ;
     RECT  15.915 53.591 19.782 55.993 ;
     RECT  0.216 56.011 0.234 56.057 ;
     RECT  3.492 55.867 6.462 56.129 ;
     RECT  3.492 56.129 5.526 56.219 ;
     RECT  2.376 55.921 2.697 56.255 ;
     RECT  2.415 56.255 2.697 56.263 ;
     RECT  3.492 56.219 4.374 56.263 ;
     RECT  6.444 56.129 6.462 56.299 ;
     RECT  6.444 56.299 6.75 56.327 ;
     RECT  2.415 56.263 4.374 56.363 ;
     RECT  201.24 32.999 201.258 56.488 ;
     RECT  2.415 56.363 4.086 56.489 ;
     RECT  5.115 56.219 5.526 56.489 ;
     RECT  115.056 48.461 116.097 56.489 ;
     RECT  200.52 56.488 201.258 56.525 ;
     RECT  200.88 56.525 201.258 56.717 ;
     RECT  7.815 55.993 19.782 57.443 ;
     RECT  3.492 56.489 4.086 57.451 ;
     RECT  10.044 57.443 19.782 57.451 ;
     RECT  10.044 57.451 19.962 57.569 ;
     RECT  105.015 48.695 105.297 57.595 ;
     RECT  106.056 48.695 106.074 57.595 ;
     RECT  213.015 55.211 213.297 57.721 ;
     RECT  105.015 57.595 106.074 57.839 ;
     RECT  208.728 54.905 208.746 57.839 ;
     RECT  212.976 57.721 213.297 57.839 ;
     RECT  105.015 57.839 105.93 57.875 ;
     RECT  214.344 57.919 214.362 57.965 ;
     RECT  2.415 56.489 2.697 58.081 ;
     RECT  103.644 48.461 103.806 58.109 ;
     RECT  6.732 56.327 6.75 58.123 ;
     RECT  103.644 58.109 103.662 58.145 ;
     RECT  6.192 58.123 6.75 58.189 ;
     RECT  7.815 57.443 8.622 58.189 ;
     RECT  6.192 58.189 8.622 58.217 ;
     RECT  10.368 57.569 19.962 58.487 ;
     RECT  6.192 58.217 8.586 58.523 ;
     RECT  1.728 58.081 2.697 58.531 ;
     RECT  3.492 57.451 4.23 58.531 ;
     RECT  1.728 58.531 4.23 58.541 ;
     RECT  10.368 58.487 14.814 58.649 ;
     RECT  2.412 58.541 4.23 58.685 ;
     RECT  10.368 58.649 13.806 58.685 ;
     RECT  14.796 58.649 14.814 58.685 ;
     RECT  2.415 58.685 4.23 58.721 ;
     RECT  6.732 58.523 8.586 58.721 ;
     RECT  15.588 58.487 19.962 58.721 ;
     RECT  10.368 58.685 13.497 59.063 ;
     RECT  41.292 52.583 42.462 59.189 ;
     RECT  107.715 49.001 108.954 59.459 ;
     RECT  107.715 59.459 108.702 59.495 ;
     RECT  10.368 59.063 12.33 59.803 ;
     RECT  13.104 59.063 13.497 59.803 ;
     RECT  10.368 59.803 13.497 59.843 ;
     RECT  101.592 48.695 102.597 60.427 ;
     RECT  2.415 58.721 2.697 60.511 ;
     RECT  206.352 60.421 206.37 60.539 ;
     RECT  211.356 60.421 211.374 60.539 ;
     RECT  6.732 58.721 6.75 60.611 ;
     RECT  7.815 58.721 8.586 60.647 ;
     RECT  213.015 57.839 213.297 60.655 ;
     RECT  7.815 60.647 8.19 60.691 ;
     RECT  6.948 60.691 8.19 60.809 ;
     RECT  101.34 60.427 102.597 60.809 ;
     RECT  212.4 60.655 213.297 60.809 ;
     RECT  101.34 60.809 101.358 60.845 ;
     RECT  214.344 60.667 214.362 60.953 ;
     RECT  1.728 60.511 2.697 60.961 ;
     RECT  3.456 58.721 4.23 60.961 ;
     RECT  6.948 60.809 6.966 60.989 ;
     RECT  1.728 60.961 4.23 61.037 ;
     RECT  198.36 61.051 198.378 61.181 ;
     RECT  202.215 50.017 203.886 61.181 ;
     RECT  2.415 61.037 4.23 61.349 ;
     RECT  7.815 60.809 8.19 62.509 ;
     RECT  7.815 62.509 8.622 62.779 ;
     RECT  7.815 62.779 8.766 62.815 ;
     RECT  7.815 62.815 9.198 62.969 ;
     RECT  201.24 56.717 201.258 62.969 ;
     RECT  203.256 61.181 203.886 63.049 ;
     RECT  204.915 43.259 205.197 63.049 ;
     RECT  7.815 62.969 9.09 63.355 ;
     RECT  7.812 63.355 9.09 63.383 ;
     RECT  2.415 61.349 2.697 63.391 ;
     RECT  180.615 2.413 180.897 63.499 ;
     RECT  9.072 63.383 9.09 63.509 ;
     RECT  2.304 63.391 2.697 63.517 ;
     RECT  3.456 61.349 4.23 63.517 ;
     RECT  180.54 63.499 180.897 63.545 ;
     RECT  214.236 63.451 214.254 63.581 ;
     RECT  210.315 55.139 210.597 63.625 ;
     RECT  7.812 63.383 8.097 63.629 ;
     RECT  180.615 63.545 180.897 63.661 ;
     RECT  213.015 60.809 213.297 63.661 ;
     RECT  0.216 63.547 0.234 63.689 ;
     RECT  2.304 63.517 4.23 63.689 ;
     RECT  180.615 63.661 181.026 63.725 ;
     RECT  2.304 63.689 2.697 63.779 ;
     RECT  210.315 63.625 211.302 63.779 ;
     RECT  203.256 63.049 205.197 63.787 ;
     RECT  203.22 63.787 205.197 63.851 ;
     RECT  212.796 63.661 213.297 63.851 ;
     RECT  210.315 63.779 210.597 65.245 ;
     RECT  3.456 63.689 4.23 65.785 ;
     RECT  5.115 56.489 5.397 65.785 ;
     RECT  7.815 63.629 8.097 65.785 ;
     RECT  3.456 65.785 5.397 65.821 ;
     RECT  2.415 63.779 2.697 65.911 ;
     RECT  3.456 65.821 5.922 65.911 ;
     RECT  2.415 65.911 5.922 65.939 ;
     RECT  7.815 65.785 8.802 66.019 ;
     RECT  0.216 66.091 0.234 66.128 ;
     RECT  10.368 59.843 12.33 66.181 ;
     RECT  209.232 63.625 209.25 66.181 ;
     RECT  210.315 65.245 210.654 66.181 ;
     RECT  213.015 63.851 213.297 66.187 ;
     RECT  209.232 66.181 210.654 66.209 ;
     RECT  7.596 66.019 8.802 66.217 ;
     RECT  9.576 65.245 9.594 66.217 ;
     RECT  209.232 66.209 210.597 66.221 ;
     RECT  2.415 65.939 5.598 66.245 ;
     RECT  7.596 66.217 9.594 66.269 ;
     RECT  41.292 59.189 41.31 66.281 ;
     RECT  213.015 66.187 213.678 66.281 ;
     RECT  9.576 66.269 9.594 66.289 ;
     RECT  10.332 66.181 12.33 66.289 ;
     RECT  122.508 66.139 122.526 66.451 ;
     RECT  2.415 66.245 5.397 66.479 ;
     RECT  122.508 66.451 122.634 66.509 ;
     RECT  122.508 66.509 122.526 66.515 ;
     RECT  9.576 66.289 12.33 66.551 ;
     RECT  10.08 66.551 12.33 66.785 ;
     RECT  3.456 66.479 5.397 66.797 ;
     RECT  7.596 66.269 8.802 66.857 ;
     RECT  7.596 66.857 8.694 66.941 ;
     RECT  2.415 66.479 2.697 68.341 ;
     RECT  3.456 66.797 4.23 68.341 ;
     RECT  10.296 66.785 12.33 68.377 ;
     RECT  5.115 66.797 5.397 68.449 ;
     RECT  10.26 68.377 12.33 68.449 ;
     RECT  6.48 68.449 6.498 68.521 ;
     RECT  7.596 66.941 8.097 68.521 ;
     RECT  0.216 68.587 0.234 68.639 ;
     RECT  5.004 68.449 5.397 68.639 ;
     RECT  9.9 68.449 12.33 68.639 ;
     RECT  6.48 68.521 8.097 68.719 ;
     RECT  6.12 68.719 8.097 68.783 ;
     RECT  207.615 54.905 207.897 68.875 ;
     RECT  207.615 68.875 208.35 68.881 ;
     RECT  6.12 68.783 6.714 68.909 ;
     RECT  10.26 68.639 12.33 68.909 ;
     RECT  209.232 66.221 209.25 68.909 ;
     RECT  213.015 66.281 213.297 68.923 ;
     RECT  6.12 68.909 6.138 68.981 ;
     RECT  213.015 68.923 213.75 68.981 ;
     RECT  207.615 68.881 208.494 69.005 ;
     RECT  212.22 68.923 212.238 69.089 ;
     RECT  2.415 68.341 4.23 69.485 ;
     RECT  7.596 68.783 8.097 70.681 ;
     RECT  7.596 70.681 8.478 70.843 ;
     RECT  10.332 68.909 12.33 70.915 ;
     RECT  5.115 68.639 5.397 70.951 ;
     RECT  6.624 70.915 6.642 70.951 ;
     RECT  5.115 70.951 6.642 71.069 ;
     RECT  6.48 71.069 6.498 71.075 ;
     RECT  7.416 70.843 8.658 71.105 ;
     RECT  2.415 69.485 2.697 71.113 ;
     RECT  3.456 69.485 4.23 71.113 ;
     RECT  0.216 71.083 0.234 71.177 ;
     RECT  2.415 71.113 4.23 71.221 ;
     RECT  7.416 71.105 8.478 71.375 ;
     RECT  2.304 71.221 4.23 71.609 ;
     RECT  210.315 66.221 210.597 71.725 ;
     RECT  214.344 71.659 214.362 71.753 ;
     RECT  210.315 71.725 211.122 71.761 ;
     RECT  212.04 71.467 212.058 71.761 ;
     RECT  213.015 68.981 213.297 71.761 ;
     RECT  210.315 71.761 213.297 71.789 ;
     RECT  2.415 71.609 4.23 71.879 ;
     RECT  211.464 71.789 213.297 71.879 ;
     RECT  212.184 71.879 213.297 71.915 ;
     RECT  212.184 71.915 212.202 72.059 ;
     RECT  7.815 71.375 8.478 73.579 ;
     RECT  2.415 71.879 2.697 73.627 ;
     RECT  3.456 71.879 4.23 73.627 ;
     RECT  7.815 73.579 9.198 73.651 ;
     RECT  6.84 73.579 6.858 73.679 ;
     RECT  10.296 70.915 12.33 73.841 ;
     RECT  10.296 73.841 10.89 73.849 ;
     RECT  10.26 73.849 10.89 73.885 ;
     RECT  2.415 73.627 4.23 74.039 ;
     RECT  10.116 73.885 10.89 74.039 ;
     RECT  7.815 73.651 9.342 74.119 ;
     RECT  7.668 74.119 9.342 74.183 ;
     RECT  7.668 74.183 9.198 74.309 ;
     RECT  210.315 71.789 210.597 74.539 ;
     RECT  209.988 74.539 210.597 74.551 ;
     RECT  213.015 71.915 213.297 74.587 ;
     RECT  209.988 74.551 210.942 74.615 ;
     RECT  206.352 74.443 206.37 74.621 ;
     RECT  210.315 74.615 210.942 74.621 ;
     RECT  214.344 74.443 214.362 74.651 ;
     RECT  212.868 74.587 213.297 74.759 ;
     RECT  102.315 60.809 102.597 75.259 ;
     RECT  102.315 75.259 102.942 75.389 ;
     RECT  102.315 75.389 102.69 75.581 ;
     RECT  5.115 71.069 5.397 75.811 ;
     RECT  10.26 74.039 10.89 75.839 ;
     RECT  5.115 75.811 5.526 75.929 ;
     RECT  3.456 74.039 4.23 75.937 ;
     RECT  5.115 75.929 5.397 75.937 ;
     RECT  6.84 75.811 6.858 76.037 ;
     RECT  2.415 74.039 2.697 76.171 ;
     RECT  196.815 42.893 197.097 76.171 ;
     RECT  199.515 36.797 199.797 76.171 ;
     RECT  196.704 76.171 197.097 76.208 ;
     RECT  199.404 76.171 199.797 76.208 ;
     RECT  42.444 59.189 42.462 76.243 ;
     RECT  190.404 76.171 190.422 76.301 ;
     RECT  2.304 76.171 2.697 76.315 ;
     RECT  3.456 75.937 5.397 76.315 ;
     RECT  2.304 76.315 5.397 76.469 ;
     RECT  2.304 76.469 2.697 76.649 ;
     RECT  3.456 76.469 5.397 76.883 ;
     RECT  203.256 63.851 205.197 76.987 ;
     RECT  203.256 76.987 205.29 77.117 ;
     RECT  206.352 76.987 206.37 77.117 ;
     RECT  207.615 69.005 207.897 77.161 ;
     RECT  208.764 77.083 208.782 77.189 ;
     RECT  211.968 77.161 212.166 77.279 ;
     RECT  207.615 77.161 207.99 77.309 ;
     RECT  210.315 74.621 210.597 77.323 ;
     RECT  214.308 77.179 214.326 77.351 ;
     RECT  212.148 77.279 212.166 77.357 ;
     RECT  210.132 77.323 210.597 77.36 ;
     RECT  7.668 74.309 8.097 77.755 ;
     RECT  7.668 77.755 8.658 77.819 ;
     RECT  7.668 77.819 8.298 77.936 ;
     RECT  5.04 76.883 5.397 78.367 ;
     RECT  5.04 78.367 5.85 78.439 ;
     RECT  11.664 73.841 12.33 78.467 ;
     RECT  3.456 76.883 4.23 78.511 ;
     RECT  5.04 78.439 6.066 78.511 ;
     RECT  6.912 78.475 6.93 78.511 ;
     RECT  10.296 75.839 10.89 78.511 ;
     RECT  11.664 78.467 11.682 78.511 ;
     RECT  2.415 76.649 2.697 78.601 ;
     RECT  3.456 78.511 6.93 78.601 ;
     RECT  2.415 78.601 6.93 78.665 ;
     RECT  10.296 78.511 11.682 78.665 ;
     RECT  7.668 77.936 8.097 78.673 ;
     RECT  0.216 78.667 0.234 78.899 ;
     RECT  5.04 78.665 5.706 78.899 ;
     RECT  7.128 78.673 8.097 78.899 ;
     RECT  2.415 78.665 4.23 79.511 ;
     RECT  103.752 79.555 103.77 79.591 ;
     RECT  103.752 79.591 103.95 79.613 ;
     RECT  103.932 79.613 103.95 79.805 ;
     RECT  213.015 74.759 213.297 79.915 ;
     RECT  209.124 79.819 209.142 79.979 ;
     RECT  213.015 79.915 213.786 80.123 ;
     RECT  207.615 77.309 207.897 80.131 ;
     RECT  207.615 80.131 208.746 80.189 ;
     RECT  195.84 80.221 195.858 80.285 ;
     RECT  196.815 76.208 197.097 80.329 ;
     RECT  196.815 80.329 197.406 80.381 ;
     RECT  10.404 78.665 11.682 80.663 ;
     RECT  2.415 79.511 2.697 80.761 ;
     RECT  10.404 80.663 11.106 80.905 ;
     RECT  6.84 80.941 6.858 81.067 ;
     RECT  9.792 80.905 11.106 81.103 ;
     RECT  7.668 78.899 8.097 81.131 ;
     RECT  9.18 81.103 11.106 81.175 ;
     RECT  105.015 57.875 105.297 81.175 ;
     RECT  1.728 80.761 2.697 81.197 ;
     RECT  2.376 81.197 2.697 81.211 ;
     RECT  3.456 79.511 4.23 81.211 ;
     RECT  6.768 81.067 6.858 81.211 ;
     RECT  7.704 81.131 8.097 81.211 ;
     RECT  8.892 81.175 11.106 81.211 ;
     RECT  6.768 81.211 6.966 81.329 ;
     RECT  7.704 81.211 11.106 81.329 ;
     RECT  2.376 81.211 4.23 81.365 ;
     RECT  7.704 81.329 9.198 81.401 ;
     RECT  104.688 81.175 105.297 81.485 ;
     RECT  2.415 81.365 4.23 81.599 ;
     RECT  6.768 81.329 6.786 81.599 ;
     RECT  10.44 81.329 11.106 82.679 ;
     RECT  214.344 82.699 214.362 82.751 ;
     RECT  206.352 82.651 206.37 82.781 ;
     RECT  210.315 77.36 210.597 82.789 ;
     RECT  7.815 81.401 9.198 82.795 ;
     RECT  210.315 82.789 210.87 82.831 ;
     RECT  213.015 80.123 213.297 82.831 ;
     RECT  211.788 82.747 211.806 82.859 ;
     RECT  210.315 82.831 211.014 82.949 ;
     RECT  212.796 82.831 213.297 82.985 ;
     RECT  212.184 83.029 212.202 83.129 ;
     RECT  7.815 82.795 9.342 83.299 ;
     RECT  102.315 75.581 102.597 83.335 ;
     RECT  7.815 83.299 9.486 83.371 ;
     RECT  6.84 83.299 6.858 83.399 ;
     RECT  102.132 83.335 102.597 83.405 ;
     RECT  7.704 83.371 9.486 83.489 ;
     RECT  7.704 83.489 9.09 83.525 ;
     RECT  2.415 81.599 2.697 83.641 ;
     RECT  7.704 83.525 8.802 83.669 ;
     RECT  2.376 83.641 2.697 83.707 ;
     RECT  2.304 83.707 2.697 83.839 ;
     RECT  3.456 81.599 4.23 83.839 ;
     RECT  2.304 83.839 4.23 84.029 ;
     RECT  202.215 61.181 202.497 84.139 ;
     RECT  196.815 80.381 197.097 84.271 ;
     RECT  2.415 84.029 4.23 84.299 ;
     RECT  202.14 84.139 202.497 84.299 ;
     RECT  196.704 84.271 197.097 84.317 ;
     RECT  198.36 84.139 198.378 84.317 ;
     RECT  208.944 85.051 208.962 85.099 ;
     RECT  208.62 85.099 208.962 85.145 ;
     RECT  104.076 85.225 104.094 85.261 ;
     RECT  210.315 82.949 210.597 85.261 ;
     RECT  104.076 85.261 104.238 85.277 ;
     RECT  213.015 82.985 213.297 85.351 ;
     RECT  210.168 85.261 210.597 85.379 ;
     RECT  208.944 85.145 208.962 85.415 ;
     RECT  210.315 85.379 210.597 85.435 ;
     RECT  212.976 85.351 213.297 85.469 ;
     RECT  214.344 85.423 214.362 85.469 ;
     RECT  210.315 85.435 211.302 85.483 ;
     RECT  209.376 85.423 209.394 85.517 ;
     RECT  6.732 85.495 6.75 85.531 ;
     RECT  6.624 85.531 6.75 85.621 ;
     RECT  210.315 85.483 211.41 85.649 ;
     RECT  6.624 85.621 6.93 85.661 ;
     RECT  210.315 85.649 211.302 85.685 ;
     RECT  2.415 84.299 2.697 85.891 ;
     RECT  6.624 85.661 6.75 85.919 ;
     RECT  6.624 85.919 6.642 85.997 ;
     RECT  1.728 85.891 2.697 86.285 ;
     RECT  2.376 86.285 2.697 86.341 ;
     RECT  3.456 84.299 4.23 86.341 ;
     RECT  106.2 86.305 106.218 86.341 ;
     RECT  2.376 86.341 4.23 86.495 ;
     RECT  7.704 83.669 8.097 86.587 ;
     RECT  7.488 86.587 8.097 86.635 ;
     RECT  7.488 86.635 8.73 86.639 ;
     RECT  2.415 86.495 4.23 86.737 ;
     RECT  2.415 86.737 4.338 86.881 ;
     RECT  5.115 78.899 5.397 86.881 ;
     RECT  2.415 86.881 5.397 86.999 ;
     RECT  7.704 86.639 8.73 87.197 ;
     RECT  7.704 87.197 8.55 87.269 ;
     RECT  7.704 87.269 8.406 87.305 ;
     RECT  202.215 84.299 202.497 87.511 ;
     RECT  202.215 87.511 202.518 87.581 ;
     RECT  210.315 85.685 210.597 87.781 ;
     RECT  196.815 84.317 197.097 87.787 ;
     RECT  106.2 86.341 106.47 87.817 ;
     RECT  3.456 86.999 5.397 87.845 ;
     RECT  196.815 87.787 197.19 87.917 ;
     RECT  198.36 87.787 198.378 87.917 ;
     RECT  106.2 87.817 106.614 87.953 ;
     RECT  209.88 87.781 210.597 87.961 ;
     RECT  15.915 58.721 19.962 88.051 ;
     RECT  20.88 45.995 21.597 88.051 ;
     RECT  206.352 87.961 206.37 88.079 ;
     RECT  209.88 87.961 210.942 88.079 ;
     RECT  209.88 88.079 210.654 88.205 ;
     RECT  214.344 88.171 214.362 88.223 ;
     RECT  209.988 88.205 210.654 88.253 ;
     RECT  210.315 88.253 210.654 88.259 ;
     RECT  6.264 87.961 6.282 88.591 ;
     RECT  7.704 87.305 8.097 88.627 ;
     RECT  41.868 76.243 42.462 88.655 ;
     RECT  5.115 87.845 5.397 88.699 ;
     RECT  6.264 88.591 6.678 88.699 ;
     RECT  7.488 88.627 8.097 88.699 ;
     RECT  107.715 59.495 107.997 88.735 ;
     RECT  3.456 87.845 4.302 88.747 ;
     RECT  2.415 86.999 2.697 88.771 ;
     RECT  3.42 88.747 4.302 88.771 ;
     RECT  107.715 88.735 108.702 88.771 ;
     RECT  2.415 88.771 4.302 88.889 ;
     RECT  5.115 88.699 8.097 88.889 ;
     RECT  5.115 88.889 6.354 88.925 ;
     RECT  3.456 88.889 4.302 88.961 ;
     RECT  2.415 88.889 2.697 89.041 ;
     RECT  7.416 88.889 8.097 89.041 ;
     RECT  2.304 89.041 2.697 89.159 ;
     RECT  5.115 88.925 5.958 89.159 ;
     RECT  7.416 89.041 8.478 89.159 ;
     RECT  128.52 87.817 128.538 89.167 ;
     RECT  203.256 77.117 205.197 89.275 ;
     RECT  210.315 88.259 210.597 89.743 ;
     RECT  5.115 89.159 5.397 90.481 ;
     RECT  5.004 90.481 5.397 90.751 ;
     RECT  207.615 80.189 207.897 90.751 ;
     RECT  209.124 90.661 209.142 90.751 ;
     RECT  207.615 90.751 209.142 90.779 ;
     RECT  207.615 90.779 208.746 90.797 ;
     RECT  213.015 85.469 213.297 90.895 ;
     RECT  210.024 89.743 210.597 90.907 ;
     RECT  213.015 90.895 213.786 90.931 ;
     RECT  208.728 90.797 208.746 90.941 ;
     RECT  212.616 90.931 213.786 90.941 ;
     RECT  10.515 82.679 11.106 91.021 ;
     RECT  5.004 90.751 5.526 91.048 ;
     RECT  6.336 91.003 6.354 91.048 ;
     RECT  210.024 90.907 210.654 91.049 ;
     RECT  5.004 91.048 6.354 91.085 ;
     RECT  212.616 90.941 213.297 91.085 ;
     RECT  14.832 91.021 14.85 91.157 ;
     RECT  5.004 91.085 5.397 91.193 ;
     RECT  2.415 89.159 2.697 91.201 ;
     RECT  3.456 88.961 4.23 91.201 ;
     RECT  7.416 89.159 8.097 91.201 ;
     RECT  2.304 91.201 4.23 91.319 ;
     RECT  6.444 91.201 6.462 91.319 ;
     RECT  9.864 91.021 11.106 91.319 ;
     RECT  41.868 88.655 41.994 91.363 ;
     RECT  7.416 91.201 8.154 91.399 ;
     RECT  7.416 91.399 8.586 91.435 ;
     RECT  7.416 91.435 8.694 91.471 ;
     RECT  0.54 91.243 0.558 91.499 ;
     RECT  6.588 91.471 8.694 91.517 ;
     RECT  2.415 91.319 4.23 91.589 ;
     RECT  6.732 91.517 8.694 91.661 ;
     RECT  7.416 91.661 8.694 91.705 ;
     RECT  7.416 91.705 8.982 91.733 ;
     RECT  104.22 85.277 104.238 91.975 ;
     RECT  104.148 91.975 104.238 92.011 ;
     RECT  105.015 81.485 105.297 92.011 ;
     RECT  128.52 89.167 128.574 92.947 ;
     RECT  7.815 91.733 8.097 93.091 ;
     RECT  8.964 91.733 8.982 93.091 ;
     RECT  10.515 91.319 11.106 93.181 ;
     RECT  213.015 91.085 213.297 93.181 ;
     RECT  13.215 59.843 13.497 93.325 ;
     RECT  10.008 93.181 11.106 93.361 ;
     RECT  210.024 91.049 210.597 93.451 ;
     RECT  211.536 88.501 211.554 93.451 ;
     RECT  210.024 93.451 211.554 93.479 ;
     RECT  7.815 93.091 8.982 93.631 ;
     RECT  9.9 93.361 11.106 93.631 ;
     RECT  212.724 93.181 213.297 93.691 ;
     RECT  210.024 93.479 210.942 93.749 ;
     RECT  12.744 93.325 13.497 93.757 ;
     RECT  210.024 93.749 210.597 93.757 ;
     RECT  2.415 91.589 2.697 93.829 ;
     RECT  212.724 93.691 213.786 93.865 ;
     RECT  212.076 93.865 213.786 93.893 ;
     RECT  123.915 48.029 124.197 93.901 ;
     RECT  0.216 93.787 0.234 93.929 ;
     RECT  2.304 93.829 2.697 94.019 ;
     RECT  12.672 93.757 13.497 94.027 ;
     RECT  212.076 93.893 213.297 94.055 ;
     RECT  15.915 88.051 21.597 94.361 ;
     RECT  7.815 93.631 11.106 94.559 ;
     RECT  9.396 94.559 11.106 95.009 ;
     RECT  3.456 91.589 4.23 95.179 ;
     RECT  5.115 91.193 5.397 95.179 ;
     RECT  7.815 94.559 8.658 95.477 ;
     RECT  209.772 93.757 210.597 96.061 ;
     RECT  209.772 96.061 210.726 96.125 ;
     RECT  2.415 94.019 2.697 96.151 ;
     RECT  3.456 95.179 5.397 96.259 ;
     RECT  209.772 96.125 210.618 96.283 ;
     RECT  209.592 96.283 210.618 96.287 ;
     RECT  1.728 96.151 2.697 96.295 ;
     RECT  3.456 96.259 5.706 96.295 ;
     RECT  1.728 96.295 5.706 96.323 ;
     RECT  209.592 96.287 210.597 96.323 ;
     RECT  1.728 96.323 4.23 96.365 ;
     RECT  212.724 94.055 213.297 96.427 ;
     RECT  2.415 96.365 4.23 96.449 ;
     RECT  212.724 96.427 213.786 96.593 ;
     RECT  211.68 97.765 211.698 97.805 ;
     RECT  211.392 97.951 211.41 98.045 ;
     RECT  203.22 89.275 205.197 98.339 ;
     RECT  12.6 94.027 13.497 98.347 ;
     RECT  3.456 96.449 4.23 98.617 ;
     RECT  5.115 96.323 5.706 98.617 ;
     RECT  3.456 98.617 5.778 98.63 ;
     RECT  2.415 96.449 2.697 98.761 ;
     RECT  7.815 95.477 8.097 98.761 ;
     RECT  2.304 98.761 2.697 98.879 ;
     RECT  3.456 98.63 5.958 98.995 ;
     RECT  12.564 98.347 13.497 98.995 ;
     RECT  209.772 96.323 210.597 99.019 ;
     RECT  2.415 98.879 2.697 99.031 ;
     RECT  3.456 98.995 6.138 99.031 ;
     RECT  212.724 96.593 213.297 99.031 ;
     RECT  0.216 98.827 0.234 99.059 ;
     RECT  209.52 99.019 210.597 99.059 ;
     RECT  12.24 98.995 13.497 99.121 ;
     RECT  2.415 99.031 6.138 99.149 ;
     RECT  212.688 99.031 213.297 99.149 ;
     RECT  2.415 99.149 5.958 99.197 ;
     RECT  214.344 99.157 214.362 99.197 ;
     RECT  5.115 99.197 5.958 99.221 ;
     RECT  11.952 99.121 13.497 99.563 ;
     RECT  7.815 98.761 8.514 99.571 ;
     RECT  10.008 95.009 11.106 99.733 ;
     RECT  2.415 99.197 4.23 99.761 ;
     RECT  129.6 49.919 167.616 99.967 ;
     RECT  7.815 99.571 9.162 100.499 ;
     RECT  12.24 99.563 13.497 100.607 ;
     RECT  7.815 100.499 8.982 100.645 ;
     RECT  7.452 100.645 8.982 100.741 ;
     RECT  6.84 100.741 8.982 100.769 ;
     RECT  2.415 99.761 2.697 101.191 ;
     RECT  6.84 100.769 8.442 101.191 ;
     RECT  6.624 101.191 8.442 101.219 ;
     RECT  6.624 101.219 6.642 101.275 ;
     RECT  2.304 101.191 2.697 101.281 ;
     RECT  3.456 99.761 4.23 101.281 ;
     RECT  6.48 101.275 6.642 101.315 ;
     RECT  7.38 101.219 8.442 101.345 ;
     RECT  0.216 101.323 0.234 101.381 ;
     RECT  7.416 101.345 8.442 101.381 ;
     RECT  208.836 100.003 208.854 101.563 ;
     RECT  2.304 101.281 4.23 101.579 ;
     RECT  208.836 101.563 209.034 101.707 ;
     RECT  209.772 99.059 210.597 101.707 ;
     RECT  19.764 94.361 21.597 101.759 ;
     RECT  208.836 101.707 210.597 101.759 ;
     RECT  209.772 101.759 210.597 101.821 ;
     RECT  211.356 101.707 211.374 101.821 ;
     RECT  206.352 101.731 206.37 101.849 ;
     RECT  209.772 101.821 211.374 101.849 ;
     RECT  209.772 101.849 211.23 101.993 ;
     RECT  214.344 101.899 214.362 101.993 ;
     RECT  9.936 99.733 11.106 102.811 ;
     RECT  12.24 100.607 12.258 103.199 ;
     RECT  7.815 101.381 8.442 103.279 ;
     RECT  7.815 103.279 8.55 103.315 ;
     RECT  9.72 102.811 11.106 103.315 ;
     RECT  7.815 103.315 11.106 103.469 ;
     RECT  7.815 103.469 9.09 103.505 ;
     RECT  7.815 103.505 8.874 103.621 ;
     RECT  7.74 103.621 8.874 103.723 ;
     RECT  209.772 101.993 210.654 103.723 ;
     RECT  2.415 101.579 2.697 103.819 ;
     RECT  3.456 101.579 4.23 103.819 ;
     RECT  2.415 103.819 4.23 103.867 ;
     RECT  7.596 103.723 8.874 103.883 ;
     RECT  2.268 103.867 4.23 103.919 ;
     RECT  209.772 103.723 210.726 104.155 ;
     RECT  209.772 104.155 211.158 104.195 ;
     RECT  2.304 103.919 4.23 104.279 ;
     RECT  7.815 103.883 8.874 104.279 ;
     RECT  2.304 104.279 2.697 104.315 ;
     RECT  212.724 99.149 213.297 104.665 ;
     RECT  212.148 104.665 213.297 104.701 ;
     RECT  212.148 104.701 213.426 104.717 ;
     RECT  212.724 104.717 213.426 104.855 ;
     RECT  212.724 104.855 213.354 105.089 ;
     RECT  214.884 104.683 214.902 105.161 ;
     RECT  191.415 4.289 191.697 106.027 ;
     RECT  202.215 87.581 202.497 106.051 ;
     RECT  203.22 98.339 204.03 106.051 ;
     RECT  43.2 52.583 81.216 106.11 ;
     RECT  129.6 99.967 167.85 106.11 ;
     RECT  2.415 104.315 2.697 106.141 ;
     RECT  3.456 104.279 4.23 106.141 ;
     RECT  106.2 87.953 106.47 106.205 ;
     RECT  202.215 106.051 204.03 106.205 ;
     RECT  177.915 42.893 178.197 106.219 ;
     RECT  203.22 106.205 204.03 106.241 ;
     RECT  41.868 91.363 42.066 106.277 ;
     RECT  188.715 42.899 188.997 106.312 ;
     RECT  106.308 106.205 106.47 106.315 ;
     RECT  2.415 106.141 4.23 106.321 ;
     RECT  5.115 99.221 5.397 106.321 ;
     RECT  2.415 106.321 5.397 106.411 ;
     RECT  13.215 100.607 13.497 106.411 ;
     RECT  21.315 101.759 21.597 106.411 ;
     RECT  26.715 46.805 26.997 106.411 ;
     RECT  96.915 46.535 97.197 106.411 ;
     RECT  102.276 83.405 102.597 106.411 ;
     RECT  191.415 106.027 192.114 106.411 ;
     RECT  191.415 106.411 192.438 106.439 ;
     RECT  13.104 106.411 13.497 106.448 ;
     RECT  21.204 106.411 21.597 106.448 ;
     RECT  96.804 106.411 97.197 106.448 ;
     RECT  192.42 106.439 192.438 106.493 ;
     RECT  104.148 92.011 105.297 106.507 ;
     RECT  14.832 106.411 14.85 106.541 ;
     RECT  26.676 106.411 26.997 106.541 ;
     RECT  30.78 106.411 30.798 106.541 ;
     RECT  86.652 106.411 86.67 106.541 ;
     RECT  98.604 106.411 98.622 106.541 ;
     RECT  128.52 92.947 128.61 106.591 ;
     RECT  104.148 106.507 105.534 106.603 ;
     RECT  194.115 33.377 194.397 106.603 ;
     RECT  104.04 106.603 105.534 106.619 ;
     RECT  122.4 93.901 122.418 106.619 ;
     RECT  128.52 106.591 128.718 106.619 ;
     RECT  203.292 106.241 204.03 106.619 ;
     RECT  126.54 106.591 126.558 106.664 ;
     RECT  128.592 106.619 128.718 106.664 ;
     RECT  187.2 106.603 187.218 106.699 ;
     RECT  2.304 106.411 5.397 106.709 ;
     RECT  10.08 103.469 11.106 106.709 ;
     RECT  107.715 88.771 108.954 106.709 ;
     RECT  203.472 106.619 204.03 106.709 ;
     RECT  2.304 106.709 4.086 106.745 ;
     RECT  108.936 106.709 108.954 106.745 ;
     RECT  128.592 106.664 128.646 106.745 ;
     RECT  19.764 101.759 20.358 106.781 ;
     RECT  128.592 106.745 128.61 106.781 ;
     RECT  195.552 106.603 195.57 106.795 ;
     RECT  41.868 106.277 41.958 106.817 ;
     RECT  106.308 106.315 106.614 106.817 ;
     RECT  41.868 106.817 41.886 106.853 ;
     RECT  102.276 106.411 102.618 106.853 ;
     RECT  110.415 49.001 110.697 106.861 ;
     RECT  2.304 106.745 2.697 106.889 ;
     RECT  7.815 104.279 8.442 106.889 ;
     RECT  122.544 106.789 122.562 106.889 ;
     RECT  188.604 106.312 188.997 106.889 ;
     RECT  198.468 106.603 198.486 106.951 ;
     RECT  199.515 76.208 199.797 106.951 ;
     RECT  104.04 106.619 105.297 106.979 ;
     RECT  187.2 106.699 187.506 106.979 ;
     RECT  193.608 106.603 194.397 106.979 ;
     RECT  195.552 106.795 195.894 106.979 ;
     RECT  198.468 106.951 199.797 106.979 ;
     RECT  10.08 106.709 10.797 107.015 ;
     RECT  123.3 93.901 124.197 107.015 ;
     RECT  104.328 106.979 105.297 107.021 ;
     RECT  106.596 106.817 106.614 107.021 ;
     RECT  110.376 106.861 110.697 107.021 ;
     RECT  114.552 106.219 114.678 107.021 ;
     RECT  174.42 106.219 174.438 107.021 ;
     RECT  177.915 106.219 178.434 107.021 ;
     RECT  190.404 106.315 190.422 107.021 ;
     RECT  198.792 106.979 199.797 107.021 ;
     RECT  102.315 106.853 102.618 107.087 ;
     RECT  104.4 107.021 105.297 107.087 ;
     RECT  209.772 104.195 210.654 107.249 ;
     RECT  209.772 107.249 210.597 107.365 ;
     RECT  209.7 107.365 210.597 107.405 ;
     RECT  214.344 107.365 214.362 107.453 ;
     RECT  203.688 106.709 204.03 108.059 ;
     RECT  5.115 106.709 5.397 108.283 ;
     RECT  3.492 106.745 3.906 108.679 ;
     RECT  2.415 106.889 2.697 108.751 ;
     RECT  3.492 108.679 4.122 108.751 ;
     RECT  6.624 101.315 6.642 108.751 ;
     RECT  5.004 108.283 5.397 108.811 ;
     RECT  2.268 108.751 4.122 108.869 ;
     RECT  4.86 108.811 5.397 108.869 ;
     RECT  6.12 108.751 6.642 108.869 ;
     RECT  5.115 108.869 5.397 108.877 ;
     RECT  2.268 108.869 3.978 108.941 ;
     RECT  2.304 108.941 3.978 109.139 ;
     RECT  5.115 108.877 5.598 109.175 ;
     RECT  7.815 106.889 8.097 109.219 ;
     RECT  5.115 109.175 5.418 109.247 ;
     RECT  208.836 101.759 208.854 109.435 ;
     RECT  209.772 107.405 210.597 109.435 ;
     RECT  212.724 105.089 213.297 109.831 ;
     RECT  212.256 109.831 213.297 109.949 ;
     RECT  208.836 109.435 210.597 109.985 ;
     RECT  212.616 109.949 213.297 110.219 ;
     RECT  214.236 110.155 214.254 110.291 ;
     RECT  2.415 109.139 2.697 111.001 ;
     RECT  6.624 108.869 6.642 111.163 ;
     RECT  10.188 107.015 10.797 111.407 ;
     RECT  141.048 111.379 141.066 111.415 ;
     RECT  1.728 111.001 2.697 111.437 ;
     RECT  167.832 106.11 167.85 111.443 ;
     RECT  7.416 109.219 8.097 111.451 ;
     RECT  138.852 106.861 138.87 111.451 ;
     RECT  203.688 108.059 203.958 111.479 ;
     RECT  139.716 108.031 139.734 111.493 ;
     RECT  140.76 111.415 141.066 111.493 ;
     RECT  6.48 111.163 6.642 111.569 ;
     RECT  138.852 111.451 138.942 111.569 ;
     RECT  139.716 111.493 141.066 111.569 ;
     RECT  7.416 111.451 8.658 111.577 ;
     RECT  141.12 111.577 141.138 111.677 ;
     RECT  40.407 111.493 40.497 111.763 ;
     RECT  43.107 111.493 43.197 111.763 ;
     RECT  45.807 111.493 45.897 111.763 ;
     RECT  48.507 111.493 48.597 111.763 ;
     RECT  51.207 111.493 51.297 111.763 ;
     RECT  53.907 111.493 53.997 111.763 ;
     RECT  56.607 111.493 56.697 111.763 ;
     RECT  59.307 111.493 59.397 111.763 ;
     RECT  62.007 111.493 62.097 111.763 ;
     RECT  64.707 111.493 64.797 111.763 ;
     RECT  67.407 111.493 67.497 111.763 ;
     RECT  70.107 111.493 70.197 111.763 ;
     RECT  72.807 111.493 72.897 111.763 ;
     RECT  75.507 111.493 75.597 111.763 ;
     RECT  78.207 111.493 78.297 111.763 ;
     RECT  80.907 111.493 80.997 111.763 ;
     RECT  83.607 111.493 83.697 111.763 ;
     RECT  86.307 111.493 86.397 111.763 ;
     RECT  126.807 111.493 126.897 111.763 ;
     RECT  129.507 111.493 129.597 111.763 ;
     RECT  132.207 111.493 132.297 111.763 ;
     RECT  134.907 111.493 134.997 111.763 ;
     RECT  137.607 111.493 137.697 111.763 ;
     RECT  143.007 111.493 143.097 111.763 ;
     RECT  145.707 111.493 145.797 111.763 ;
     RECT  148.407 111.493 148.497 111.763 ;
     RECT  151.107 111.493 151.197 111.763 ;
     RECT  153.807 111.493 153.897 111.763 ;
     RECT  156.507 111.493 156.597 111.763 ;
     RECT  159.207 111.493 159.297 111.763 ;
     RECT  161.907 111.493 161.997 111.763 ;
     RECT  164.607 111.493 164.697 111.763 ;
     RECT  167.307 111.493 167.397 111.763 ;
     RECT  170.007 111.493 170.097 111.763 ;
     RECT  172.707 111.493 172.797 111.763 ;
     RECT  6.804 111.577 8.658 111.875 ;
     RECT  2.304 111.437 2.697 112.019 ;
     RECT  6.804 111.875 6.822 112.019 ;
     RECT  208.836 109.985 208.854 112.315 ;
     RECT  209.772 109.985 210.597 112.649 ;
     RECT  208.836 112.315 208.89 112.801 ;
     RECT  210.024 112.649 210.597 112.891 ;
     RECT  212.724 110.219 213.297 112.891 ;
     RECT  212.364 112.891 213.297 112.939 ;
     RECT  208.836 112.801 209.034 112.973 ;
     RECT  210.024 112.891 210.942 112.973 ;
     RECT  212.364 112.939 213.786 112.991 ;
     RECT  212.724 112.991 213.786 113.063 ;
     RECT  210.024 112.973 210.597 113.701 ;
     RECT  203.688 111.479 203.706 113.729 ;
     RECT  15.915 94.361 18.897 113.873 ;
     RECT  2.415 112.019 2.697 113.881 ;
     RECT  3.492 109.139 3.978 113.881 ;
     RECT  7.815 111.875 8.658 113.881 ;
     RECT  2.415 113.881 3.978 113.947 ;
     RECT  7.815 113.881 9.378 113.999 ;
     RECT  7.815 113.999 8.946 114.107 ;
     RECT  8.928 114.107 8.946 114.269 ;
     RECT  2.304 113.947 3.978 114.539 ;
     RECT  212.724 113.063 213.297 115.321 ;
     RECT  212.724 115.321 213.354 115.349 ;
     RECT  211.716 115.465 211.734 115.501 ;
     RECT  211.716 115.501 211.878 115.517 ;
     RECT  211.86 115.517 211.878 115.619 ;
     RECT  212.94 115.349 213.354 115.655 ;
     RECT  213.015 115.655 213.354 115.889 ;
     RECT  2.415 114.539 2.697 116.299 ;
     RECT  3.492 114.539 3.978 116.299 ;
     RECT  0.216 116.491 0.234 116.537 ;
     RECT  2.415 116.299 3.978 116.545 ;
     RECT  2.415 116.545 4.23 116.581 ;
     RECT  5.115 109.247 5.397 116.581 ;
     RECT  2.415 116.581 5.397 116.699 ;
     RECT  5.115 116.699 5.397 116.779 ;
     RECT  4.068 116.699 4.23 116.807 ;
     RECT  2.415 116.699 3.294 116.843 ;
     RECT  2.415 116.843 3.006 116.969 ;
     RECT  4.068 116.807 4.086 116.969 ;
     RECT  2.415 116.969 2.754 117.149 ;
     RECT  5.115 116.779 5.814 118.555 ;
     RECT  2.415 117.149 2.697 118.561 ;
     RECT  210.024 113.701 210.69 118.589 ;
     RECT  211.608 118.555 211.626 118.625 ;
     RECT  214.344 118.411 214.362 118.661 ;
     RECT  2.376 118.561 2.697 118.741 ;
     RECT  213.015 115.889 213.297 118.741 ;
     RECT  211.752 118.705 211.77 118.859 ;
     RECT  212.832 118.741 213.297 118.895 ;
     RECT  15.915 113.873 16.794 119.003 ;
     RECT  4.86 118.555 5.814 119.011 ;
     RECT  0.216 118.831 0.234 119.021 ;
     RECT  2.376 118.741 2.934 119.101 ;
     RECT  3.816 119.011 3.834 119.129 ;
     RECT  4.86 119.011 6.138 119.129 ;
     RECT  2.376 119.101 3.006 119.165 ;
     RECT  2.415 119.165 3.006 119.273 ;
     RECT  7.815 114.107 8.097 119.281 ;
     RECT  5.115 119.129 5.814 119.309 ;
     RECT  5.115 119.309 5.67 119.435 ;
     RECT  19.764 106.781 19.782 120.011 ;
     RECT  207.615 90.797 207.897 121.297 ;
     RECT  214.344 121.147 214.362 121.361 ;
     RECT  2.415 119.273 2.697 121.369 ;
     RECT  207.615 121.297 207.954 121.421 ;
     RECT  2.415 121.369 3.366 121.441 ;
     RECT  208.836 112.973 208.854 121.441 ;
     RECT  0.216 121.483 0.234 121.559 ;
     RECT  6.624 119.983 6.642 121.559 ;
     RECT  208.836 121.441 208.926 121.559 ;
     RECT  210.024 118.589 210.597 121.559 ;
     RECT  7.416 119.281 8.097 121.675 ;
     RECT  2.415 121.441 3.654 121.711 ;
     RECT  2.415 121.711 3.762 121.829 ;
     RECT  7.308 121.675 8.097 121.829 ;
     RECT  2.415 121.829 3.186 121.901 ;
     RECT  6.48 121.711 6.498 121.997 ;
     RECT  207.615 121.421 207.897 122.587 ;
     RECT  208.836 121.559 208.854 122.587 ;
     RECT  7.416 121.829 8.097 122.635 ;
     RECT  207.615 122.587 208.854 122.639 ;
     RECT  207.615 122.639 207.99 122.675 ;
     RECT  7.272 122.635 8.097 122.909 ;
     RECT  7.56 122.909 8.097 122.915 ;
     RECT  207.615 122.675 207.897 123.691 ;
     RECT  208.836 122.639 208.854 123.719 ;
     RECT  2.415 121.901 2.697 123.799 ;
     RECT  8.928 121.945 8.946 123.835 ;
     RECT  7.815 122.915 8.097 123.871 ;
     RECT  8.82 123.835 8.946 123.871 ;
     RECT  207.615 123.691 207.954 123.871 ;
     RECT  210.315 121.559 210.597 123.871 ;
     RECT  2.34 123.799 2.697 123.899 ;
     RECT  213.015 118.895 213.297 123.931 ;
     RECT  4.176 123.871 4.194 123.989 ;
     RECT  7.815 123.871 9.27 123.989 ;
     RECT  10.515 111.407 10.797 123.997 ;
     RECT  17.928 113.873 18.897 124.025 ;
     RECT  210.315 123.871 210.69 124.025 ;
     RECT  6.84 123.961 6.858 124.061 ;
     RECT  9.252 123.989 9.27 124.061 ;
     RECT  207.615 123.871 208.098 124.097 ;
     RECT  7.815 123.989 8.154 124.133 ;
     RECT  10.515 123.997 10.854 124.133 ;
     RECT  213.015 123.931 213.786 124.133 ;
     RECT  3.42 124.027 3.438 124.259 ;
     RECT  2.415 123.899 2.697 124.411 ;
     RECT  2.415 124.411 2.97 124.529 ;
     RECT  2.415 124.529 2.862 124.565 ;
     RECT  2.415 124.565 2.697 127.187 ;
     RECT  5.115 119.435 5.397 127.187 ;
     RECT  7.815 124.133 8.097 127.187 ;
     RECT  10.515 124.133 10.797 127.187 ;
     RECT  13.215 106.448 13.497 127.187 ;
     RECT  15.915 119.003 16.197 127.187 ;
     RECT  18.615 124.025 18.897 127.187 ;
     RECT  21.315 106.448 21.597 127.187 ;
     RECT  24.015 46.679 24.297 127.187 ;
     RECT  26.715 106.541 26.997 127.187 ;
     RECT  29.415 46.499 29.697 127.187 ;
     RECT  32.115 47.039 32.397 127.187 ;
     RECT  34.815 48.029 35.097 127.187 ;
     RECT  37.515 48.119 37.797 127.187 ;
     RECT  40.215 111.763 40.497 127.187 ;
     RECT  42.915 111.763 43.197 127.187 ;
     RECT  45.615 111.763 45.897 127.187 ;
     RECT  48.315 111.763 48.597 127.187 ;
     RECT  51.015 111.763 51.297 127.187 ;
     RECT  53.715 111.763 53.997 127.187 ;
     RECT  56.415 111.763 56.697 127.187 ;
     RECT  59.115 111.763 59.397 127.187 ;
     RECT  61.815 111.763 62.097 127.187 ;
     RECT  64.515 111.763 64.797 127.187 ;
     RECT  67.215 111.763 67.497 127.187 ;
     RECT  69.915 111.763 70.197 127.187 ;
     RECT  72.615 111.763 72.897 127.187 ;
     RECT  75.315 111.763 75.597 127.187 ;
     RECT  78.015 111.763 78.297 127.187 ;
     RECT  80.715 111.763 80.997 127.187 ;
     RECT  83.415 111.763 83.697 127.187 ;
     RECT  86.115 111.763 86.397 127.187 ;
     RECT  88.815 42.701 89.097 127.187 ;
     RECT  91.515 45.149 91.797 127.187 ;
     RECT  94.215 45.533 94.497 127.187 ;
     RECT  96.915 106.448 97.197 127.187 ;
     RECT  99.615 48.461 99.897 127.187 ;
     RECT  102.315 107.087 102.597 127.187 ;
     RECT  105.015 107.087 105.297 127.187 ;
     RECT  107.715 106.709 107.997 127.187 ;
     RECT  110.415 107.021 110.697 127.187 ;
     RECT  113.115 48.839 113.397 127.187 ;
     RECT  115.815 56.489 116.097 127.187 ;
     RECT  118.515 47.885 118.797 127.187 ;
     RECT  121.215 48.731 121.497 127.187 ;
     RECT  123.915 107.015 124.197 127.187 ;
     RECT  126.615 111.763 126.897 127.187 ;
     RECT  129.315 111.763 129.597 127.187 ;
     RECT  132.015 111.763 132.297 127.187 ;
     RECT  134.715 111.763 134.997 127.187 ;
     RECT  137.415 111.763 137.697 127.187 ;
     RECT  140.115 111.569 140.397 127.187 ;
     RECT  142.815 111.763 143.097 127.187 ;
     RECT  145.515 111.763 145.797 127.187 ;
     RECT  148.215 111.763 148.497 127.187 ;
     RECT  150.915 111.763 151.197 127.187 ;
     RECT  153.615 111.763 153.897 127.187 ;
     RECT  156.315 111.763 156.597 127.187 ;
     RECT  159.015 111.763 159.297 127.187 ;
     RECT  161.715 111.763 161.997 127.187 ;
     RECT  164.415 111.763 164.697 127.187 ;
     RECT  167.115 111.763 167.397 127.187 ;
     RECT  169.815 111.763 170.097 127.187 ;
     RECT  172.515 111.763 172.797 127.187 ;
     RECT  175.215 2.413 175.497 127.187 ;
     RECT  177.915 107.021 178.197 127.187 ;
     RECT  180.615 63.725 180.897 127.187 ;
     RECT  183.315 2.413 183.597 127.187 ;
     RECT  186.015 42.893 186.297 127.187 ;
     RECT  188.715 106.889 188.997 127.187 ;
     RECT  191.415 106.439 191.697 127.187 ;
     RECT  194.115 106.979 194.397 127.187 ;
     RECT  196.815 87.917 197.097 127.187 ;
     RECT  199.515 107.021 199.797 127.187 ;
     RECT  202.215 106.205 202.497 127.187 ;
     RECT  204.915 98.339 205.197 127.187 ;
     RECT  207.615 124.097 207.897 127.187 ;
     RECT  210.315 124.025 210.597 127.187 ;
     RECT  213.015 124.133 213.297 127.187 ;
     RECT  2.415 127.187 2.505 127.457 ;
     RECT  5.115 127.187 5.205 127.457 ;
     RECT  7.815 127.187 7.905 127.457 ;
     RECT  10.515 127.187 10.605 127.457 ;
     RECT  13.215 127.187 13.305 127.457 ;
     RECT  15.915 127.187 16.005 127.457 ;
     RECT  18.615 127.187 18.705 127.457 ;
     RECT  21.315 127.187 21.405 127.457 ;
     RECT  24.015 127.187 24.105 127.457 ;
     RECT  26.715 127.187 26.805 127.457 ;
     RECT  29.415 127.187 29.505 127.457 ;
     RECT  32.115 127.187 32.205 127.457 ;
     RECT  34.815 127.187 34.905 127.457 ;
     RECT  37.515 127.187 37.605 127.457 ;
     RECT  40.215 127.187 40.305 127.457 ;
     RECT  42.915 127.187 43.005 127.457 ;
     RECT  45.615 127.187 45.705 127.457 ;
     RECT  48.315 127.187 48.405 127.457 ;
     RECT  51.015 127.187 51.105 127.457 ;
     RECT  53.715 127.187 53.805 127.457 ;
     RECT  56.415 127.187 56.505 127.457 ;
     RECT  59.115 127.187 59.205 127.457 ;
     RECT  61.815 127.187 61.905 127.457 ;
     RECT  64.515 127.187 64.605 127.457 ;
     RECT  67.215 127.187 67.305 127.457 ;
     RECT  69.915 127.187 70.005 127.457 ;
     RECT  72.615 127.187 72.705 127.457 ;
     RECT  75.315 127.187 75.405 127.457 ;
     RECT  78.015 127.187 78.105 127.457 ;
     RECT  80.715 127.187 80.805 127.457 ;
     RECT  83.415 127.187 83.505 127.457 ;
     RECT  86.115 127.187 86.205 127.457 ;
     RECT  88.815 127.187 88.905 127.457 ;
     RECT  91.515 127.187 91.605 127.457 ;
     RECT  94.215 127.187 94.305 127.457 ;
     RECT  96.915 127.187 97.005 127.457 ;
     RECT  99.615 127.187 99.705 127.457 ;
     RECT  102.315 127.187 102.405 127.457 ;
     RECT  105.015 127.187 105.105 127.457 ;
     RECT  107.715 127.187 107.805 127.457 ;
     RECT  110.415 127.187 110.505 127.457 ;
     RECT  113.115 127.187 113.205 127.457 ;
     RECT  115.815 127.187 115.905 127.457 ;
     RECT  118.515 127.187 118.605 127.457 ;
     RECT  121.215 127.187 121.305 127.457 ;
     RECT  123.915 127.187 124.005 127.457 ;
     RECT  126.615 127.187 126.705 127.457 ;
     RECT  129.315 127.187 129.405 127.457 ;
     RECT  132.015 127.187 132.105 127.457 ;
     RECT  134.715 127.187 134.805 127.457 ;
     RECT  137.415 127.187 137.505 127.457 ;
     RECT  140.115 127.187 140.205 127.457 ;
     RECT  142.815 127.187 142.905 127.457 ;
     RECT  145.515 127.187 145.605 127.457 ;
     RECT  148.215 127.187 148.305 127.457 ;
     RECT  150.915 127.187 151.005 127.457 ;
     RECT  153.615 127.187 153.705 127.457 ;
     RECT  156.315 127.187 156.405 127.457 ;
     RECT  159.015 127.187 159.105 127.457 ;
     RECT  161.715 127.187 161.805 127.457 ;
     RECT  164.415 127.187 164.505 127.457 ;
     RECT  167.115 127.187 167.205 127.457 ;
     RECT  169.815 127.187 169.905 127.457 ;
     RECT  172.515 127.187 172.605 127.457 ;
     RECT  175.215 127.187 175.305 127.457 ;
     RECT  177.915 127.187 178.005 127.457 ;
     RECT  180.615 127.187 180.705 127.457 ;
     RECT  183.315 127.187 183.405 127.457 ;
     RECT  186.015 127.187 186.105 127.457 ;
     RECT  188.715 127.187 188.805 127.457 ;
     RECT  191.415 127.187 191.505 127.457 ;
     RECT  194.115 127.187 194.205 127.457 ;
     RECT  196.815 127.187 196.905 127.457 ;
     RECT  199.515 127.187 199.605 127.457 ;
     RECT  202.215 127.187 202.305 127.457 ;
     RECT  204.915 127.187 205.005 127.457 ;
     RECT  207.615 127.187 207.705 127.457 ;
     RECT  210.315 127.187 210.405 127.457 ;
     RECT  213.015 127.187 213.105 127.457 ;
    LAYER M4 ;
     RECT  0.156 30.768 0.181 30.792 ;
     RECT  0.181 30.768 0.227 30.888 ;
     RECT  0.156 5.616 0.245 5.64 ;
     RECT  0.156 8.112 0.245 8.136 ;
     RECT  0.156 10.656 0.245 10.68 ;
     RECT  0.156 15.696 0.245 15.72 ;
     RECT  0.156 20.688 0.245 20.712 ;
     RECT  0.156 25.776 0.245 25.8 ;
     RECT  0.156 33.312 0.245 33.336 ;
     RECT  0.156 38.352 0.245 38.376 ;
     RECT  0.156 50.928 0.245 50.952 ;
     RECT  0.156 53.472 0.245 53.496 ;
     RECT  0.156 56.016 0.245 56.04 ;
     RECT  0.156 63.552 0.245 63.576 ;
     RECT  0.156 66.096 0.245 66.12 ;
     RECT  0.156 68.592 0.245 68.616 ;
     RECT  0.156 71.088 0.245 71.112 ;
     RECT  0.156 78.672 0.245 78.696 ;
     RECT  0.156 93.792 0.245 93.816 ;
     RECT  0.156 98.832 0.245 98.856 ;
     RECT  0.156 101.328 0.245 101.352 ;
     RECT  0.156 116.496 0.245 116.52 ;
     RECT  0.156 118.992 0.245 119.016 ;
     RECT  0.156 121.488 0.245 121.512 ;
     RECT  0.156 28.272 0.569 28.296 ;
     RECT  0.156 35.856 0.569 35.88 ;
     RECT  0.156 40.848 0.569 40.872 ;
     RECT  0.156 91.248 0.569 91.272 ;
     RECT  0.156 13.152 2.408 13.176 ;
     RECT  0.156 18.192 2.408 18.216 ;
     RECT  0.156 23.232 2.408 23.256 ;
     RECT  0.227 30.864 2.408 30.888 ;
     RECT  0.156 43.392 2.408 43.416 ;
     RECT  0.156 45.888 2.408 45.912 ;
     RECT  0.156 48.432 2.408 48.456 ;
     RECT  0.156 58.512 2.408 58.536 ;
     RECT  0.156 61.008 2.408 61.032 ;
     RECT  0.156 73.632 2.408 73.656 ;
     RECT  0.156 76.176 2.408 76.2 ;
     RECT  0.156 81.168 2.408 81.192 ;
     RECT  0.156 83.712 2.408 83.736 ;
     RECT  0.156 86.256 2.408 86.28 ;
     RECT  0.156 88.752 2.408 88.776 ;
     RECT  0.156 96.336 2.408 96.36 ;
     RECT  0.156 103.872 2.408 103.896 ;
     RECT  0.156 106.416 2.408 106.44 ;
     RECT  0.156 108.912 2.408 108.936 ;
     RECT  0.156 111.408 2.408 111.432 ;
     RECT  0.156 113.952 2.408 113.976 ;
     RECT  0.156 124.032 2.408 124.056 ;
     RECT  2.408 2.148 2.512 127.452 ;
     RECT  2.512 2.418 2.704 127.182 ;
     RECT  2.704 48.432 2.837 48.456 ;
     RECT  2.704 73.632 2.945 73.656 ;
     RECT  2.704 106.704 3.347 106.728 ;
     RECT  2.704 116.304 3.349 116.328 ;
     RECT  2.704 46.08 3.395 46.776 ;
     RECT  2.704 36 3.436 36.024 ;
     RECT  2.704 87.84 3.449 88.776 ;
     RECT  2.704 124.032 3.449 124.056 ;
     RECT  2.704 6.24 3.539 6.264 ;
     RECT  2.704 16.032 3.539 16.056 ;
     RECT  3.395 46.752 3.635 46.776 ;
     RECT  2.704 86.736 3.683 86.76 ;
     RECT  2.704 32.88 3.697 32.904 ;
     RECT  3.733 93.12 3.829 93.144 ;
     RECT  3.449 87.84 3.875 87.864 ;
     RECT  2.704 96.288 3.971 96.312 ;
     RECT  3.829 95.136 4.012 95.16 ;
     RECT  2.704 76.896 4.097 76.92 ;
     RECT  3.829 92.928 4.097 93.144 ;
     RECT  4.057 98.688 4.373 98.712 ;
     RECT  3.697 32.88 4.453 33.048 ;
     RECT  2.704 26.064 4.625 26.088 ;
     RECT  4.625 26.064 4.652 26.808 ;
     RECT  4.373 98.64 4.813 98.712 ;
     RECT  4.777 36 4.921 36.024 ;
     RECT  4.847 108.816 4.933 108.84 ;
     RECT  4.789 95.52 5.101 95.544 ;
     RECT  4.849 8.448 5.108 8.472 ;
     RECT  4.652 26.064 5.108 27.336 ;
     RECT  5.101 30.96 5.108 30.984 ;
     RECT  4.453 32.88 5.108 33.624 ;
     RECT  4.921 36 5.108 36.36 ;
     RECT  4.933 43.104 5.108 43.128 ;
     RECT  2.704 55.872 5.108 55.896 ;
     RECT  4.813 66.768 5.108 66.792 ;
     RECT  4.777 78.624 5.108 78.648 ;
     RECT  4.949 91.152 5.108 91.176 ;
     RECT  4.097 93.12 5.108 93.144 ;
     RECT  5.101 95.184 5.108 95.544 ;
     RECT  4.813 98.64 5.108 99.192 ;
     RECT  4.933 108.288 5.108 108.84 ;
     RECT  4.849 118.56 5.108 118.584 ;
     RECT  4.405 122.64 5.108 122.664 ;
     RECT  5.108 2.148 5.212 127.452 ;
     RECT  5.212 2.418 5.404 127.182 ;
     RECT  5.404 8.448 5.555 8.472 ;
     RECT  5.404 30 5.555 34.392 ;
     RECT  5.404 38.4 5.555 38.424 ;
     RECT  5.404 54.144 5.555 54.168 ;
     RECT  5.404 66.768 5.555 66.792 ;
     RECT  5.404 68.928 5.555 68.952 ;
     RECT  5.404 88.752 5.555 88.776 ;
     RECT  5.404 90.768 5.555 91.08 ;
     RECT  5.404 28.8 5.651 28.824 ;
     RECT  5.555 30 5.651 34.344 ;
     RECT  5.404 35.808 5.651 36.36 ;
     RECT  5.404 16.512 5.699 16.536 ;
     RECT  5.404 98.64 5.969 98.664 ;
     RECT  5.404 48.384 6.005 48.504 ;
     RECT  5.404 18.432 6.083 19.08 ;
     RECT  5.651 31.488 6.149 34.344 ;
     RECT  6.149 32.928 6.179 34.344 ;
     RECT  6.005 48.384 6.323 48.408 ;
     RECT  5.404 50.736 6.329 51.144 ;
     RECT  6.329 51.12 6.371 51.144 ;
     RECT  5.404 58.128 6.371 58.152 ;
     RECT  5.555 91.008 6.371 91.08 ;
     RECT  5.404 95.184 6.371 95.208 ;
     RECT  5.404 43.104 6.397 43.128 ;
     RECT  6.179 33.024 6.467 34.344 ;
     RECT  5.404 122.64 6.469 122.664 ;
     RECT  6.467 33.456 6.508 34.344 ;
     RECT  6.428 71.04 6.515 71.064 ;
     RECT  6.469 111.168 6.553 111.192 ;
     RECT  6.371 91.056 6.565 91.08 ;
     RECT  6.431 101.28 6.611 101.304 ;
     RECT  5.404 86.592 6.613 86.616 ;
     RECT  6.613 11.376 6.697 11.4 ;
     RECT  6.433 48.336 6.757 48.36 ;
     RECT  6.149 31.488 6.761 31.512 ;
     RECT  5.404 40.56 6.797 40.728 ;
     RECT  6.613 85.968 6.805 86.616 ;
     RECT  5.651 30 6.853 30.024 ;
     RECT  5.651 36.336 6.86 36.36 ;
     RECT  6.397 42.288 6.86 43.128 ;
     RECT  6.973 20.976 7.141 21 ;
     RECT  6.757 38.736 7.247 38.76 ;
     RECT  7.237 31.536 7.429 31.56 ;
     RECT  6.508 33.456 7.429 33.48 ;
     RECT  7.247 38.64 7.429 38.76 ;
     RECT  6.469 121.968 7.429 122.664 ;
     RECT  6.86 35.616 7.58 36.36 ;
     RECT  7.429 38.112 7.58 38.76 ;
     RECT  7.429 31.536 7.621 33.48 ;
     RECT  7.58 34.896 7.621 36.36 ;
     RECT  6.86 42.288 7.621 43.32 ;
     RECT  7.621 42.288 7.669 43.416 ;
     RECT  7.669 83.76 7.729 83.784 ;
     RECT  7.081 11.76 7.808 11.784 ;
     RECT  6.083 19.056 7.808 19.08 ;
     RECT  7.141 20.976 7.808 21.384 ;
     RECT  6.853 29.904 7.808 30.024 ;
     RECT  7.621 31.536 7.808 36.36 ;
     RECT  7.58 38.112 7.808 39.048 ;
     RECT  7.117 40.512 7.808 40.536 ;
     RECT  7.669 42.288 7.808 44.136 ;
     RECT  6.757 47.856 7.808 48.36 ;
     RECT  7.669 51.12 7.808 51.144 ;
     RECT  7.669 53.904 7.808 53.928 ;
     RECT  7.669 57.312 7.808 57.336 ;
     RECT  6.469 60.96 7.808 60.984 ;
     RECT  7.669 63.6 7.808 63.624 ;
     RECT  7.045 68.736 7.808 68.76 ;
     RECT  7.669 71.088 7.808 71.112 ;
     RECT  7.669 73.824 7.808 73.848 ;
     RECT  5.404 78.624 7.808 78.648 ;
     RECT  6.764 81.264 7.808 81.288 ;
     RECT  7.729 83.76 7.808 83.832 ;
     RECT  6.805 85.632 7.808 86.616 ;
     RECT  6.764 88.848 7.808 88.872 ;
     RECT  6.565 91.056 7.808 91.512 ;
     RECT  7.429 94.416 7.808 94.44 ;
     RECT  7.429 100.656 7.808 100.68 ;
     RECT  7.429 103.728 7.808 103.752 ;
     RECT  7.429 121.968 7.808 123.768 ;
     RECT  7.808 2.148 7.912 127.452 ;
     RECT  7.912 2.418 8.104 127.182 ;
     RECT  8.104 31.776 8.237 31.8 ;
     RECT  8.104 13.392 8.243 14.232 ;
     RECT  8.104 82.656 8.243 83.832 ;
     RECT  8.104 29.664 8.245 30.024 ;
     RECT  8.243 83.808 8.339 83.832 ;
     RECT  8.104 114 8.387 114.024 ;
     RECT  8.104 56.448 8.425 56.472 ;
     RECT  8.104 85.968 8.435 87.288 ;
     RECT  8.435 86.64 8.461 87.288 ;
     RECT  8.245 29.664 8.483 29.688 ;
     RECT  8.104 42.048 8.483 45.48 ;
     RECT  8.104 52.704 8.483 53.592 ;
     RECT  8.104 93.696 8.483 93.72 ;
     RECT  8.104 103.344 8.483 103.368 ;
     RECT  8.104 23.568 8.524 23.592 ;
     RECT  8.243 14.208 8.533 14.232 ;
     RECT  8.104 63.216 8.627 63.24 ;
     RECT  8.104 81.264 8.627 81.624 ;
     RECT  8.243 82.656 8.641 82.68 ;
     RECT  8.104 74.064 8.668 74.088 ;
     RECT  8.104 77.76 8.675 77.928 ;
     RECT  8.104 91.056 8.675 91.08 ;
     RECT  8.104 66.24 8.705 66.936 ;
     RECT  8.461 86.64 8.741 87.192 ;
     RECT  8.483 45.456 9.021 45.48 ;
     RECT  8.104 36.336 9.097 40.44 ;
     RECT  9.097 36.096 9.109 40.44 ;
     RECT  8.104 32.976 9.157 34.104 ;
     RECT  8.104 24.624 9.203 24.648 ;
     RECT  9.157 32.64 9.205 34.104 ;
     RECT  8.483 53.568 9.281 53.592 ;
     RECT  9.205 31.92 9.313 34.104 ;
     RECT  9.205 30.816 9.353 30.84 ;
     RECT  8.705 66.24 9.353 66.264 ;
     RECT  9.109 35.904 9.389 40.44 ;
     RECT  9.313 31.92 9.781 34.776 ;
     RECT  9.389 35.904 9.781 39.912 ;
     RECT  8.483 42.048 9.781 44.424 ;
     RECT  9.829 55.968 9.853 55.992 ;
     RECT  9.781 31.92 10.357 39.912 ;
     RECT  9.781 41.184 10.357 44.424 ;
     RECT  10.309 106.272 10.357 106.296 ;
     RECT  10.393 26.352 10.465 26.376 ;
     RECT  10.357 31.92 10.465 44.424 ;
     RECT  10.465 26.352 10.508 26.76 ;
     RECT  10.349 30.624 10.508 30.648 ;
     RECT  10.465 31.92 10.508 44.472 ;
     RECT  10.316 45.456 10.508 45.48 ;
     RECT  10.316 53.184 10.508 53.208 ;
     RECT  10.285 54.72 10.508 54.744 ;
     RECT  9.853 55.872 10.508 55.992 ;
     RECT  9.313 57.024 10.508 57.048 ;
     RECT  8.104 59.76 10.508 59.784 ;
     RECT  10.261 66.72 10.508 66.744 ;
     RECT  10.309 68.64 10.508 68.664 ;
     RECT  10.357 71.232 10.508 71.256 ;
     RECT  10.309 74.064 10.508 74.088 ;
     RECT  8.675 77.904 10.508 77.928 ;
     RECT  8.627 81.6 10.508 81.624 ;
     RECT  10.357 106.272 10.508 107.016 ;
     RECT  10.508 2.148 10.612 127.452 ;
     RECT  10.612 2.418 10.804 127.182 ;
     RECT  10.804 26.352 10.865 26.376 ;
     RECT  10.804 39.408 10.865 43.32 ;
     RECT  10.804 44.352 10.865 44.664 ;
     RECT  10.804 56.496 11.027 56.52 ;
     RECT  10.865 44.64 11.123 44.664 ;
     RECT  10.804 54.096 11.123 54.12 ;
     RECT  10.804 29.616 11.267 29.64 ;
     RECT  10.804 31.92 11.267 38.424 ;
     RECT  10.804 59.76 11.405 59.784 ;
     RECT  10.804 53.088 11.513 53.112 ;
     RECT  11.267 31.92 11.657 32.232 ;
     RECT  11.267 33.984 11.693 38.424 ;
     RECT  10.804 57.6 11.797 57.624 ;
     RECT  11.693 35.712 11.869 38.424 ;
     RECT  10.865 39.408 11.869 39.432 ;
     RECT  10.865 40.416 11.977 43.32 ;
     RECT  11.869 35.712 12.013 39.432 ;
     RECT  11.977 40.416 12.013 43.896 ;
     RECT  11.797 57.072 12.013 57.624 ;
     RECT  12.013 57.072 12.113 58.2 ;
     RECT  12.013 35.712 12.181 43.896 ;
     RECT  12.113 57.072 12.197 58.728 ;
     RECT  12.181 35.712 12.227 44.616 ;
     RECT  12.227 44.592 12.229 44.616 ;
     RECT  12.013 47.856 12.229 47.88 ;
     RECT  11.693 33.984 12.421 34.488 ;
     RECT  12.121 30.48 12.469 31.224 ;
     RECT  11.657 32.208 12.469 32.232 ;
     RECT  12.421 33.6 12.469 34.488 ;
     RECT  12.188 52.704 12.481 52.728 ;
     RECT  12.197 57.072 12.553 58.2 ;
     RECT  12.469 32.208 12.853 34.488 ;
     RECT  12.227 35.712 12.853 43.272 ;
     RECT  12.229 47.76 12.949 47.88 ;
     RECT  12.469 30.144 13.201 31.224 ;
     RECT  12.853 32.208 13.201 43.272 ;
     RECT  13.201 30.144 13.208 43.272 ;
     RECT  12.229 44.592 13.208 44.952 ;
     RECT  12.949 47.28 13.208 47.88 ;
     RECT  12.481 52.704 13.208 53.544 ;
     RECT  12.553 57.024 13.208 58.2 ;
     RECT  12.908 59.808 13.208 59.832 ;
     RECT  10.804 77.904 13.208 77.928 ;
     RECT  10.804 81.6 13.208 81.624 ;
     RECT  10.804 106.416 13.208 107.016 ;
     RECT  13.208 2.148 13.312 127.452 ;
     RECT  13.312 2.418 13.504 127.182 ;
     RECT  13.504 77.904 13.619 77.928 ;
     RECT  13.504 58.128 13.645 58.68 ;
     RECT  13.504 52.272 13.667 53.208 ;
     RECT  13.645 58.128 13.667 58.2 ;
     RECT  13.667 53.136 13.781 53.208 ;
     RECT  13.504 46.752 14.041 47.88 ;
     RECT  13.504 30.96 14.069 43.272 ;
     RECT  14.069 30.96 14.141 39.816 ;
     RECT  14.141 32.592 14.213 36.36 ;
     RECT  13.504 54.864 14.285 56.52 ;
     RECT  14.285 55.152 14.321 56.52 ;
     RECT  13.781 53.184 14.531 53.208 ;
     RECT  14.321 56.496 14.531 56.52 ;
     RECT  14.041 47.568 14.645 47.88 ;
     RECT  14.069 40.848 14.861 43.272 ;
     RECT  13.504 106.416 14.861 107.016 ;
     RECT  14.645 47.568 14.933 47.592 ;
     RECT  14.141 37.392 15.145 39.768 ;
     RECT  14.141 30.96 15.289 31.464 ;
     RECT  15.145 37.392 15.325 39.816 ;
     RECT  14.861 40.848 15.325 43.128 ;
     RECT  15.289 30.672 15.397 31.464 ;
     RECT  15.325 37.392 15.397 43.128 ;
     RECT  14.213 33.072 15.541 36.36 ;
     RECT  15.397 37.344 15.541 43.128 ;
     RECT  15.397 30.672 15.781 31.8 ;
     RECT  15.781 30.672 15.908 32.088 ;
     RECT  15.541 33.072 15.908 43.128 ;
     RECT  15.5 46.848 15.908 46.872 ;
     RECT  14.321 55.152 15.908 55.176 ;
     RECT  13.667 58.176 15.908 58.2 ;
     RECT  14.861 106.512 15.908 107.016 ;
     RECT  15.908 2.148 16.012 127.452 ;
     RECT  16.012 2.418 16.204 127.182 ;
     RECT  16.204 30.48 16.301 39.816 ;
     RECT  16.301 32.544 16.409 39.816 ;
     RECT  16.301 30.48 16.445 31.224 ;
     RECT  16.409 35.328 16.739 38.952 ;
     RECT  16.739 35.76 17.129 38.952 ;
     RECT  16.445 30.48 17.171 30.984 ;
     RECT  16.409 32.544 17.173 34.344 ;
     RECT  17.171 30.96 17.273 30.984 ;
     RECT  16.204 40.848 17.557 43.128 ;
     RECT  17.129 35.76 17.797 38.472 ;
     RECT  17.557 40.032 18.38 43.128 ;
     RECT  17.797 35.424 18.421 38.472 ;
     RECT  18.38 39.552 18.421 43.368 ;
     RECT  18.277 31.776 18.608 31.8 ;
     RECT  17.173 33.36 18.608 34.344 ;
     RECT  18.421 35.424 18.608 43.368 ;
     RECT  16.204 106.512 18.608 107.016 ;
     RECT  18.608 2.148 18.712 127.452 ;
     RECT  18.712 2.418 18.904 127.182 ;
     RECT  18.904 34.224 19.427 34.248 ;
     RECT  18.904 33.024 19.541 33.048 ;
     RECT  18.904 35.328 19.577 38.808 ;
     RECT  19.577 35.328 20.041 38.52 ;
     RECT  20.053 39.744 20.189 39.768 ;
     RECT  18.904 40.848 20.389 43.08 ;
     RECT  20.005 44.448 20.389 44.472 ;
     RECT  20.041 34.416 20.761 38.52 ;
     RECT  20.389 40.848 20.917 44.472 ;
     RECT  20.761 34.224 21.013 38.52 ;
     RECT  21.109 33.024 21.308 33.048 ;
     RECT  21.013 34.224 21.308 38.76 ;
     RECT  20.917 40.416 21.308 44.472 ;
     RECT  18.904 106.416 21.308 107.016 ;
     RECT  21.308 2.148 21.412 127.452 ;
     RECT  21.412 2.418 21.604 127.182 ;
     RECT  21.604 36.528 21.665 45.624 ;
     RECT  21.604 33.024 21.701 34.824 ;
     RECT  21.665 37.392 21.917 45.624 ;
     RECT  21.701 33.12 22.421 34.824 ;
     RECT  21.917 41.376 22.529 45.624 ;
     RECT  22.529 41.376 22.565 44.472 ;
     RECT  22.421 33.408 22.844 34.824 ;
     RECT  21.917 37.392 22.921 39.816 ;
     RECT  22.844 33.408 22.931 35.016 ;
     RECT  22.885 36.096 23.209 36.12 ;
     RECT  22.921 37.104 23.209 39.816 ;
     RECT  22.931 33.408 23.461 34.152 ;
     RECT  22.529 45.552 23.569 45.624 ;
     RECT  22.885 31.776 23.605 31.8 ;
     RECT  23.461 32.832 23.605 34.152 ;
     RECT  23.209 36.096 23.852 39.816 ;
     RECT  22.565 41.376 23.852 44.424 ;
     RECT  23.605 31.776 24.008 34.152 ;
     RECT  23.852 36.096 24.008 44.424 ;
     RECT  23.569 45.552 24.008 46.2 ;
     RECT  21.604 106.416 24.008 107.016 ;
     RECT  24.008 2.148 24.112 127.452 ;
     RECT  24.112 2.418 24.304 127.182 ;
     RECT  24.304 32.016 24.803 40.2 ;
     RECT  24.304 43.92 24.803 44.472 ;
     RECT  24.304 45.504 24.977 46.2 ;
     RECT  24.977 46.176 25.265 46.2 ;
     RECT  24.304 41.376 25.388 42.792 ;
     RECT  25.388 41.184 25.475 42.792 ;
     RECT  24.803 32.016 25.669 39.816 ;
     RECT  24.803 44.16 25.801 44.472 ;
     RECT  25.801 44.16 25.945 45.096 ;
     RECT  25.475 41.376 26.125 42.792 ;
     RECT  25.945 43.776 26.125 45.48 ;
     RECT  25.669 31.92 26.593 39.816 ;
     RECT  25.909 3.408 26.708 3.432 ;
     RECT  26.593 31.92 26.708 39.864 ;
     RECT  26.125 41.376 26.708 45.48 ;
     RECT  24.304 106.512 26.708 107.016 ;
     RECT  26.708 2.148 26.812 127.452 ;
     RECT  26.812 2.418 27.004 127.182 ;
     RECT  27.004 31.776 27.155 31.8 ;
     RECT  27.004 37.488 27.569 45.624 ;
     RECT  27.004 33.648 27.929 36.12 ;
     RECT  27.929 35.28 27.997 36.12 ;
     RECT  27.569 37.488 27.997 39.384 ;
     RECT  27.929 33.648 28.309 34.2 ;
     RECT  28.309 33.312 28.321 34.2 ;
     RECT  27.569 40.416 28.355 45.624 ;
     RECT  28.321 33.072 28.357 34.2 ;
     RECT  28.357 32.112 28.444 34.2 ;
     RECT  28.444 33.024 28.997 34.2 ;
     RECT  27.997 35.28 28.997 39.384 ;
     RECT  29.269 3.408 29.408 3.432 ;
     RECT  28.997 33.024 29.408 39.384 ;
     RECT  28.355 40.416 29.408 44.712 ;
     RECT  28.933 46.176 29.408 46.2 ;
     RECT  27.004 106.512 29.408 107.016 ;
     RECT  29.408 2.148 29.512 127.452 ;
     RECT  29.512 2.418 29.704 127.182 ;
     RECT  29.704 42 30.197 45.576 ;
     RECT  29.704 33.504 30.413 34.2 ;
     RECT  29.704 35.424 30.413 39.096 ;
     RECT  30.413 34.128 30.733 34.2 ;
     RECT  29.704 106.416 30.809 107.016 ;
     RECT  30.197 42 30.949 44.904 ;
     RECT  30.413 36.24 31.045 39.096 ;
     RECT  31.045 36.24 31.229 39.384 ;
     RECT  31.229 36.24 31.525 39.432 ;
     RECT  29.704 40.416 31.525 40.92 ;
     RECT  31.525 36.24 31.669 40.92 ;
     RECT  30.949 41.904 31.669 44.904 ;
     RECT  30.733 34.128 31.813 34.776 ;
     RECT  31.669 36.24 31.849 44.904 ;
     RECT  31.849 35.856 32.029 44.904 ;
     RECT  31.129 46.752 32.029 46.776 ;
     RECT  31.813 33.6 32.108 34.776 ;
     RECT  32.029 35.856 32.108 46.776 ;
     RECT  30.809 106.512 32.108 107.016 ;
     RECT  32.108 2.148 32.212 127.452 ;
     RECT  32.212 2.418 32.404 127.182 ;
     RECT  32.404 35.904 32.545 47.016 ;
     RECT  32.404 33.6 32.645 34.776 ;
     RECT  32.545 36.528 32.825 47.016 ;
     RECT  32.825 36.528 32.933 37.704 ;
     RECT  32.933 36.528 33.041 37.56 ;
     RECT  32.825 38.784 33.257 47.016 ;
     RECT  32.645 33.6 33.509 34.2 ;
     RECT  33.509 34.176 33.721 34.2 ;
     RECT  33.721 34.176 33.805 34.68 ;
     RECT  33.041 36.528 34.081 37.368 ;
     RECT  34.081 36.384 34.189 37.368 ;
     RECT  33.257 38.784 34.189 43.128 ;
     RECT  34.189 36.384 34.253 43.128 ;
     RECT  33.257 44.16 34.253 47.016 ;
     RECT  34.253 36.384 34.549 47.016 ;
     RECT  34.549 36.24 34.693 47.016 ;
     RECT  33.805 34.176 34.808 34.2 ;
     RECT  34.693 36.24 34.808 47.352 ;
     RECT  32.404 106.512 34.808 107.016 ;
     RECT  34.808 2.148 34.912 127.452 ;
     RECT  34.912 2.418 35.104 127.182 ;
     RECT  35.104 36.24 35.309 48.024 ;
     RECT  35.309 36.432 36.245 48.024 ;
     RECT  36.245 36.528 37.508 48.024 ;
     RECT  35.104 106.512 37.508 107.016 ;
     RECT  37.508 2.148 37.612 127.452 ;
     RECT  37.612 2.418 37.804 127.182 ;
     RECT  37.804 40.032 37.955 40.344 ;
     RECT  37.804 36.288 38.225 37.128 ;
     RECT  38.225 36.288 39.445 36.84 ;
     RECT  39.445 36.288 40.208 37.368 ;
     RECT  40.208 2.148 40.312 37.812 ;
     RECT  40.208 111.768 40.312 127.452 ;
     RECT  40.312 111.768 40.4 127.182 ;
     RECT  40.312 2.418 40.504 37.656 ;
     RECT  40.4 111.498 40.504 127.182 ;
     RECT  40.504 36.288 41.069 37.656 ;
     RECT  41.069 36.288 41.861 36.936 ;
     RECT  41.861 36.912 42.908 36.936 ;
     RECT  37.804 44.064 42.937 48.024 ;
     RECT  42.908 2.148 43.012 37.812 ;
     RECT  42.908 111.768 43.012 127.452 ;
     RECT  43.012 111.768 43.1 127.182 ;
     RECT  43.012 2.418 43.204 37.542 ;
     RECT  43.1 111.498 43.204 127.182 ;
     RECT  37.804 42 43.272 42.6 ;
     RECT  42.937 43.968 43.272 48.024 ;
     RECT  37.804 106.416 43.272 107.016 ;
     RECT  45.608 2.148 45.712 37.812 ;
     RECT  45.608 111.768 45.712 127.452 ;
     RECT  45.712 111.768 45.8 127.182 ;
     RECT  45.712 2.418 45.904 37.542 ;
     RECT  45.8 111.498 45.904 127.182 ;
     RECT  48.308 2.148 48.412 37.812 ;
     RECT  48.308 111.768 48.412 127.452 ;
     RECT  48.412 111.768 48.5 127.182 ;
     RECT  48.412 2.418 48.604 37.542 ;
     RECT  48.5 111.498 48.604 127.182 ;
     RECT  51.008 2.148 51.112 37.812 ;
     RECT  51.008 111.768 51.112 127.452 ;
     RECT  51.112 111.768 51.2 127.182 ;
     RECT  51.112 2.418 51.304 37.542 ;
     RECT  51.2 111.498 51.304 127.182 ;
     RECT  53.708 2.148 53.812 37.812 ;
     RECT  53.708 111.768 53.812 127.452 ;
     RECT  53.812 111.768 53.9 127.182 ;
     RECT  53.812 2.418 54.004 37.542 ;
     RECT  53.9 111.498 54.004 127.182 ;
     RECT  55.177 35.712 56.408 35.736 ;
     RECT  56.408 2.148 56.512 37.812 ;
     RECT  56.408 111.768 56.512 127.452 ;
     RECT  56.512 111.768 56.6 127.182 ;
     RECT  56.512 2.418 56.704 37.542 ;
     RECT  56.6 111.498 56.704 127.182 ;
     RECT  56.704 35.712 59.108 35.736 ;
     RECT  58.453 37.056 59.108 37.08 ;
     RECT  59.108 2.148 59.212 37.812 ;
     RECT  59.108 111.768 59.212 127.452 ;
     RECT  59.212 111.768 59.3 127.182 ;
     RECT  59.212 2.418 59.404 37.608 ;
     RECT  59.3 111.498 59.404 127.182 ;
     RECT  59.404 37.584 60.085 37.608 ;
     RECT  59.404 35.712 61.513 35.736 ;
     RECT  61.513 35.712 61.808 35.784 ;
     RECT  61.045 37.44 61.808 37.464 ;
     RECT  61.808 2.148 61.912 37.812 ;
     RECT  61.808 111.768 61.912 127.452 ;
     RECT  61.912 111.768 62 127.182 ;
     RECT  61.912 2.418 62.104 37.608 ;
     RECT  62 111.498 62.104 127.182 ;
     RECT  62.104 37.44 62.777 37.608 ;
     RECT  62.104 35.76 64.508 35.784 ;
     RECT  62.777 37.584 64.508 37.608 ;
     RECT  64.508 2.148 64.612 37.812 ;
     RECT  64.508 111.768 64.612 127.452 ;
     RECT  64.612 111.768 64.7 127.182 ;
     RECT  64.612 2.418 64.804 37.608 ;
     RECT  64.7 111.498 64.804 127.182 ;
     RECT  66.265 1.728 66.563 1.752 ;
     RECT  64.804 37.584 67.129 37.608 ;
     RECT  64.804 2.88 67.208 2.904 ;
     RECT  64.804 35.76 67.208 35.784 ;
     RECT  67.129 37.44 67.208 37.608 ;
     RECT  67.208 2.148 67.312 37.812 ;
     RECT  67.208 111.768 67.312 127.452 ;
     RECT  67.312 111.768 67.4 127.182 ;
     RECT  67.312 2.418 67.504 37.608 ;
     RECT  67.4 111.498 67.504 127.182 ;
     RECT  37.955 40.032 67.619 40.056 ;
     RECT  67.504 2.88 69.908 2.904 ;
     RECT  67.504 35.712 69.908 35.784 ;
     RECT  67.504 37.44 69.908 37.608 ;
     RECT  69.908 2.148 70.012 37.812 ;
     RECT  69.908 111.768 70.012 127.452 ;
     RECT  70.012 111.768 70.1 127.182 ;
     RECT  70.012 2.418 70.204 37.608 ;
     RECT  70.1 111.498 70.204 127.182 ;
     RECT  70.204 2.88 72.608 2.904 ;
     RECT  70.204 35.712 72.608 35.784 ;
     RECT  70.204 37.44 72.608 37.608 ;
     RECT  72.608 2.148 72.712 37.812 ;
     RECT  72.608 111.768 72.712 127.452 ;
     RECT  72.712 111.768 72.8 127.182 ;
     RECT  72.712 2.418 72.904 37.608 ;
     RECT  72.8 111.498 72.904 127.182 ;
     RECT  72.904 2.88 75.308 2.904 ;
     RECT  72.904 35.712 75.308 35.784 ;
     RECT  72.904 37.44 75.308 37.608 ;
     RECT  75.308 2.148 75.412 37.812 ;
     RECT  75.308 111.768 75.412 127.452 ;
     RECT  75.412 111.768 75.5 127.182 ;
     RECT  75.412 2.418 75.604 37.608 ;
     RECT  75.5 111.498 75.604 127.182 ;
     RECT  75.604 2.88 78.008 2.904 ;
     RECT  75.604 35.712 78.008 35.784 ;
     RECT  75.604 37.44 78.008 37.608 ;
     RECT  78.008 2.148 78.112 37.812 ;
     RECT  78.008 111.768 78.112 127.452 ;
     RECT  78.112 111.768 78.2 127.182 ;
     RECT  78.112 2.418 78.304 37.608 ;
     RECT  78.2 111.498 78.304 127.182 ;
     RECT  78.304 37.392 78.761 37.608 ;
     RECT  79.333 28.176 79.628 28.2 ;
     RECT  78.304 2.88 79.715 2.904 ;
     RECT  79.628 27.888 79.715 28.2 ;
     RECT  78.761 37.392 80.125 37.56 ;
     RECT  79.715 28.176 80.708 28.2 ;
     RECT  78.304 35.712 80.708 35.784 ;
     RECT  80.125 37.152 80.708 37.56 ;
     RECT  80.708 2.148 80.812 37.812 ;
     RECT  80.708 111.768 80.812 127.452 ;
     RECT  80.812 111.768 80.9 127.182 ;
     RECT  80.812 2.418 81.004 37.56 ;
     RECT  80.9 111.498 81.004 127.182 ;
     RECT  43.272 42 81.144 107.016 ;
     RECT  81.144 43.968 81.216 48.024 ;
     RECT  81.216 43.968 81.353 45.048 ;
     RECT  81.144 42 81.395 42.792 ;
     RECT  81.004 37.152 82.645 37.56 ;
     RECT  81.004 28.176 83.408 28.2 ;
     RECT  81.004 35.712 83.408 35.784 ;
     RECT  82.645 37.152 83.408 37.608 ;
     RECT  83.408 2.148 83.512 37.812 ;
     RECT  83.408 111.768 83.512 127.452 ;
     RECT  83.512 111.768 83.6 127.182 ;
     RECT  83.512 2.418 83.704 37.608 ;
     RECT  83.6 111.498 83.704 127.182 ;
     RECT  83.704 28.176 86.108 28.2 ;
     RECT  83.704 35.712 86.108 35.784 ;
     RECT  83.704 37.392 86.108 37.608 ;
     RECT  86.108 2.148 86.212 37.812 ;
     RECT  86.108 111.768 86.212 127.452 ;
     RECT  86.212 111.768 86.3 127.182 ;
     RECT  86.212 2.418 86.404 37.608 ;
     RECT  86.3 111.498 86.404 127.182 ;
     RECT  86.404 37.296 86.609 37.608 ;
     RECT  86.404 35.712 86.629 35.88 ;
     RECT  81.144 106.416 86.681 107.016 ;
     RECT  81.353 44.064 86.783 45.048 ;
     RECT  81.395 42 86.917 42.6 ;
     RECT  86.404 28.176 86.963 28.2 ;
     RECT  86.609 37.44 86.969 37.608 ;
     RECT  86.629 35.76 87.004 35.88 ;
     RECT  86.783 43.872 87.005 45.048 ;
     RECT  87.005 45.024 88.213 45.048 ;
     RECT  87.004 35.76 88.808 35.784 ;
     RECT  86.969 37.536 88.808 37.608 ;
     RECT  86.917 42 88.808 42.744 ;
     RECT  87.005 43.872 88.808 43.896 ;
     RECT  88.213 45.024 88.808 45.288 ;
     RECT  86.681 106.512 88.808 107.016 ;
     RECT  88.808 2.148 88.912 127.452 ;
     RECT  88.912 2.418 89.104 127.182 ;
     RECT  89.104 35.76 91.508 35.784 ;
     RECT  89.104 37.584 91.508 37.608 ;
     RECT  89.104 42 91.508 42.744 ;
     RECT  89.104 43.872 91.508 43.896 ;
     RECT  89.104 45.024 91.508 45.288 ;
     RECT  89.104 106.512 91.508 107.016 ;
     RECT  91.508 2.148 91.612 127.452 ;
     RECT  91.612 2.418 91.804 127.182 ;
     RECT  91.804 41.232 93.769 42.744 ;
     RECT  91.804 45.024 93.841 45.288 ;
     RECT  91.804 35.76 94.208 35.784 ;
     RECT  91.804 37.584 94.208 37.608 ;
     RECT  93.769 41.232 94.208 43.368 ;
     RECT  93.841 44.4 94.208 45.288 ;
     RECT  91.804 106.512 94.208 107.016 ;
     RECT  94.208 2.148 94.312 127.452 ;
     RECT  94.312 2.418 94.504 127.182 ;
     RECT  94.504 41.232 94.739 45.624 ;
     RECT  94.739 42 94.979 45.624 ;
     RECT  94.979 42 95.141 42.888 ;
     RECT  94.979 43.92 95.821 45.624 ;
     RECT  95.141 42 95.929 42.6 ;
     RECT  95.821 43.92 96.145 45.864 ;
     RECT  95.929 41.616 96.181 42.6 ;
     RECT  96.145 43.92 96.181 46.392 ;
     RECT  94.504 35.76 96.908 35.784 ;
     RECT  94.504 37.584 96.908 37.608 ;
     RECT  96.181 41.616 96.908 46.392 ;
     RECT  94.504 106.416 96.908 107.016 ;
     RECT  96.908 2.148 97.012 127.452 ;
     RECT  97.012 2.418 97.204 127.182 ;
     RECT  97.204 44.016 97.301 45.768 ;
     RECT  97.301 44.016 98.341 45.576 ;
     RECT  98.341 44.016 98.376 46.344 ;
     RECT  97.204 106.416 98.633 107.016 ;
     RECT  98.376 43.92 98.725 46.344 ;
     RECT  97.204 47.328 98.725 47.352 ;
     RECT  97.204 42 98.845 42.6 ;
     RECT  98.725 43.92 98.845 47.352 ;
     RECT  98.845 42 99.133 47.352 ;
     RECT  97.204 35.76 99.608 35.784 ;
     RECT  97.204 37.584 99.608 37.608 ;
     RECT  99.133 42 99.608 47.928 ;
     RECT  98.633 106.512 99.608 107.016 ;
     RECT  99.608 2.148 99.712 127.452 ;
     RECT  99.712 2.418 99.904 127.182 ;
     RECT  99.904 42 100.885 43.848 ;
     RECT  99.904 45.024 100.885 46.68 ;
     RECT  100.885 42 100.897 46.68 ;
     RECT  100.897 42 101.005 47.64 ;
     RECT  101.005 42 101.009 47.688 ;
     RECT  101.009 42 101.365 46.536 ;
     RECT  101.009 47.616 101.977 47.688 ;
     RECT  101.365 41.712 102.037 46.536 ;
     RECT  101.977 47.616 102.037 47.88 ;
     RECT  99.904 35.76 102.308 36.552 ;
     RECT  99.904 37.584 102.308 37.608 ;
     RECT  102.037 41.712 102.308 47.88 ;
     RECT  101.329 60.432 102.308 60.456 ;
     RECT  102.092 83.376 102.308 83.4 ;
     RECT  99.904 106.512 102.308 107.016 ;
     RECT  102.308 2.148 102.412 127.452 ;
     RECT  102.412 2.418 102.604 127.182 ;
     RECT  102.604 106.416 102.629 107.016 ;
     RECT  102.604 44.928 102.737 48.216 ;
     RECT  102.604 75.264 102.755 75.576 ;
     RECT  102.755 75.264 102.953 75.288 ;
     RECT  102.629 106.512 103.765 107.016 ;
     RECT  102.737 44.928 103.772 47.928 ;
     RECT  103.724 79.584 103.811 79.608 ;
     RECT  103.772 44.448 103.859 47.928 ;
     RECT  103.859 44.64 103.885 47.928 ;
     RECT  103.877 79.776 103.961 79.8 ;
     RECT  102.604 41.712 104.677 43.368 ;
     RECT  103.765 106.224 104.849 107.016 ;
     RECT  102.604 35.76 105.008 36.552 ;
     RECT  102.604 37.584 105.008 37.608 ;
     RECT  104.677 41.712 105.008 43.608 ;
     RECT  103.885 44.64 105.008 48.408 ;
     RECT  104.677 81.456 105.008 81.48 ;
     RECT  104.06 85.248 105.008 85.272 ;
     RECT  104.849 106.032 105.008 107.016 ;
     RECT  105.008 2.148 105.112 127.452 ;
     RECT  105.112 2.418 105.304 127.182 ;
     RECT  105.304 57.6 105.985 57.624 ;
     RECT  105.304 41.712 106.333 46.92 ;
     RECT  105.304 47.904 106.333 48.408 ;
     RECT  105.304 106.32 106.585 106.872 ;
     RECT  106.585 106.32 106.625 107.016 ;
     RECT  105.304 35.76 107.708 36.552 ;
     RECT  105.304 37.584 107.708 37.608 ;
     RECT  106.333 41.712 107.708 48.408 ;
     RECT  106.625 106.464 107.708 107.016 ;
     RECT  107.708 2.148 107.812 127.452 ;
     RECT  107.812 2.418 108.004 127.182 ;
     RECT  58.453 0.144 108.029 0.168 ;
     RECT  108.004 45.024 108.145 48.696 ;
     RECT  108.004 56.496 108.275 56.52 ;
     RECT  108.145 45.648 108.353 48.696 ;
     RECT  108.353 48.24 108.425 48.696 ;
     RECT  108.425 48.384 108.749 48.696 ;
     RECT  108.749 48.384 108.785 48.456 ;
     RECT  108.004 59.28 108.803 59.304 ;
     RECT  108.785 48.384 108.893 48.408 ;
     RECT  108.353 45.648 108.929 47.064 ;
     RECT  108.004 41.712 109.321 43.368 ;
     RECT  109.105 44.592 109.321 44.616 ;
     RECT  108.929 45.696 109.393 47.064 ;
     RECT  109.321 41.712 109.969 44.616 ;
     RECT  109.393 45.696 109.969 48.216 ;
     RECT  108.004 35.76 110.408 36.552 ;
     RECT  108.004 37.584 110.408 37.608 ;
     RECT  109.969 41.712 110.408 48.216 ;
     RECT  108.004 106.464 110.408 107.016 ;
     RECT  110.408 2.148 110.512 127.452 ;
     RECT  110.512 2.418 110.704 127.182 ;
     RECT  110.704 41.712 111.053 48.264 ;
     RECT  111.053 41.712 111.197 46.92 ;
     RECT  111.197 44.112 111.413 46.92 ;
     RECT  111.413 44.112 111.731 46.872 ;
     RECT  111.053 48.24 112.489 48.264 ;
     RECT  111.731 45.552 112.525 46.872 ;
     RECT  112.489 47.904 112.525 48.264 ;
     RECT  111.197 41.712 112.885 43.08 ;
     RECT  111.731 44.112 112.885 44.136 ;
     RECT  110.704 35.76 113.108 36.552 ;
     RECT  110.704 37.584 113.108 37.608 ;
     RECT  112.885 41.712 113.108 44.136 ;
     RECT  112.525 45.552 113.108 48.264 ;
     RECT  110.704 106.224 113.108 107.016 ;
     RECT  113.108 2.148 113.212 127.452 ;
     RECT  113.212 2.418 113.404 127.182 ;
     RECT  113.404 48.24 113.465 48.264 ;
     RECT  113.404 18.24 114.005 18.264 ;
     RECT  113.404 41.712 114.613 46.872 ;
     RECT  114.613 41.712 115.513 47.544 ;
     RECT  113.404 16.8 115.808 16.824 ;
     RECT  113.404 35.76 115.808 36.552 ;
     RECT  113.404 37.584 115.808 37.608 ;
     RECT  115.513 41.712 115.808 47.928 ;
     RECT  114.853 66.48 115.808 66.504 ;
     RECT  113.404 106.224 115.808 107.016 ;
     RECT  115.808 2.148 115.912 127.452 ;
     RECT  115.912 2.418 116.104 127.182 ;
     RECT  116.104 41.472 116.819 43.08 ;
     RECT  116.819 41.712 117.385 43.08 ;
     RECT  116.104 44.112 117.385 47.928 ;
     RECT  117.385 41.712 117.497 47.928 ;
     RECT  116.104 16.8 118.508 16.824 ;
     RECT  116.104 35.76 118.508 36.552 ;
     RECT  116.104 37.584 118.508 37.608 ;
     RECT  117.497 41.712 118.508 44.136 ;
     RECT  117.497 45.552 118.508 47.928 ;
     RECT  116.104 66.48 118.508 66.504 ;
     RECT  116.104 106.224 118.508 107.016 ;
     RECT  118.508 2.148 118.612 127.452 ;
     RECT  118.612 2.418 118.804 127.182 ;
     RECT  118.804 41.232 119.219 47.976 ;
     RECT  119.219 41.712 119.225 47.976 ;
     RECT  119.225 41.712 119.513 44.184 ;
     RECT  119.225 45.408 119.773 47.976 ;
     RECT  119.513 41.712 120.481 43.08 ;
     RECT  119.513 44.112 120.86 44.184 ;
     RECT  118.804 16.8 121.208 16.824 ;
     RECT  118.804 35.76 121.208 36.552 ;
     RECT  118.804 37.584 121.208 37.608 ;
     RECT  120.481 40.944 121.208 43.08 ;
     RECT  120.86 44.112 121.208 44.328 ;
     RECT  119.773 45.408 121.208 47.928 ;
     RECT  118.804 66.48 121.208 66.504 ;
     RECT  118.804 106.224 121.208 107.016 ;
     RECT  121.208 2.148 121.312 127.452 ;
     RECT  121.312 2.418 121.504 127.182 ;
     RECT  121.504 66.144 122.537 66.504 ;
     RECT  121.504 41.568 122.605 43.08 ;
     RECT  121.504 44.112 122.605 47.928 ;
     RECT  122.537 66.48 122.645 66.504 ;
     RECT  122.605 41.568 122.771 47.928 ;
     RECT  122.771 41.712 122.825 47.928 ;
     RECT  121.504 16.8 123.908 16.824 ;
     RECT  121.504 35.76 123.908 36.552 ;
     RECT  121.504 37.584 123.908 37.608 ;
     RECT  122.825 41.712 123.908 44.376 ;
     RECT  122.825 45.552 123.908 47.928 ;
     RECT  121.504 106.32 123.908 106.872 ;
     RECT  123.908 2.148 124.012 127.452 ;
     RECT  124.012 2.418 124.204 127.182 ;
     RECT  124.204 44.112 124.265 44.376 ;
     RECT  124.265 44.16 125.917 44.376 ;
     RECT  124.204 16.8 126.608 16.824 ;
     RECT  124.204 35.76 126.608 36.552 ;
     RECT  124.204 37.584 126.608 37.608 ;
     RECT  126.608 2.148 126.712 37.812 ;
     RECT  126.608 111.768 126.712 127.452 ;
     RECT  125.917 44.064 126.781 44.376 ;
     RECT  126.712 111.768 126.8 127.182 ;
     RECT  126.781 44.064 126.853 44.76 ;
     RECT  126.712 2.418 126.904 37.608 ;
     RECT  126.8 111.498 126.904 127.182 ;
     RECT  126.853 44.064 127.105 44.856 ;
     RECT  124.204 46.272 127.105 48.024 ;
     RECT  126.904 35.76 127.397 36.552 ;
     RECT  126.904 37.584 128.473 37.608 ;
     RECT  126.904 16.8 129.308 16.824 ;
     RECT  127.397 35.76 129.308 35.784 ;
     RECT  128.473 36.864 129.308 37.608 ;
     RECT  129.308 2.148 129.412 37.812 ;
     RECT  129.308 111.768 129.412 127.452 ;
     RECT  124.204 41.712 129.481 43.08 ;
     RECT  127.105 44.064 129.481 48.024 ;
     RECT  129.412 111.768 129.5 127.182 ;
     RECT  129.412 2.418 129.604 37.608 ;
     RECT  129.5 111.498 129.604 127.182 ;
     RECT  129.481 41.712 129.672 48.024 ;
     RECT  124.204 106.32 129.672 106.872 ;
     RECT  129.604 16.8 132.008 16.824 ;
     RECT  129.604 35.76 132.008 35.784 ;
     RECT  129.604 36.864 132.008 37.608 ;
     RECT  132.008 2.148 132.112 37.812 ;
     RECT  132.008 111.768 132.112 127.452 ;
     RECT  132.112 111.768 132.2 127.182 ;
     RECT  132.112 2.418 132.304 37.608 ;
     RECT  132.2 111.498 132.304 127.182 ;
     RECT  132.304 16.8 134.708 16.824 ;
     RECT  132.304 35.76 134.708 35.784 ;
     RECT  132.304 36.864 134.708 37.608 ;
     RECT  134.708 2.148 134.812 37.812 ;
     RECT  134.708 111.768 134.812 127.452 ;
     RECT  134.812 111.768 134.9 127.182 ;
     RECT  134.812 2.418 135.004 37.608 ;
     RECT  134.9 111.498 135.004 127.182 ;
     RECT  135.004 16.8 137.408 16.824 ;
     RECT  135.004 35.76 137.408 35.784 ;
     RECT  135.004 36.864 137.408 37.608 ;
     RECT  137.408 2.148 137.512 37.812 ;
     RECT  137.408 111.768 137.512 127.452 ;
     RECT  137.512 111.768 137.6 127.182 ;
     RECT  137.512 2.418 137.704 37.608 ;
     RECT  137.6 111.498 137.704 127.182 ;
     RECT  137.704 36.768 138.557 37.608 ;
     RECT  137.704 16.8 140.108 16.824 ;
     RECT  137.704 35.76 140.108 35.784 ;
     RECT  138.557 36.864 140.108 37.608 ;
     RECT  140.108 2.148 140.212 37.812 ;
     RECT  140.108 111.768 140.212 127.452 ;
     RECT  140.212 111.768 140.3 127.182 ;
     RECT  140.212 2.418 140.404 37.608 ;
     RECT  140.3 111.498 140.404 127.182 ;
     RECT  140.404 16.8 142.808 16.824 ;
     RECT  140.404 35.76 142.808 35.784 ;
     RECT  140.404 36.864 142.808 37.608 ;
     RECT  142.808 2.148 142.912 37.812 ;
     RECT  142.808 111.768 142.912 127.452 ;
     RECT  142.912 111.768 143 127.182 ;
     RECT  142.912 2.418 143.104 37.608 ;
     RECT  143 111.498 143.104 127.182 ;
     RECT  143.104 16.8 145.508 16.824 ;
     RECT  143.104 35.76 145.508 35.784 ;
     RECT  143.104 36.864 145.508 37.608 ;
     RECT  145.508 2.148 145.612 37.812 ;
     RECT  145.508 111.768 145.612 127.452 ;
     RECT  145.612 111.768 145.7 127.182 ;
     RECT  145.612 2.418 145.804 37.608 ;
     RECT  145.7 111.498 145.804 127.182 ;
     RECT  145.804 36.768 146.513 37.608 ;
     RECT  145.804 16.8 148.208 16.824 ;
     RECT  145.804 35.76 148.208 35.784 ;
     RECT  146.513 36.864 148.208 37.608 ;
     RECT  148.208 2.148 148.312 37.812 ;
     RECT  148.208 111.768 148.312 127.452 ;
     RECT  148.312 111.768 148.4 127.182 ;
     RECT  148.312 2.418 148.504 37.608 ;
     RECT  148.4 111.498 148.504 127.182 ;
     RECT  149.209 0.192 149.507 0.216 ;
     RECT  149.533 3.696 150.908 3.72 ;
     RECT  148.504 16.8 150.908 16.824 ;
     RECT  148.504 35.76 150.908 35.784 ;
     RECT  148.504 36.864 150.908 37.608 ;
     RECT  150.908 2.148 151.012 37.812 ;
     RECT  150.908 111.768 151.012 127.452 ;
     RECT  151.012 111.768 151.1 127.182 ;
     RECT  151.012 2.418 151.204 37.608 ;
     RECT  151.1 111.498 151.204 127.182 ;
     RECT  151.204 16.8 153.608 16.824 ;
     RECT  151.204 35.76 153.608 35.784 ;
     RECT  151.204 36.864 153.608 37.608 ;
     RECT  153.608 2.148 153.712 37.812 ;
     RECT  153.608 111.768 153.712 127.452 ;
     RECT  153.712 111.768 153.8 127.182 ;
     RECT  153.712 2.418 153.904 37.608 ;
     RECT  153.8 111.498 153.904 127.182 ;
     RECT  153.904 36.768 154.505 37.608 ;
     RECT  153.904 16.8 156.308 16.824 ;
     RECT  153.904 35.76 156.308 35.784 ;
     RECT  154.505 36.864 156.308 37.608 ;
     RECT  156.308 2.148 156.412 37.812 ;
     RECT  156.308 111.768 156.412 127.452 ;
     RECT  156.412 111.768 156.5 127.182 ;
     RECT  156.412 2.418 156.604 37.608 ;
     RECT  156.5 111.498 156.604 127.182 ;
     RECT  156.604 16.8 159.008 16.824 ;
     RECT  156.604 35.76 159.008 35.784 ;
     RECT  156.604 36.864 159.008 37.608 ;
     RECT  159.008 2.148 159.112 37.812 ;
     RECT  159.008 111.768 159.112 127.452 ;
     RECT  159.112 111.768 159.2 127.182 ;
     RECT  159.112 2.418 159.304 37.542 ;
     RECT  159.2 111.498 159.304 127.182 ;
     RECT  159.304 16.8 161.708 16.824 ;
     RECT  159.304 35.76 161.708 35.784 ;
     RECT  159.304 36.864 161.708 37.464 ;
     RECT  161.708 2.148 161.812 37.812 ;
     RECT  161.708 111.768 161.812 127.452 ;
     RECT  161.812 111.768 161.9 127.182 ;
     RECT  161.812 2.418 162.004 37.542 ;
     RECT  161.9 111.498 162.004 127.182 ;
     RECT  162.004 36.768 162.497 37.464 ;
     RECT  162.004 16.8 164.408 16.824 ;
     RECT  162.004 35.76 164.408 35.784 ;
     RECT  162.497 36.864 164.408 37.464 ;
     RECT  164.408 2.148 164.512 37.812 ;
     RECT  164.408 111.768 164.512 127.452 ;
     RECT  164.512 111.768 164.6 127.182 ;
     RECT  164.512 2.418 164.704 37.542 ;
     RECT  164.6 111.498 164.704 127.182 ;
     RECT  164.704 16.8 167.108 16.824 ;
     RECT  164.704 35.76 167.108 35.784 ;
     RECT  164.704 36.864 167.108 37.464 ;
     RECT  167.108 2.148 167.212 37.812 ;
     RECT  167.108 111.768 167.212 127.452 ;
     RECT  167.212 111.768 167.3 127.182 ;
     RECT  167.212 2.418 167.404 37.542 ;
     RECT  167.3 111.498 167.404 127.182 ;
     RECT  129.672 41.712 167.544 106.872 ;
     RECT  167.544 41.712 167.616 48.024 ;
     RECT  167.404 16.8 169.808 16.824 ;
     RECT  167.404 35.76 169.808 35.784 ;
     RECT  167.404 36.864 169.808 37.464 ;
     RECT  167.616 41.712 169.877 44.184 ;
     RECT  169.808 2.148 169.912 37.812 ;
     RECT  169.808 111.768 169.912 127.452 ;
     RECT  169.877 44.064 169.913 44.184 ;
     RECT  169.912 111.768 170 127.182 ;
     RECT  169.912 2.418 170.104 37.542 ;
     RECT  170 111.498 170.104 127.182 ;
     RECT  169.913 44.16 170.417 44.184 ;
     RECT  170.104 36.768 170.453 37.464 ;
     RECT  170.104 35.712 170.885 35.784 ;
     RECT  170.104 16.8 172.508 16.824 ;
     RECT  170.885 35.712 172.508 35.736 ;
     RECT  170.453 36.864 172.508 37.464 ;
     RECT  172.508 2.148 172.612 37.812 ;
     RECT  172.508 111.768 172.612 127.452 ;
     RECT  172.612 111.768 172.7 127.182 ;
     RECT  172.612 2.418 172.804 37.542 ;
     RECT  172.7 111.498 172.804 127.182 ;
     RECT  169.877 41.712 173.173 43.08 ;
     RECT  173.173 41.712 173.26 43.56 ;
     RECT  167.544 106.32 174.409 106.872 ;
     RECT  172.804 16.8 175.208 16.824 ;
     RECT  172.804 35.712 175.208 35.736 ;
     RECT  172.804 36.864 175.208 37.464 ;
     RECT  173.26 41.712 175.208 43.08 ;
     RECT  167.544 56.496 175.208 56.52 ;
     RECT  174.409 106.224 175.208 107.016 ;
     RECT  175.208 2.148 175.312 127.452 ;
     RECT  175.312 2.418 175.504 127.182 ;
     RECT  175.504 16.8 177.908 16.824 ;
     RECT  175.504 35.712 177.908 35.736 ;
     RECT  175.504 36.864 177.908 37.464 ;
     RECT  175.504 41.712 177.908 43.08 ;
     RECT  175.504 56.496 177.908 56.52 ;
     RECT  175.504 106.224 177.908 107.016 ;
     RECT  177.908 2.148 178.012 127.452 ;
     RECT  178.012 2.418 178.204 127.182 ;
     RECT  178.204 36.768 178.445 37.464 ;
     RECT  178.204 16.8 180.608 16.824 ;
     RECT  178.204 35.712 180.608 35.736 ;
     RECT  178.445 36.864 180.608 37.464 ;
     RECT  178.204 41.712 180.608 43.08 ;
     RECT  178.204 56.496 180.608 56.52 ;
     RECT  180.529 63.504 180.608 63.528 ;
     RECT  178.204 106.224 180.608 107.016 ;
     RECT  180.608 2.148 180.712 127.452 ;
     RECT  180.712 2.418 180.904 127.182 ;
     RECT  180.904 36.864 181.043 37.464 ;
     RECT  180.904 63.504 181.043 63.72 ;
     RECT  180.904 16.8 183.308 16.824 ;
     RECT  180.904 35.712 183.308 35.736 ;
     RECT  181.043 36.864 183.308 36.888 ;
     RECT  180.904 41.712 183.308 43.08 ;
     RECT  180.904 56.496 183.308 56.52 ;
     RECT  181.043 63.504 183.308 63.528 ;
     RECT  180.904 85.104 183.308 85.128 ;
     RECT  180.904 106.224 183.308 107.016 ;
     RECT  183.308 2.148 183.412 127.452 ;
     RECT  183.412 2.418 183.604 127.182 ;
     RECT  183.604 16.8 186.008 16.824 ;
     RECT  183.604 35.712 186.008 35.736 ;
     RECT  183.604 36.864 186.008 36.888 ;
     RECT  183.604 41.712 186.008 43.08 ;
     RECT  183.604 56.496 186.008 56.52 ;
     RECT  183.604 63.504 186.008 63.528 ;
     RECT  183.604 85.104 186.008 85.128 ;
     RECT  183.604 106.224 186.008 107.016 ;
     RECT  186.008 2.148 186.112 127.452 ;
     RECT  186.112 2.418 186.304 127.182 ;
     RECT  188.593 2.832 188.708 2.856 ;
     RECT  186.304 16.8 188.708 16.824 ;
     RECT  186.304 35.712 188.708 35.736 ;
     RECT  186.304 36.768 188.708 36.792 ;
     RECT  186.304 41.712 188.708 43.08 ;
     RECT  186.304 56.496 188.708 56.52 ;
     RECT  186.304 63.504 188.708 63.528 ;
     RECT  186.304 76.272 188.708 76.296 ;
     RECT  186.304 85.104 188.708 85.128 ;
     RECT  186.304 106.32 188.708 106.872 ;
     RECT  188.708 2.148 188.812 127.452 ;
     RECT  188.812 2.418 189.004 127.182 ;
     RECT  189.004 2.688 189.923 2.856 ;
     RECT  189.923 2.832 190.073 2.856 ;
     RECT  189.004 16.56 190.145 16.824 ;
     RECT  189.004 36.768 190.393 36.792 ;
     RECT  189.004 76.176 190.393 76.2 ;
     RECT  189.004 106.32 190.393 106.872 ;
     RECT  190.145 16.8 190.433 16.824 ;
     RECT  190.393 36.768 190.433 36.888 ;
     RECT  190.393 76.176 190.433 76.296 ;
     RECT  190.393 106.32 190.433 107.016 ;
     RECT  189.004 14.496 191.408 14.52 ;
     RECT  189.004 35.712 191.408 35.736 ;
     RECT  190.433 36.864 191.408 36.888 ;
     RECT  189.004 41.712 191.408 43.08 ;
     RECT  189.004 56.496 191.408 56.52 ;
     RECT  189.004 63.504 191.408 63.528 ;
     RECT  190.433 76.272 191.408 76.296 ;
     RECT  189.004 85.104 191.408 85.128 ;
     RECT  190.433 106.464 191.408 107.016 ;
     RECT  191.408 2.148 191.512 127.452 ;
     RECT  191.512 2.418 191.704 127.182 ;
     RECT  191.704 106.032 192.169 107.016 ;
     RECT  192.169 106.464 192.449 107.016 ;
     RECT  192.449 106.752 193.597 107.016 ;
     RECT  191.704 14.496 194.108 14.52 ;
     RECT  191.704 35.712 194.108 35.736 ;
     RECT  191.704 36.864 194.108 36.888 ;
     RECT  191.704 41.712 194.108 43.08 ;
     RECT  191.704 56.496 194.108 56.52 ;
     RECT  191.704 63.504 194.108 63.528 ;
     RECT  191.704 76.272 194.108 76.296 ;
     RECT  191.704 84.144 194.108 85.128 ;
     RECT  193.621 87.888 194.108 87.912 ;
     RECT  193.597 106.608 194.108 107.016 ;
     RECT  194.108 2.148 194.212 127.452 ;
     RECT  194.212 2.418 194.404 127.182 ;
     RECT  194.404 87.888 195.541 87.912 ;
     RECT  194.404 106.8 195.541 107.016 ;
     RECT  195.541 106.608 195.625 107.016 ;
     RECT  194.404 14.496 196.808 14.52 ;
     RECT  194.404 35.712 196.808 35.736 ;
     RECT  194.404 36.768 196.808 36.792 ;
     RECT  194.404 41.712 196.808 43.08 ;
     RECT  194.404 56.496 196.808 56.52 ;
     RECT  195.829 61.152 196.808 61.176 ;
     RECT  194.404 63.504 196.808 63.528 ;
     RECT  194.404 76.176 196.808 76.2 ;
     RECT  195.829 80.256 196.808 80.28 ;
     RECT  194.404 84.288 196.808 85.128 ;
     RECT  195.541 87.552 196.808 87.912 ;
     RECT  195.625 106.8 196.808 107.016 ;
     RECT  196.808 2.148 196.912 127.452 ;
     RECT  196.912 2.418 197.104 127.182 ;
     RECT  197.104 87.552 197.201 87.912 ;
     RECT  197.104 63.504 197.459 63.528 ;
     RECT  197.104 80.256 197.459 80.376 ;
     RECT  198.097 20.832 198.349 20.856 ;
     RECT  197.104 32.064 198.349 32.088 ;
     RECT  197.104 61.056 198.349 61.08 ;
     RECT  197.104 84.288 198.349 85.128 ;
     RECT  197.201 87.552 198.349 87.816 ;
     RECT  198.349 32.064 198.373 32.424 ;
     RECT  198.349 20.832 198.389 20.952 ;
     RECT  198.349 61.056 198.389 61.176 ;
     RECT  197.104 35.712 198.419 35.736 ;
     RECT  198.349 33.6 198.433 33.624 ;
     RECT  197.104 106.992 198.457 107.016 ;
     RECT  198.349 84.144 198.469 85.128 ;
     RECT  198.457 106.608 198.541 107.016 ;
     RECT  198.373 32.064 199.177 32.472 ;
     RECT  197.104 14.496 199.508 14.52 ;
     RECT  198.389 20.928 199.508 20.952 ;
     RECT  199.177 32.016 199.508 32.472 ;
     RECT  197.104 36.768 199.508 36.792 ;
     RECT  197.104 41.76 199.508 43.08 ;
     RECT  197.104 56.496 199.508 56.52 ;
     RECT  198.389 61.152 199.508 61.176 ;
     RECT  197.104 76.176 199.508 76.2 ;
     RECT  197.459 80.256 199.508 80.28 ;
     RECT  198.469 84.144 199.508 85.944 ;
     RECT  198.349 87.552 199.508 87.912 ;
     RECT  197.104 95.904 199.508 95.928 ;
     RECT  198.541 106.992 199.508 107.016 ;
     RECT  199.508 2.148 199.612 127.452 ;
     RECT  199.612 2.418 199.804 127.182 ;
     RECT  199.804 27.888 199.901 28.008 ;
     RECT  199.804 14.4 199.955 14.52 ;
     RECT  199.804 20.688 199.955 20.952 ;
     RECT  199.804 32.016 199.955 32.04 ;
     RECT  199.901 27.888 199.973 27.912 ;
     RECT  199.804 56.496 200.549 56.52 ;
     RECT  200.828 56.688 200.915 56.712 ;
     RECT  199.804 80.256 200.915 80.28 ;
     RECT  199.955 14.4 202.208 14.424 ;
     RECT  199.955 20.88 202.208 20.952 ;
     RECT  200.869 28.224 202.208 28.248 ;
     RECT  199.804 36.768 202.208 36.792 ;
     RECT  199.804 41.76 202.208 43.08 ;
     RECT  199.804 57.888 202.208 57.912 ;
     RECT  199.804 61.152 202.208 61.176 ;
     RECT  199.804 76.176 202.208 76.2 ;
     RECT  199.804 84.144 202.208 85.944 ;
     RECT  199.804 87.552 202.208 87.912 ;
     RECT  199.804 95.904 202.208 95.928 ;
     RECT  202.208 2.148 202.312 127.452 ;
     RECT  202.312 2.418 202.504 127.182 ;
     RECT  202.504 87.552 202.529 87.912 ;
     RECT  202.504 61.152 203.177 61.176 ;
     RECT  202.504 62.736 203.267 63.816 ;
     RECT  202.504 41.76 203.573 43.176 ;
     RECT  203.267 62.736 203.603 63.144 ;
     RECT  202.504 76.176 203.681 77.112 ;
     RECT  203.573 43.008 203.845 43.176 ;
     RECT  203.603 62.736 203.891 62.76 ;
     RECT  203.845 43.008 203.932 43.32 ;
     RECT  202.504 14.4 204.908 14.424 ;
     RECT  202.504 20.88 204.908 20.952 ;
     RECT  204.253 24.48 204.908 24.504 ;
     RECT  202.504 28.224 204.908 28.248 ;
     RECT  202.504 36.624 204.908 36.648 ;
     RECT  203.932 43.008 204.908 43.032 ;
     RECT  202.504 57.888 204.908 57.912 ;
     RECT  203.557 71.472 204.908 71.496 ;
     RECT  202.504 74.352 204.908 74.376 ;
     RECT  203.681 77.088 204.908 77.112 ;
     RECT  202.504 79.824 204.908 79.848 ;
     RECT  202.504 82.752 204.908 82.776 ;
     RECT  202.504 85.104 204.908 85.944 ;
     RECT  202.529 87.888 204.908 87.912 ;
     RECT  202.504 95.904 204.908 95.928 ;
     RECT  204.908 2.148 205.012 127.452 ;
     RECT  205.012 2.418 205.204 127.182 ;
     RECT  205.204 76.992 205.301 77.112 ;
     RECT  205.204 20.88 205.805 20.952 ;
     RECT  205.805 20.928 205.859 20.952 ;
     RECT  205.204 24.288 205.859 24.504 ;
     RECT  205.204 27.312 206.165 28.248 ;
     RECT  205.204 14.4 206.293 14.424 ;
     RECT  205.204 36.624 206.339 36.648 ;
     RECT  206.165 27.312 206.341 27.336 ;
     RECT  205.204 74.448 206.341 74.472 ;
     RECT  205.301 76.992 206.341 77.016 ;
     RECT  205.204 82.656 206.341 82.68 ;
     RECT  206.261 21.168 206.345 21.192 ;
     RECT  206.341 27.168 206.381 27.336 ;
     RECT  206.341 74.448 206.381 74.616 ;
     RECT  206.341 76.992 206.381 77.112 ;
     RECT  206.341 82.656 206.381 82.776 ;
     RECT  205.859 24.48 206.531 24.504 ;
     RECT  206.444 28.32 206.531 28.344 ;
     RECT  206.293 14.4 206.593 14.472 ;
     RECT  206.593 14.4 207.608 14.568 ;
     RECT  206.381 27.168 207.608 27.192 ;
     RECT  206.485 34.896 207.608 34.92 ;
     RECT  205.204 57.888 207.608 57.912 ;
     RECT  205.204 71.472 207.608 71.496 ;
     RECT  206.381 74.592 207.608 74.616 ;
     RECT  206.381 77.088 207.608 77.112 ;
     RECT  205.204 79.824 207.608 79.848 ;
     RECT  206.381 82.752 207.608 82.776 ;
     RECT  205.204 85.104 207.608 85.128 ;
     RECT  205.204 95.904 207.608 95.928 ;
     RECT  207.608 2.148 207.712 127.452 ;
     RECT  207.712 2.418 207.904 127.182 ;
     RECT  207.904 43.92 208.019 44.376 ;
     RECT  207.904 47.04 208.019 47.064 ;
     RECT  207.904 121.392 208.019 121.416 ;
     RECT  207.904 123.696 208.019 123.72 ;
     RECT  207.904 36.144 208.067 36.168 ;
     RECT  208.019 43.92 208.067 43.944 ;
     RECT  207.904 54.72 208.073 54.744 ;
     RECT  207.904 122.592 208.325 122.664 ;
     RECT  207.904 68.88 208.403 69 ;
     RECT  207.904 77.04 208.403 77.304 ;
     RECT  207.904 90.768 208.643 91.176 ;
     RECT  208.403 77.088 208.793 77.304 ;
     RECT  207.904 85.056 208.973 85.128 ;
     RECT  207.904 112.32 209.005 112.344 ;
     RECT  207.904 11.232 209.036 11.256 ;
     RECT  208.643 90.912 209.075 91.176 ;
     RECT  208.988 101.568 209.075 101.592 ;
     RECT  209.005 112.32 209.075 112.968 ;
     RECT  209.036 11.136 209.123 11.256 ;
     RECT  207.904 14.4 209.123 14.424 ;
     RECT  207.904 79.824 209.153 80.184 ;
     RECT  207.904 63.744 209.261 63.768 ;
     RECT  207.904 34.032 209.297 34.92 ;
     RECT  207.904 95.904 209.509 95.928 ;
     RECT  209.077 8.496 209.725 8.52 ;
     RECT  207.904 74.592 209.948 74.616 ;
     RECT  209.869 88.176 209.977 88.2 ;
     RECT  208.793 77.28 210.121 77.304 ;
     RECT  209.297 34.032 210.301 34.776 ;
     RECT  209.725 7.968 210.308 8.52 ;
     RECT  209.123 11.232 210.308 11.256 ;
     RECT  209.725 19.632 210.308 19.656 ;
     RECT  209.612 22.608 210.308 22.632 ;
     RECT  208.969 24.864 210.308 24.888 ;
     RECT  207.904 27.168 210.308 27.192 ;
     RECT  209.612 30.72 210.308 30.744 ;
     RECT  210.301 33.36 210.308 34.776 ;
     RECT  209.605 39.264 210.308 39.288 ;
     RECT  209.989 60.912 210.308 60.936 ;
     RECT  209.725 66.192 210.308 66.216 ;
     RECT  208.403 68.976 210.308 69 ;
     RECT  207.904 71.472 210.308 71.496 ;
     RECT  209.948 74.544 210.308 74.616 ;
     RECT  210.121 77.28 210.308 77.352 ;
     RECT  209.153 80.16 210.308 80.184 ;
     RECT  207.904 82.752 210.308 82.776 ;
     RECT  209.365 85.488 210.308 85.512 ;
     RECT  209.977 87.792 210.308 88.248 ;
     RECT  209.075 90.912 210.308 90.936 ;
     RECT  209.509 95.904 210.308 96.312 ;
     RECT  209.468 99.024 210.308 99.048 ;
     RECT  209.149 101.712 210.308 101.736 ;
     RECT  209.509 107.376 210.308 107.4 ;
     RECT  209.545 109.44 210.308 109.464 ;
     RECT  209.075 112.944 210.308 112.968 ;
     RECT  208.325 122.64 210.308 122.664 ;
     RECT  210.308 2.148 210.412 127.452 ;
     RECT  210.412 2.418 210.604 127.182 ;
     RECT  210.604 90.912 210.665 91.08 ;
     RECT  210.604 7.968 210.701 8.52 ;
     RECT  210.604 19.632 210.755 19.656 ;
     RECT  210.604 33.36 210.755 33.384 ;
     RECT  210.604 38.688 210.755 39.288 ;
     RECT  210.604 41.232 210.755 41.256 ;
     RECT  210.604 88.176 210.755 88.2 ;
     RECT  210.604 96.096 210.755 96.12 ;
     RECT  210.604 17.04 210.773 17.16 ;
     RECT  210.604 51.888 210.773 51.912 ;
     RECT  210.604 27.216 210.781 27.24 ;
     RECT  210.604 103.728 210.781 104.184 ;
     RECT  210.604 6.096 210.803 6.216 ;
     RECT  210.701 7.968 210.803 8.472 ;
     RECT  210.773 17.04 210.803 17.064 ;
     RECT  210.604 82.752 210.899 82.824 ;
     RECT  210.604 93.504 210.899 93.528 ;
     RECT  210.604 74.592 210.953 74.616 ;
     RECT  210.604 112.944 210.953 112.968 ;
     RECT  210.803 6.096 211.061 6.12 ;
     RECT  210.604 71.472 211.133 71.784 ;
     RECT  210.604 122.64 211.187 122.664 ;
     RECT  210.604 101.712 211.385 101.976 ;
     RECT  210.604 85.44 211.421 85.512 ;
     RECT  210.781 104.16 211.427 104.184 ;
     RECT  210.604 97.776 211.465 98.04 ;
     RECT  211.597 118.56 211.763 118.584 ;
     RECT  210.899 82.752 211.817 82.776 ;
     RECT  210.755 39.264 212.389 39.288 ;
     RECT  211.669 27.792 213.008 27.816 ;
     RECT  212.389 38.784 213.008 39.288 ;
     RECT  212.389 49.584 213.008 49.608 ;
     RECT  210.604 68.928 213.008 68.952 ;
     RECT  211.133 71.472 213.008 71.496 ;
     RECT  210.604 77.328 213.008 77.352 ;
     RECT  211.421 85.44 213.008 85.464 ;
     RECT  210.665 91.056 213.008 91.08 ;
     RECT  211.465 97.776 213.008 97.8 ;
     RECT  211.385 101.952 213.008 101.976 ;
     RECT  212.108 104.688 213.008 104.712 ;
     RECT  211.676 115.488 213.008 115.512 ;
     RECT  213.008 2.148 213.112 127.452 ;
     RECT  213.112 2.418 213.304 127.182 ;
     RECT  214.333 5.712 215.82 5.736 ;
     RECT  214.333 8.448 215.82 8.472 ;
     RECT  214.333 11.184 215.82 11.208 ;
     RECT  214.873 13.968 215.82 13.992 ;
     RECT  214.333 16.704 215.82 16.728 ;
     RECT  214.333 19.44 215.82 19.464 ;
     RECT  214.333 22.224 215.82 22.248 ;
     RECT  214.297 24.96 215.82 24.984 ;
     RECT  214.333 27.696 215.82 27.72 ;
     RECT  214.333 30.432 215.82 30.456 ;
     RECT  213.304 33.216 215.82 33.24 ;
     RECT  213.304 35.952 215.82 35.976 ;
     RECT  214.333 38.688 215.82 38.712 ;
     RECT  213.304 41.424 215.82 41.448 ;
     RECT  213.304 44.208 215.82 44.232 ;
     RECT  214.297 46.944 215.82 46.968 ;
     RECT  214.333 49.68 215.82 49.704 ;
     RECT  213.304 52.464 215.82 52.488 ;
     RECT  214.297 55.2 215.82 55.224 ;
     RECT  214.333 57.936 215.82 57.96 ;
     RECT  214.333 60.672 215.82 60.696 ;
     RECT  213.304 63.456 215.82 63.48 ;
     RECT  213.304 66.192 215.82 66.216 ;
     RECT  213.304 68.928 215.82 68.952 ;
     RECT  214.333 71.664 215.82 71.688 ;
     RECT  214.333 74.448 215.82 74.472 ;
     RECT  214.297 77.184 215.82 77.208 ;
     RECT  213.304 79.92 215.82 79.944 ;
     RECT  214.333 82.704 215.82 82.728 ;
     RECT  214.333 85.44 215.82 85.464 ;
     RECT  214.333 88.176 215.82 88.2 ;
     RECT  213.304 90.912 215.82 90.936 ;
     RECT  213.304 93.696 215.82 93.72 ;
     RECT  213.304 96.432 215.82 96.456 ;
     RECT  214.333 99.168 215.82 99.192 ;
     RECT  214.333 101.904 215.82 101.928 ;
     RECT  214.873 104.688 215.82 104.712 ;
     RECT  214.333 107.424 215.82 107.448 ;
     RECT  213.304 110.16 215.82 110.184 ;
     RECT  213.304 112.944 215.82 112.968 ;
     RECT  213.304 115.68 215.82 115.704 ;
     RECT  214.333 118.416 215.82 118.44 ;
     RECT  214.333 121.152 215.82 121.176 ;
     RECT  213.304 123.936 215.82 123.96 ;
    LAYER M5 ;
     RECT  149.472 0.144 149.496 0.227 ;
     RECT  66.528 0.144 66.552 1.763 ;
     RECT  58.464 0.133 58.488 2.137 ;
     RECT  2.4 2.137 2.52 2.151 ;
     RECT  5.1 2.137 5.22 2.151 ;
     RECT  7.8 2.137 7.92 2.151 ;
     RECT  10.5 2.137 10.62 2.151 ;
     RECT  13.2 2.137 13.32 2.151 ;
     RECT  15.9 2.137 16.02 2.151 ;
     RECT  18.6 2.137 18.72 2.151 ;
     RECT  21.3 2.137 21.42 2.151 ;
     RECT  24 2.137 24.12 2.151 ;
     RECT  26.7 2.137 26.82 2.151 ;
     RECT  29.4 2.137 29.52 2.151 ;
     RECT  32.1 2.137 32.22 2.151 ;
     RECT  34.8 2.137 34.92 2.151 ;
     RECT  37.5 2.137 37.62 2.151 ;
     RECT  40.2 2.137 40.32 2.151 ;
     RECT  42.9 2.137 43.02 2.151 ;
     RECT  45.6 2.137 45.72 2.151 ;
     RECT  48.3 2.137 48.42 2.151 ;
     RECT  51 2.137 51.12 2.151 ;
     RECT  53.7 2.137 53.82 2.151 ;
     RECT  56.4 2.137 56.52 2.151 ;
     RECT  58.464 2.137 59.22 2.151 ;
     RECT  61.8 2.137 61.92 2.151 ;
     RECT  64.5 2.137 64.62 2.151 ;
     RECT  67.2 2.137 67.32 2.151 ;
     RECT  69.9 2.137 70.02 2.151 ;
     RECT  72.6 2.137 72.72 2.151 ;
     RECT  75.3 2.137 75.42 2.151 ;
     RECT  78 2.137 78.12 2.151 ;
     RECT  80.7 2.137 80.82 2.151 ;
     RECT  83.4 2.137 83.52 2.151 ;
     RECT  86.1 2.137 86.22 2.151 ;
     RECT  88.8 2.137 88.92 2.151 ;
     RECT  91.5 2.137 91.62 2.151 ;
     RECT  94.2 2.137 94.32 2.151 ;
     RECT  96.9 2.137 97.02 2.151 ;
     RECT  99.6 2.137 99.72 2.151 ;
     RECT  102.3 2.137 102.42 2.151 ;
     RECT  105 2.137 105.12 2.151 ;
     RECT  107.7 2.137 107.82 2.151 ;
     RECT  110.4 2.137 110.52 2.151 ;
     RECT  113.1 2.137 113.22 2.151 ;
     RECT  115.8 2.137 115.92 2.151 ;
     RECT  118.5 2.137 118.62 2.151 ;
     RECT  121.2 2.137 121.32 2.151 ;
     RECT  123.9 2.137 124.02 2.151 ;
     RECT  126.6 2.137 126.72 2.151 ;
     RECT  129.3 2.137 129.42 2.151 ;
     RECT  132 2.137 132.12 2.151 ;
     RECT  134.7 2.137 134.82 2.151 ;
     RECT  137.4 2.137 137.52 2.151 ;
     RECT  140.1 2.137 140.22 2.151 ;
     RECT  142.8 2.137 142.92 2.151 ;
     RECT  145.5 2.137 145.62 2.151 ;
     RECT  148.2 2.137 148.32 2.151 ;
     RECT  150.9 2.137 151.02 2.151 ;
     RECT  153.6 2.137 153.72 2.151 ;
     RECT  156.3 2.137 156.42 2.151 ;
     RECT  159 2.137 159.12 2.151 ;
     RECT  161.7 2.137 161.82 2.151 ;
     RECT  164.4 2.137 164.52 2.151 ;
     RECT  167.1 2.137 167.22 2.151 ;
     RECT  169.8 2.137 169.92 2.151 ;
     RECT  172.5 2.137 172.62 2.151 ;
     RECT  175.2 2.137 175.32 2.151 ;
     RECT  177.9 2.137 178.02 2.151 ;
     RECT  180.6 2.137 180.72 2.151 ;
     RECT  183.3 2.137 183.42 2.151 ;
     RECT  186 2.137 186.12 2.151 ;
     RECT  188.7 2.137 188.82 2.151 ;
     RECT  191.4 2.137 191.52 2.151 ;
     RECT  194.1 2.137 194.22 2.151 ;
     RECT  196.8 2.137 196.92 2.151 ;
     RECT  199.5 2.137 199.62 2.151 ;
     RECT  202.2 2.137 202.32 2.151 ;
     RECT  204.9 2.137 205.02 2.151 ;
     RECT  207.6 2.137 207.72 2.151 ;
     RECT  210.3 2.137 210.42 2.151 ;
     RECT  213 2.137 213.12 2.151 ;
     RECT  188.7 2.151 189.012 2.677 ;
     RECT  26.7 2.151 27.012 3.397 ;
     RECT  29.4 2.151 29.712 3.397 ;
     RECT  150.9 2.151 151.212 3.685 ;
     RECT  210.3 2.151 210.612 6.085 ;
     RECT  210.3 6.085 210.744 6.181 ;
     RECT  2.4 2.151 2.712 6.229 ;
     RECT  5.1 2.151 5.412 8.437 ;
     RECT  209.088 8.485 209.112 11.221 ;
     RECT  210.3 6.181 210.792 11.221 ;
     RECT  6.624 11.365 6.648 11.749 ;
     RECT  7.8 2.151 8.112 11.749 ;
     RECT  6.624 11.749 8.112 13.381 ;
     RECT  6.624 13.381 8.232 14.197 ;
     RECT  199.5 2.151 199.812 14.389 ;
     RECT  209.088 11.221 210.792 14.435 ;
     RECT  5.1 8.437 5.544 16.501 ;
     RECT  6.624 14.197 8.52 16.501 ;
     RECT  188.7 2.677 189.912 16.595 ;
     RECT  113.1 2.151 113.412 16.789 ;
     RECT  209.664 14.435 210.792 17.075 ;
     RECT  113.1 16.789 113.976 18.275 ;
     RECT  5.1 16.501 8.52 19.091 ;
     RECT  204.9 2.151 205.212 20.917 ;
     RECT  206.304 14.437 206.328 20.917 ;
     RECT  204.9 20.917 206.328 24.469 ;
     RECT  7.056 19.091 8.52 24.613 ;
     RECT  5.1 19.091 6.072 26.053 ;
     RECT  2.4 6.229 3.528 26.099 ;
     RECT  4.656 26.053 6.072 26.819 ;
     RECT  204.9 24.469 206.52 27.347 ;
     RECT  213 2.151 213.312 27.781 ;
     RECT  86.1 2.151 86.412 28.165 ;
     RECT  199.5 14.389 199.944 28.213 ;
     RECT  10.5 2.151 10.812 29.605 ;
     RECT  4.704 26.819 6.072 29.893 ;
     RECT  7.056 24.613 9.192 29.893 ;
     RECT  4.704 29.893 9.192 30.035 ;
     RECT  13.2 2.151 13.512 30.133 ;
     RECT  15.9 2.151 16.212 30.469 ;
     RECT  10.5 29.605 11.256 30.613 ;
     RECT  15.9 30.469 17.16 30.661 ;
     RECT  0.192 30.757 0.216 30.899 ;
     RECT  12.48 30.133 13.512 30.949 ;
     RECT  4.704 30.035 6.072 31.715 ;
     RECT  18.6 2.151 18.912 31.765 ;
     RECT  25.92 3.397 27.012 31.765 ;
     RECT  15.408 30.661 17.16 31.811 ;
     RECT  25.92 31.765 27.144 31.909 ;
     RECT  25.68 31.909 27.144 31.955 ;
     RECT  29.28 3.397 29.712 32.101 ;
     RECT  24 2.151 24.312 32.437 ;
     RECT  12.48 30.949 14.184 32.627 ;
     RECT  2.4 26.099 2.712 32.869 ;
     RECT  4.704 31.715 5.976 32.915 ;
     RECT  5.1 32.915 5.976 32.917 ;
     RECT  7.104 30.035 9.192 32.917 ;
     RECT  10.368 30.613 11.256 32.965 ;
     RECT  18.288 31.765 18.912 33.013 ;
     RECT  21.3 2.151 21.612 33.013 ;
     RECT  10.32 32.965 11.256 33.107 ;
     RECT  28.368 32.101 29.712 33.301 ;
     RECT  12.48 32.627 13.656 33.589 ;
     RECT  21.12 33.013 21.612 33.589 ;
     RECT  22.896 31.765 22.92 33.589 ;
     RECT  5.1 32.917 9.192 33.925 ;
     RECT  10.32 33.107 10.812 33.925 ;
     RECT  15.792 31.811 17.16 34.021 ;
     RECT  207.6 2.151 207.912 34.021 ;
     RECT  14.976 34.021 17.16 34.069 ;
     RECT  18.288 33.013 19.416 34.069 ;
     RECT  32.1 2.151 32.412 34.117 ;
     RECT  14.976 34.069 19.416 34.259 ;
     RECT  5.1 33.925 10.812 34.453 ;
     RECT  31.248 34.117 32.412 34.741 ;
     RECT  209.664 17.075 210.744 34.741 ;
     RECT  206.304 27.347 206.52 34.931 ;
     RECT  20.112 34.741 20.136 35.365 ;
     RECT  21.12 33.589 22.92 35.365 ;
     RECT  67.2 2.151 67.512 35.701 ;
     RECT  198.384 32.437 198.408 35.747 ;
     RECT  14.976 34.259 18.912 35.749 ;
     RECT  20.112 35.365 22.92 35.749 ;
     RECT  31.248 34.741 32.52 35.939 ;
     RECT  37.5 2.151 37.812 36.277 ;
     RECT  28.32 33.301 29.712 36.325 ;
     RECT  26.7 31.955 27.144 36.373 ;
     RECT  28.32 36.325 29.832 36.373 ;
     RECT  33.744 34.645 33.768 36.373 ;
     RECT  34.8 2.151 35.112 36.373 ;
     RECT  14.976 35.749 22.92 36.515 ;
     RECT  36.144 36.421 36.168 36.517 ;
     RECT  37.5 36.277 37.944 36.517 ;
     RECT  206.304 34.931 206.328 36.659 ;
     RECT  14.976 36.515 20.088 36.755 ;
     RECT  31.248 35.939 32.412 36.901 ;
     RECT  12.432 33.589 13.656 36.949 ;
     RECT  30.864 36.901 32.412 36.997 ;
     RECT  33.744 36.373 35.112 36.997 ;
     RECT  58.464 2.151 59.412 37.091 ;
     RECT  26.7 36.373 29.832 37.333 ;
     RECT  30.864 36.997 35.112 37.333 ;
     RECT  12 36.949 13.656 37.381 ;
     RECT  14.976 36.755 16.728 37.381 ;
     RECT  25.68 31.955 25.704 37.427 ;
     RECT  180.6 2.151 180.912 37.429 ;
     RECT  88.8 2.151 89.112 37.525 ;
     RECT  67.2 35.701 67.8 37.571 ;
     RECT  79.68 2.869 79.704 37.571 ;
     RECT  59.1 37.091 59.412 37.573 ;
     RECT  61.8 2.151 62.112 37.573 ;
     RECT  107.7 2.151 108.012 37.573 ;
     RECT  159 2.151 159.312 37.573 ;
     RECT  21.168 36.515 22.92 37.619 ;
     RECT  12 37.381 16.728 37.715 ;
     RECT  12 37.715 14.568 37.907 ;
     RECT  24 32.437 24.552 38.149 ;
     RECT  23.904 38.149 25.464 38.243 ;
     RECT  15.552 37.715 16.728 38.435 ;
     RECT  23.904 38.243 24.408 38.435 ;
     RECT  18.096 36.755 20.088 38.725 ;
     RECT  21.168 37.619 22.536 38.725 ;
     RECT  26.7 37.333 35.112 38.725 ;
     RECT  36.144 36.517 37.944 38.725 ;
     RECT  18.096 38.725 22.536 38.819 ;
     RECT  209.616 34.741 210.744 39.299 ;
     RECT  26.7 38.725 37.944 39.395 ;
     RECT  31.248 39.395 37.944 39.443 ;
     RECT  31.968 39.443 37.944 39.635 ;
     RECT  15.552 38.435 16.344 39.779 ;
     RECT  5.1 34.453 10.968 39.827 ;
     RECT  20.064 38.819 22.536 39.827 ;
     RECT  18.096 38.819 18.912 40.021 ;
     RECT  67.2 37.571 67.608 40.067 ;
     RECT  23.904 38.435 24.312 40.165 ;
     RECT  25.44 38.243 25.464 40.165 ;
     RECT  12 37.907 12.024 40.405 ;
     RECT  13.104 37.907 14.568 40.405 ;
     RECT  31.968 39.635 35.352 40.405 ;
     RECT  5.1 39.827 8.712 40.595 ;
     RECT  26.7 39.395 30.216 40.595 ;
     RECT  17.76 40.021 18.912 40.835 ;
     RECT  121.2 2.151 121.512 40.933 ;
     RECT  94.2 2.151 94.512 41.221 ;
     RECT  118.5 2.151 118.812 41.221 ;
     RECT  20.064 39.827 22.392 41.363 ;
     RECT  115.8 2.151 116.112 41.461 ;
     RECT  96.9 2.151 97.212 41.605 ;
     RECT  102.3 2.151 102.612 41.701 ;
     RECT  12 40.405 14.568 41.747 ;
     RECT  120.912 40.933 121.512 41.749 ;
     RECT  122.736 41.557 122.76 41.749 ;
     RECT  158.304 37.573 159.312 41.845 ;
     RECT  167.1 2.151 167.412 41.845 ;
     RECT  157.92 41.845 159.312 41.891 ;
     RECT  105 2.151 105.312 41.941 ;
     RECT  115.8 41.461 116.808 41.941 ;
     RECT  157.92 41.891 157.944 41.987 ;
     RECT  202.2 2.151 202.512 42.037 ;
     RECT  196.8 2.151 197.112 42.085 ;
     RECT  6.912 40.595 8.712 42.133 ;
     RECT  9.936 39.827 10.968 42.133 ;
     RECT  61.8 37.573 62.664 42.133 ;
     RECT  115.8 41.941 116.952 42.133 ;
     RECT  202.2 42.037 203.208 42.133 ;
     RECT  23.904 40.165 25.464 42.179 ;
     RECT  23.904 42.179 24.792 42.227 ;
     RECT  31.344 40.405 35.352 42.275 ;
     RECT  172.5 2.151 172.812 42.421 ;
     RECT  61.8 42.133 62.76 42.467 ;
     RECT  150 3.685 151.212 42.467 ;
     RECT  80.7 2.151 81.012 42.469 ;
     RECT  107.7 37.573 108.12 42.469 ;
     RECT  120.912 41.749 122.76 42.517 ;
     RECT  123.9 2.151 124.212 42.517 ;
     RECT  59.1 37.573 60.072 42.563 ;
     RECT  107.7 42.469 108.168 42.565 ;
     RECT  31.584 42.275 35.352 42.613 ;
     RECT  36.432 39.635 37.944 42.613 ;
     RECT  202.2 42.133 203.256 42.613 ;
     RECT  61.8 42.467 62.712 42.659 ;
     RECT  101.376 41.701 102.612 42.709 ;
     RECT  86.1 28.165 86.952 42.755 ;
     RECT  80.7 42.469 81.288 42.757 ;
     RECT  94.2 41.221 94.728 42.853 ;
     RECT  114.864 42.133 116.952 42.853 ;
     RECT  107.7 42.565 108.792 42.901 ;
     RECT  12 41.747 14.328 42.995 ;
     RECT  20.4 41.363 22.392 43.043 ;
     RECT  5.1 40.595 5.784 43.093 ;
     RECT  24 42.227 24.792 43.285 ;
     RECT  96.336 41.605 97.212 43.285 ;
     RECT  101.376 42.709 102.936 43.285 ;
     RECT  107.136 42.901 108.792 43.285 ;
     RECT  110.4 2.151 110.712 43.285 ;
     RECT  202.2 42.613 203.304 43.285 ;
     RECT  31.584 42.613 37.944 43.331 ;
     RECT  18.432 40.835 18.912 43.379 ;
     RECT  29.088 40.595 30.216 43.427 ;
     RECT  172.5 42.421 173.208 43.571 ;
     RECT  114.624 42.853 116.952 43.811 ;
     RECT  101.28 43.285 103.848 43.813 ;
     RECT  113.1 18.275 113.412 43.861 ;
     RECT  86.1 42.755 86.856 43.907 ;
     RECT  98.448 42.469 98.472 43.909 ;
     RECT  99.6 2.151 99.912 43.909 ;
     RECT  6.912 42.133 10.968 43.955 ;
     RECT  23.712 43.285 24.792 43.955 ;
     RECT  98.448 43.909 99.912 43.955 ;
     RECT  118.5 41.221 119.208 43.955 ;
     RECT  207.6 34.021 208.056 43.955 ;
     RECT  96.192 43.285 97.212 44.147 ;
     RECT  26.7 40.595 28.104 44.149 ;
     RECT  29.088 43.427 30.168 44.149 ;
     RECT  31.584 43.331 36.504 44.387 ;
     RECT  105 41.941 105.96 44.437 ;
     RECT  107.136 43.285 110.712 44.437 ;
     RECT  20.4 43.043 22.344 44.483 ;
     RECT  101.04 43.813 103.848 44.483 ;
     RECT  31.584 44.387 35.352 44.533 ;
     RECT  101.04 44.483 102.936 44.581 ;
     RECT  12.192 42.995 14.328 44.627 ;
     RECT  36.432 44.387 36.504 44.627 ;
     RECT  105 44.437 110.712 44.627 ;
     RECT  9.888 43.955 10.968 44.629 ;
     RECT  37.5 43.331 37.944 44.677 ;
     RECT  105 44.627 108.792 44.771 ;
     RECT  37.5 44.677 37.992 44.915 ;
     RECT  96.288 44.147 97.212 44.917 ;
     RECT  98.64 43.955 99.912 44.917 ;
     RECT  36.48 44.627 36.504 45.011 ;
     RECT  26.7 44.149 30.168 45.059 ;
     RECT  80.7 42.757 81.384 45.059 ;
     RECT  88.224 37.525 89.112 45.299 ;
     RECT  114.864 43.811 116.952 45.299 ;
     RECT  6.912 43.955 8.712 45.445 ;
     RECT  9.888 44.629 11.112 45.445 ;
     RECT  118.5 43.955 118.812 45.541 ;
     RECT  28.32 45.059 30.168 45.587 ;
     RECT  21.3 44.483 22.344 45.635 ;
     RECT  28.32 45.587 29.712 45.635 ;
     RECT  94.2 42.853 94.968 45.635 ;
     RECT  96.288 44.917 99.912 45.635 ;
     RECT  31.536 44.533 35.352 45.731 ;
     RECT  107.568 44.771 108.792 45.877 ;
     RECT  110.4 44.627 110.712 45.877 ;
     RECT  114.864 45.299 116.808 45.923 ;
     RECT  100.896 44.581 102.936 46.019 ;
     RECT  37.5 44.915 37.812 46.117 ;
     RECT  42.9 2.151 43.212 46.165 ;
     RECT  23.712 43.955 24.552 46.211 ;
     RECT  29.184 45.635 29.712 46.211 ;
     RECT  111.696 44.725 111.72 46.211 ;
     RECT  120.912 42.517 124.212 46.211 ;
     RECT  42.768 46.165 43.212 46.355 ;
     RECT  114.864 45.923 116.328 46.451 ;
     RECT  112.896 43.861 113.412 46.595 ;
     RECT  33.888 45.731 35.352 46.693 ;
     RECT  36.72 46.117 37.812 46.693 ;
     RECT  2.4 32.869 3.384 46.741 ;
     RECT  31.536 45.731 32.412 46.787 ;
     RECT  105 44.771 106.584 46.787 ;
     RECT  33.888 46.693 37.812 46.883 ;
     RECT  33.888 46.883 35.112 47.027 ;
     RECT  96.9 45.635 99.912 47.027 ;
     RECT  36.192 46.883 37.812 47.315 ;
     RECT  96.9 47.027 98.04 47.363 ;
     RECT  107.568 45.877 110.712 47.363 ;
     RECT  121.2 46.211 124.212 47.363 ;
     RECT  12.24 44.627 14.328 47.557 ;
     RECT  36.192 47.315 36.216 47.939 ;
     RECT  118.5 45.541 119.736 47.987 ;
     RECT  112.992 46.595 113.412 48.275 ;
     RECT  6.912 45.445 11.112 48.371 ;
     RECT  107.568 47.363 108.792 48.371 ;
     RECT  4.944 43.093 5.784 48.373 ;
     RECT  103.968 45.541 103.992 48.419 ;
     RECT  105 46.787 106.248 48.419 ;
     RECT  212.4 27.781 213.312 49.619 ;
     RECT  4.944 48.373 6.312 51.109 ;
     RECT  210.3 39.299 210.744 51.923 ;
     RECT  7.68 48.371 11.112 53.603 ;
     RECT  9.888 53.603 11.112 54.131 ;
     RECT  207.6 43.955 208.008 54.755 ;
     RECT  2.4 46.741 3.624 55.907 ;
     RECT  9.888 54.131 11.016 55.957 ;
     RECT  7.68 53.603 8.376 56.483 ;
     RECT  9.84 55.957 11.016 56.531 ;
     RECT  12.24 47.557 14.52 56.531 ;
     RECT  167.1 41.845 167.832 56.531 ;
     RECT  9.84 56.531 10.812 57.059 ;
     RECT  7.68 56.483 8.112 57.347 ;
     RECT  12.24 56.531 13.656 57.589 ;
     RECT  105 48.419 105.96 57.635 ;
     RECT  199.5 28.213 200.904 57.923 ;
     RECT  4.944 51.109 6.36 58.163 ;
     RECT  12.144 57.589 13.656 58.163 ;
     RECT  15.552 39.779 16.212 58.211 ;
     RECT  12.144 58.163 13.608 58.739 ;
     RECT  107.7 48.371 108.792 59.315 ;
     RECT  7.8 57.347 8.112 59.749 ;
     RECT  101.376 46.019 102.936 60.467 ;
     RECT  210.3 51.923 210.612 60.901 ;
     RECT  195.84 42.085 197.112 61.187 ;
     RECT  202.2 43.285 203.88 62.771 ;
     RECT  196.8 61.187 197.112 63.493 ;
     RECT  7.8 59.749 8.664 63.589 ;
     RECT  207.6 54.755 207.912 63.733 ;
     RECT  121.2 47.363 122.472 66.179 ;
     RECT  114.864 46.451 116.112 66.515 ;
     RECT  10.272 57.059 10.812 66.755 ;
     RECT  4.944 58.163 5.412 66.757 ;
     RECT  6.48 60.949 6.504 66.757 ;
     RECT  10.32 66.755 10.812 68.675 ;
     RECT  10.5 68.675 10.812 71.221 ;
     RECT  202.2 62.771 203.592 71.507 ;
     RECT  210 60.901 210.612 71.749 ;
     RECT  10.368 71.221 10.812 74.053 ;
     RECT  102.3 60.467 102.936 75.299 ;
     RECT  186 2.151 186.312 76.261 ;
     RECT  2.4 55.907 2.712 76.885 ;
     RECT  207.6 63.733 208.392 77.075 ;
     RECT  202.2 71.507 203.496 77.123 ;
     RECT  12.96 58.739 13.608 77.939 ;
     RECT  4.944 66.757 6.504 78.613 ;
     RECT  7.68 63.589 8.664 78.613 ;
     RECT  4.944 78.613 8.664 78.659 ;
     RECT  103.776 79.573 103.8 79.765 ;
     RECT  202.2 77.123 203.4 79.859 ;
     RECT  207.6 77.075 208.248 80.149 ;
     RECT  200.88 57.923 200.904 80.291 ;
     RECT  103.776 79.765 103.944 81.445 ;
     RECT  105 57.635 105.312 81.445 ;
     RECT  12.96 77.939 13.512 81.635 ;
     RECT  202.2 79.859 203.256 82.787 ;
     RECT  102.3 75.299 102.744 83.365 ;
     RECT  191.4 2.151 191.712 84.133 ;
     RECT  180.6 37.429 181.032 85.139 ;
     RECT  4.944 78.659 5.544 86.581 ;
     RECT  6.816 78.659 8.664 86.581 ;
     RECT  210 71.749 210.888 87.827 ;
     RECT  2.4 76.885 3.672 87.829 ;
     RECT  2.4 87.829 3.864 87.875 ;
     RECT  194.1 2.151 194.412 87.877 ;
     RECT  4.944 86.581 8.664 91.091 ;
     RECT  207.6 80.149 208.632 91.141 ;
     RECT  207.6 91.141 209.064 91.187 ;
     RECT  4.944 91.091 8.472 91.523 ;
     RECT  3.84 87.875 3.864 93.109 ;
     RECT  4.944 91.523 6.6 93.109 ;
     RECT  210.192 87.827 210.888 93.539 ;
     RECT  3.84 93.109 6.6 94.405 ;
     RECT  7.68 91.523 8.472 94.405 ;
     RECT  3.84 94.405 8.472 95.171 ;
     RECT  3.936 95.171 8.472 95.219 ;
     RECT  196.8 63.493 197.448 95.939 ;
     RECT  2.4 87.875 2.712 96.277 ;
     RECT  3.936 95.219 5.544 96.277 ;
     RECT  209.04 91.187 209.064 96.277 ;
     RECT  210.192 93.539 210.792 96.277 ;
     RECT  2.4 96.277 5.544 96.323 ;
     RECT  213 49.619 213.312 97.765 ;
     RECT  209.04 96.277 210.792 98.005 ;
     RECT  212.16 97.765 213.312 98.005 ;
     RECT  4.416 96.323 5.544 98.675 ;
     RECT  6.576 95.219 8.472 101.269 ;
     RECT  6.48 101.269 8.472 103.379 ;
     RECT  6.48 103.379 8.376 103.763 ;
     RECT  209.04 98.005 213.312 104.195 ;
     RECT  191.4 84.133 192.12 106.067 ;
     RECT  103.776 81.445 105.312 106.259 ;
     RECT  10.32 74.053 10.812 106.307 ;
     RECT  24 46.211 24.312 106.405 ;
     RECT  23.904 106.405 24.312 106.547 ;
     RECT  103.92 106.259 105.312 106.643 ;
     RECT  186 76.261 187.224 106.643 ;
     RECT  193.632 87.877 194.412 106.643 ;
     RECT  195.552 87.541 195.576 106.643 ;
     RECT  198.48 85.909 198.504 106.643 ;
     RECT  102.144 83.365 102.744 106.739 ;
     RECT  102.144 106.739 102.612 106.835 ;
     RECT  104.112 106.643 105.312 106.883 ;
     RECT  10.368 106.307 10.812 107.027 ;
     RECT  209.04 104.195 211.176 109.475 ;
     RECT  6.48 103.763 6.504 111.203 ;
     RECT  209.04 109.475 209.064 112.355 ;
     RECT  7.8 103.763 8.376 114.035 ;
     RECT  210.3 109.475 211.176 115.477 ;
     RECT  212.16 104.195 213.312 115.477 ;
     RECT  210.3 115.477 213.312 115.523 ;
     RECT  2.4 96.323 3.336 116.339 ;
     RECT  210.3 115.523 211.752 118.595 ;
     RECT  207.6 91.187 207.912 121.381 ;
     RECT  7.8 114.035 8.112 121.957 ;
     RECT  4.416 98.675 5.412 122.675 ;
     RECT  210.3 118.595 211.176 122.675 ;
     RECT  207.6 121.381 208.008 123.731 ;
     RECT  7.44 121.957 8.112 123.779 ;
     RECT  2.4 116.339 2.712 127.449 ;
     RECT  5.1 122.675 5.412 127.449 ;
     RECT  7.8 123.779 8.112 127.449 ;
     RECT  10.5 107.027 10.812 127.449 ;
     RECT  13.2 81.635 13.512 127.449 ;
     RECT  15.9 58.211 16.212 127.449 ;
     RECT  18.6 43.379 18.912 127.449 ;
     RECT  21.3 45.635 21.612 127.449 ;
     RECT  24 106.547 24.312 127.449 ;
     RECT  26.7 45.059 27.012 127.449 ;
     RECT  29.4 46.211 29.712 127.449 ;
     RECT  32.1 46.787 32.412 127.449 ;
     RECT  34.8 47.027 35.112 127.449 ;
     RECT  37.5 47.315 37.812 127.449 ;
     RECT  40.2 2.151 40.512 127.449 ;
     RECT  42.9 46.355 43.212 127.449 ;
     RECT  45.6 2.151 45.912 127.449 ;
     RECT  48.3 2.151 48.612 127.449 ;
     RECT  51 2.151 51.312 127.449 ;
     RECT  53.7 2.151 54.012 127.449 ;
     RECT  56.4 2.151 56.712 127.449 ;
     RECT  59.1 42.563 59.412 127.449 ;
     RECT  61.8 42.659 62.112 127.449 ;
     RECT  64.5 2.151 64.812 127.449 ;
     RECT  67.2 40.067 67.512 127.449 ;
     RECT  69.9 2.151 70.212 127.449 ;
     RECT  72.6 2.151 72.912 127.449 ;
     RECT  75.3 2.151 75.612 127.449 ;
     RECT  78 2.151 78.312 127.449 ;
     RECT  80.7 45.059 81.012 127.449 ;
     RECT  83.4 2.151 83.712 127.449 ;
     RECT  86.1 43.907 86.412 127.449 ;
     RECT  88.8 45.299 89.112 127.449 ;
     RECT  91.5 2.151 91.812 127.449 ;
     RECT  94.2 45.635 94.512 127.449 ;
     RECT  96.9 47.363 97.212 127.449 ;
     RECT  99.6 47.027 99.912 127.449 ;
     RECT  102.3 106.835 102.612 127.449 ;
     RECT  105 106.883 105.312 127.449 ;
     RECT  107.7 59.315 108.012 127.449 ;
     RECT  110.4 47.363 110.712 127.449 ;
     RECT  113.1 48.275 113.412 127.449 ;
     RECT  115.8 66.515 116.112 127.449 ;
     RECT  118.5 47.987 118.812 127.449 ;
     RECT  121.2 66.179 121.512 127.449 ;
     RECT  123.9 47.363 124.212 127.449 ;
     RECT  126.6 2.151 126.912 127.449 ;
     RECT  129.3 2.151 129.612 127.449 ;
     RECT  132 2.151 132.312 127.449 ;
     RECT  134.7 2.151 135.012 127.449 ;
     RECT  137.4 2.151 137.712 127.449 ;
     RECT  140.1 2.151 140.412 127.449 ;
     RECT  142.8 2.151 143.112 127.449 ;
     RECT  145.5 2.151 145.812 127.449 ;
     RECT  148.2 2.151 148.512 127.449 ;
     RECT  150.9 42.467 151.212 127.449 ;
     RECT  153.6 2.151 153.912 127.449 ;
     RECT  156.3 2.151 156.612 127.449 ;
     RECT  159 41.891 159.312 127.449 ;
     RECT  161.7 2.151 162.012 127.449 ;
     RECT  164.4 2.151 164.712 127.449 ;
     RECT  167.1 56.531 167.412 127.449 ;
     RECT  169.8 2.151 170.112 127.449 ;
     RECT  172.5 43.571 172.812 127.449 ;
     RECT  175.2 2.151 175.512 127.449 ;
     RECT  177.9 2.151 178.212 127.449 ;
     RECT  180.6 85.139 180.912 127.449 ;
     RECT  183.3 2.151 183.612 127.449 ;
     RECT  186 106.643 186.312 127.449 ;
     RECT  188.7 16.595 189.012 127.449 ;
     RECT  191.4 106.067 191.712 127.449 ;
     RECT  194.1 106.643 194.412 127.449 ;
     RECT  196.8 95.939 197.112 127.449 ;
     RECT  199.5 57.923 199.812 127.449 ;
     RECT  202.2 82.787 202.512 127.449 ;
     RECT  204.9 27.347 205.212 127.449 ;
     RECT  207.6 123.731 207.912 127.449 ;
     RECT  210.3 122.675 210.612 127.449 ;
     RECT  213 115.523 213.312 127.449 ;
     RECT  2.4 127.449 2.52 127.463 ;
     RECT  5.1 127.449 5.22 127.463 ;
     RECT  7.8 127.449 7.92 127.463 ;
     RECT  10.5 127.449 10.62 127.463 ;
     RECT  13.2 127.449 13.32 127.463 ;
     RECT  15.9 127.449 16.02 127.463 ;
     RECT  18.6 127.449 18.72 127.463 ;
     RECT  21.3 127.449 21.42 127.463 ;
     RECT  24 127.449 24.12 127.463 ;
     RECT  26.7 127.449 26.82 127.463 ;
     RECT  29.4 127.449 29.52 127.463 ;
     RECT  32.1 127.449 32.22 127.463 ;
     RECT  34.8 127.449 34.92 127.463 ;
     RECT  37.5 127.449 37.62 127.463 ;
     RECT  40.2 127.449 40.32 127.463 ;
     RECT  42.9 127.449 43.02 127.463 ;
     RECT  45.6 127.449 45.72 127.463 ;
     RECT  48.3 127.449 48.42 127.463 ;
     RECT  51 127.449 51.12 127.463 ;
     RECT  53.7 127.449 53.82 127.463 ;
     RECT  56.4 127.449 56.52 127.463 ;
     RECT  59.1 127.449 59.22 127.463 ;
     RECT  61.8 127.449 61.92 127.463 ;
     RECT  64.5 127.449 64.62 127.463 ;
     RECT  67.2 127.449 67.32 127.463 ;
     RECT  69.9 127.449 70.02 127.463 ;
     RECT  72.6 127.449 72.72 127.463 ;
     RECT  75.3 127.449 75.42 127.463 ;
     RECT  78 127.449 78.12 127.463 ;
     RECT  80.7 127.449 80.82 127.463 ;
     RECT  83.4 127.449 83.52 127.463 ;
     RECT  86.1 127.449 86.22 127.463 ;
     RECT  88.8 127.449 88.92 127.463 ;
     RECT  91.5 127.449 91.62 127.463 ;
     RECT  94.2 127.449 94.32 127.463 ;
     RECT  96.9 127.449 97.02 127.463 ;
     RECT  99.6 127.449 99.72 127.463 ;
     RECT  102.3 127.449 102.42 127.463 ;
     RECT  105 127.449 105.12 127.463 ;
     RECT  107.7 127.449 107.82 127.463 ;
     RECT  110.4 127.449 110.52 127.463 ;
     RECT  113.1 127.449 113.22 127.463 ;
     RECT  115.8 127.449 115.92 127.463 ;
     RECT  118.5 127.449 118.62 127.463 ;
     RECT  121.2 127.449 121.32 127.463 ;
     RECT  123.9 127.449 124.02 127.463 ;
     RECT  126.6 127.449 126.72 127.463 ;
     RECT  129.3 127.449 129.42 127.463 ;
     RECT  132 127.449 132.12 127.463 ;
     RECT  134.7 127.449 134.82 127.463 ;
     RECT  137.4 127.449 137.52 127.463 ;
     RECT  140.1 127.449 140.22 127.463 ;
     RECT  142.8 127.449 142.92 127.463 ;
     RECT  145.5 127.449 145.62 127.463 ;
     RECT  148.2 127.449 148.32 127.463 ;
     RECT  150.9 127.449 151.02 127.463 ;
     RECT  153.6 127.449 153.72 127.463 ;
     RECT  156.3 127.449 156.42 127.463 ;
     RECT  159 127.449 159.12 127.463 ;
     RECT  161.7 127.449 161.82 127.463 ;
     RECT  164.4 127.449 164.52 127.463 ;
     RECT  167.1 127.449 167.22 127.463 ;
     RECT  169.8 127.449 169.92 127.463 ;
     RECT  172.5 127.449 172.62 127.463 ;
     RECT  175.2 127.449 175.32 127.463 ;
     RECT  177.9 127.449 178.02 127.463 ;
     RECT  180.6 127.449 180.72 127.463 ;
     RECT  183.3 127.449 183.42 127.463 ;
     RECT  186 127.449 186.12 127.463 ;
     RECT  188.7 127.449 188.82 127.463 ;
     RECT  191.4 127.449 191.52 127.463 ;
     RECT  194.1 127.449 194.22 127.463 ;
     RECT  196.8 127.449 196.92 127.463 ;
     RECT  199.5 127.449 199.62 127.463 ;
     RECT  202.2 127.449 202.32 127.463 ;
     RECT  204.9 127.449 205.02 127.463 ;
     RECT  207.6 127.449 207.72 127.463 ;
     RECT  210.3 127.449 210.42 127.463 ;
     RECT  213 127.449 213.12 127.463 ;
  END
END qkd_d2d_cal_seq_pin_ovl_rope
END LIBRARY
